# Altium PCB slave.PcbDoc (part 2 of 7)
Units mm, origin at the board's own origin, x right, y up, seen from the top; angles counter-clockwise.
Board outline 160 x 100 mm, 6 copper layers (Top, FUSED_VBAT-, Signals1, Signals2, SUPPLY, Bottom), stack 1.67 mm thick; 597 components, 381 nets, 1695 pads, 3029 vias.

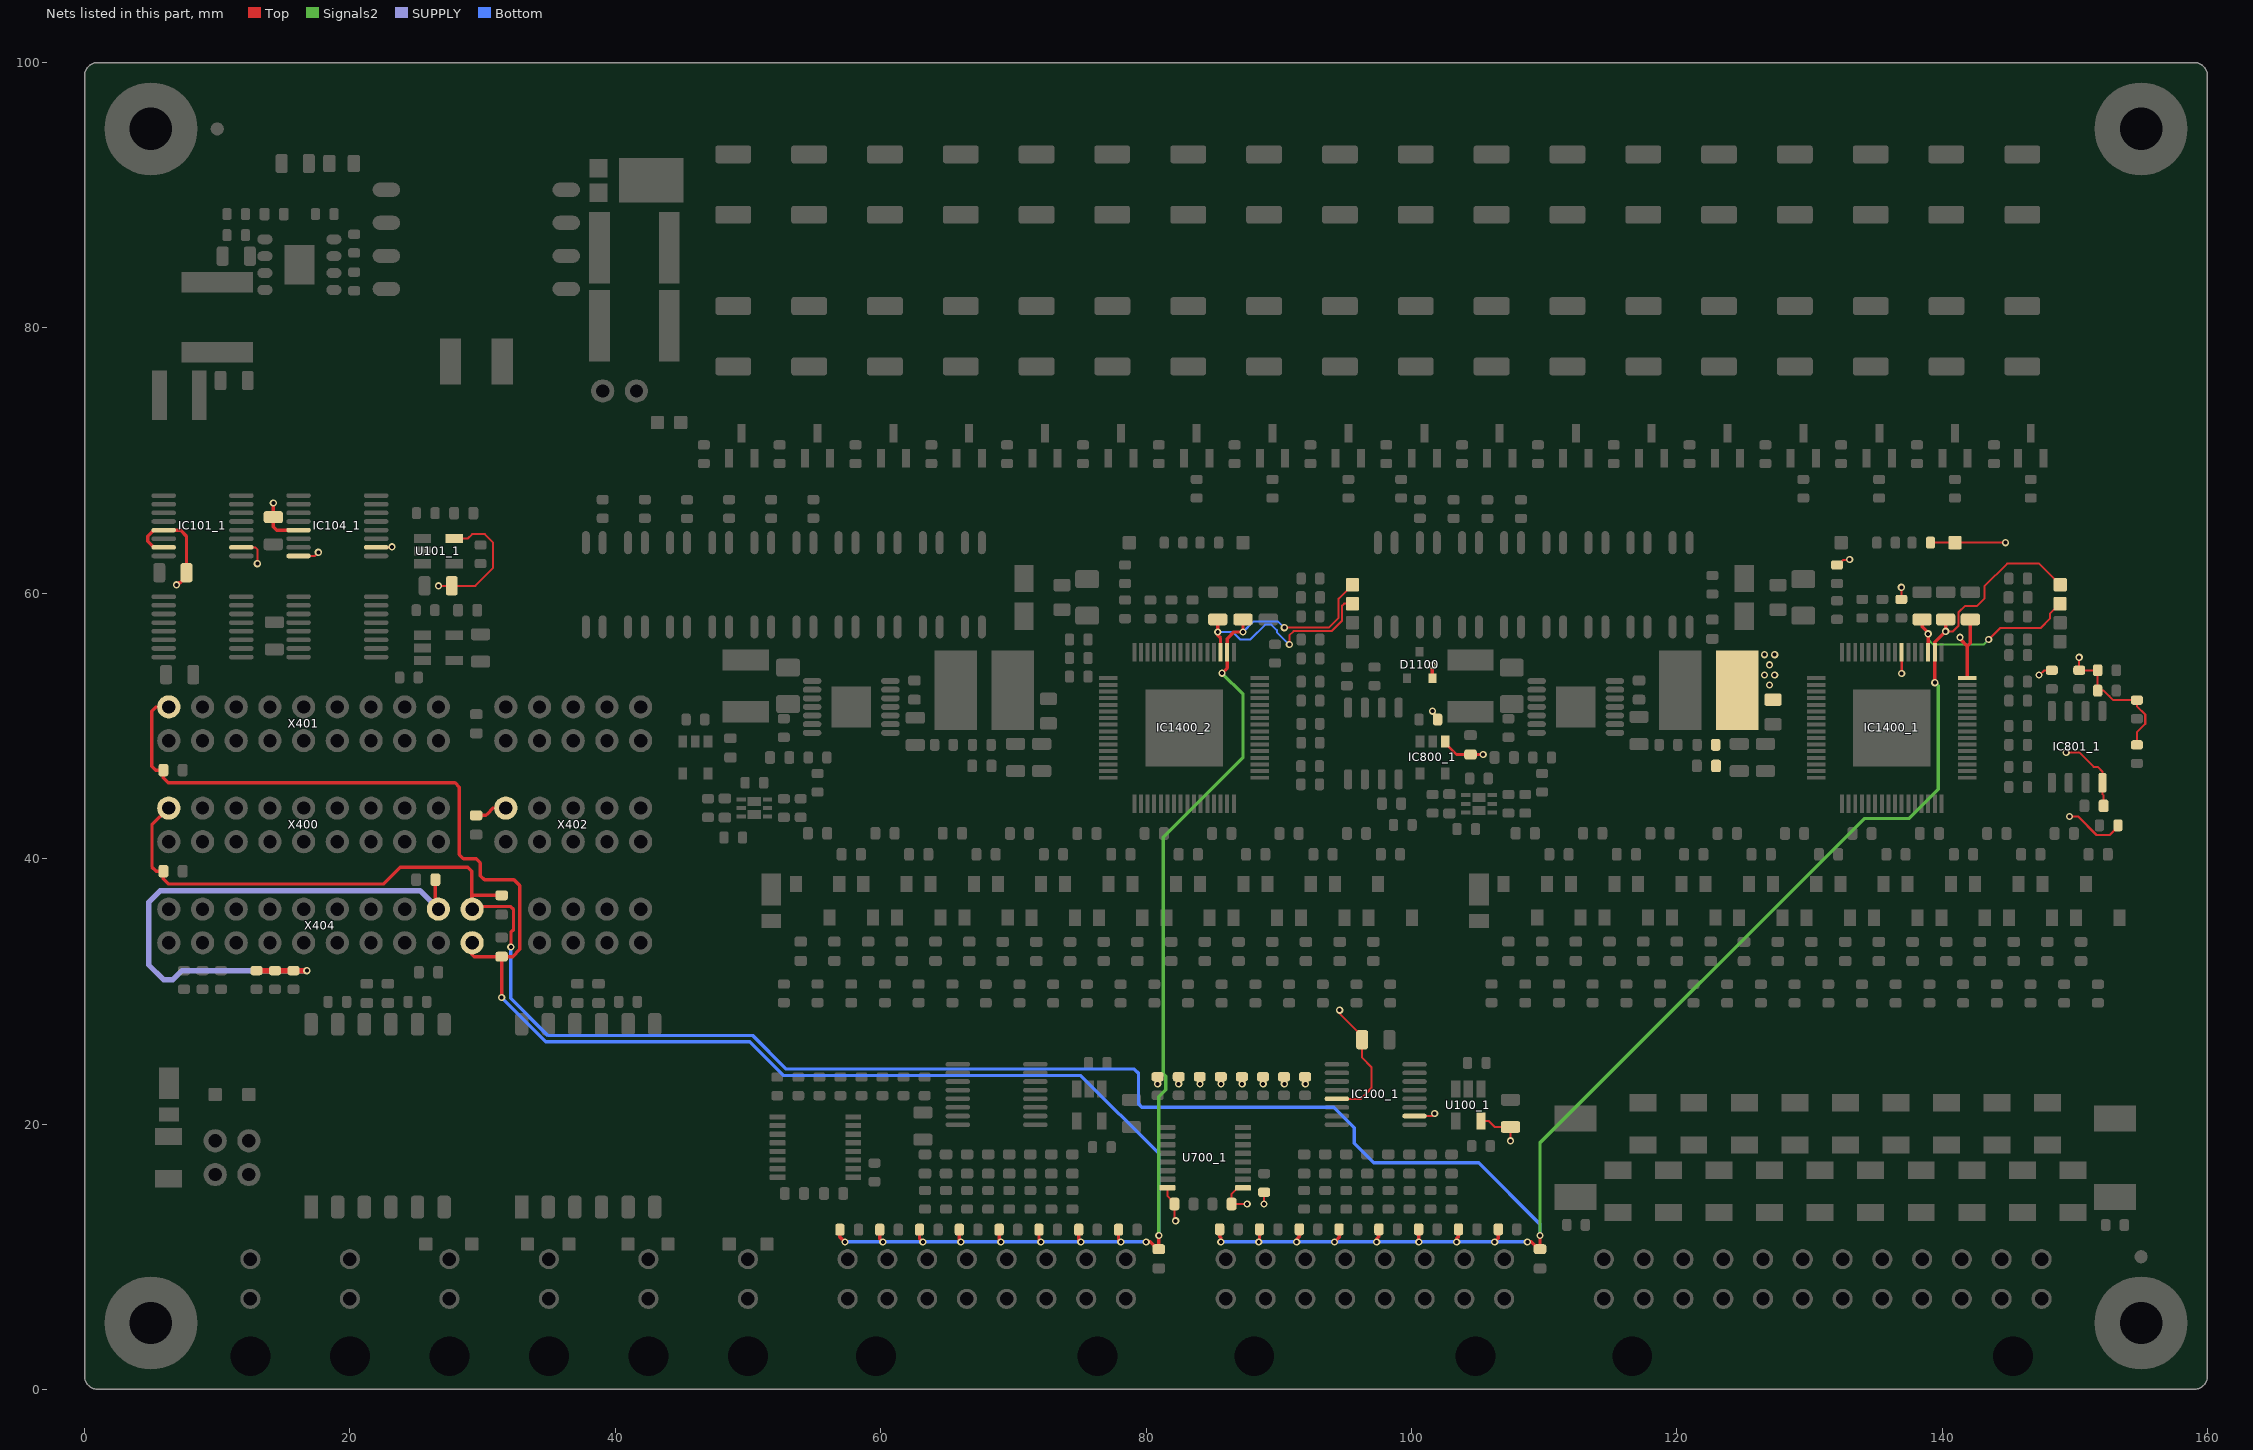
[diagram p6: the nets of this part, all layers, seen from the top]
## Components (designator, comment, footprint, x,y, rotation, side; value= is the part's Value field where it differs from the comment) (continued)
Z1312_1 "MMSZ4692T1G" ONSC-SOD-123-2-425-04_V 108.585,38.1 r0 top locked (schematic designator Z1312)
Z1312_2 "MMSZ4692T1G" ONSC-SOD-123-2-425-04_V 55.245,38.1 r0 top locked (schematic designator Z1312)
Z1313_1 "MMSZ4692T1G" ONSC-SOD-123-2-425-04_V 111.125,35.56 r0 top locked (schematic designator Z1313)
Z1313_2 "MMSZ4692T1G" ONSC-SOD-123-2-425-04_V 57.785,35.56 r0 top locked (schematic designator Z1313)
Z1314_1 "MMSZ4692T1G" ONSC-SOD-123-2-425-04_V 113.665,38.1 r0 top locked (schematic designator Z1314)
Z1314_2 "MMSZ4692T1G" ONSC-SOD-123-2-425-04_V 60.325,38.1 r0 top locked (schematic designator Z1314)
Z1315_1 "MMSZ4692T1G" ONSC-SOD-123-2-425-04_V 116.205,35.56 r0 top locked (schematic designator Z1315)
Z1315_2 "MMSZ4692T1G" ONSC-SOD-123-2-425-04_V 62.865,35.56 r0 top locked (schematic designator Z1315)
Z1316_1 "MMSZ4692T1G" ONSC-SOD-123-2-425-04_V 118.725,38.1 r0 top locked (schematic designator Z1316)
Z1316_2 "MMSZ4692T1G" ONSC-SOD-123-2-425-04_V 65.405,38.1 r0 top locked (schematic designator Z1316)
Z1317_1 "MMSZ4692T1G" ONSC-SOD-123-2-425-04_V 121.285,35.56 r0 top locked (schematic designator Z1317)
Z1317_2 "MMSZ4692T1G" ONSC-SOD-123-2-425-04_V 67.945,35.56 r0 top locked (schematic designator Z1317)

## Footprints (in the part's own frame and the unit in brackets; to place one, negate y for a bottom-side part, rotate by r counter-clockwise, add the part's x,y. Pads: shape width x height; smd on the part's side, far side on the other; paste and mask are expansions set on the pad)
ADI-RJ-5_M [mm] "SOT-23, 5-Leads, Body 2.9x1.6mm, Pitch 0.95mm, IPC Low Density"
  rect 1.3x0.7 smd: 1(-1.2,0.95) 2(-1.2,0) 3(-1.2,-0.95) 4(1.2,-0.95) 5(1.2,0.95)
  silkscreen extent -1.32,-1.5 0.15,1.98, body extent -0.85,-1.5 0.85,1.5, height 1.45
ADI-RU-16_M [mm] "SOP, 16-Leads, Body 5x4.4mm, Pitch 0.65mm, IPC Low Density"
  oval 1.85x0.35 smd: 1(-2.925,2.275) 2(-2.925,1.625) 3(-2.925,0.975) 4(-2.925,0.325) 5(-2.925,-0.325) 6(-2.925,-0.975) 7(-2.925,-1.625) 8(-2.925,-2.275) 9(2.925,-2.275) 10(2.925,-1.625) 11(2.925,-0.975) 12(2.925,-0.325) 13(2.925,0.325) 14(2.925,0.975) 15(2.925,1.625) 16(2.925,2.275)
  silkscreen extent -3.05,-2.55 1.6,3.12, body extent -2.25,-2.55 2.25,2.55, height 1.2
CAPC1608X08N [mm] "Chip Capacitor, 2-Leads, Body 1,60x0,80mm, IPC Medium Density"
  rrect50% 0.75x0.95 smd: 1(-0.725,0) 2(0.725,0)
  body extent -0.85,-0.45 0.85,0.45, height 0.8
CAPC2012X14N [mm] "Chip Capacitor, 2-Leads, Body 2,00x1,25mm, IPC Medium Density"
  rrect40% 0.9x1.45 smd: 1(-1.025,0) 2(1.025,0)
  silkscreen extent -0.2,-0.63 0.2,0.63, body extent -1.1,-0.72 1.1,0.72, height 1.45
CAPC2220(5750)230_N [mm] "Chip Capacitor, Body 5.7x5.0mm, Height 2.3mm, IPC Medium Density"
  rect 1.55x5.4 smd: 1(-2.625,0) 2(2.625,0)
  silkscreen extent -1.45,-2.6 1.45,2.6, body extent -3.05,-2.7 3.05,2.7, height 2.3
CAPC3216X18N [mm] "Chip Capacitor, 2-Leads, Body 3,20x1,60mm, IPC Medium Density"
  rrect30% 1.35x1.8 smd: 1(-1.375,0) 2(1.375,0)
  silkscreen extent -0.3,-0.8 0.3,0.8, body extent -1.7,-0.9 1.7,0.9, height 1.8
CAPC4532X16N [mm] "Chip Capacitor, 2-Leads, Body 4,50x3,20mm, IPC Medium Density"
  rect 1.6x3.5 smd: 1(-1.95,0) 2(1.95,0)
  silkscreen extent -0.75,-1.65 0.75,1.65, body extent -2.4,-1.75 2.4,1.75, height 1.55
DIOD-POWERDI123-2_V [mm] "SOD, 2-Leads, Body 2.8x1.78mm"
  rect 1.05x1.5 smd: 1(-1.525,0)
  rect 2.4x1.5 smd: 2(0.85,0)
  silkscreen extent 2.55,-0.89 2.55,0.89, body extent -1.4,-0.89 1.4,0.89, height 1.01
Fiducial_2 [mm] "Fiducial Round 1mm"
  round 1 smd paste-0.5 mask+0.5: 0(0,0)
  Top keep-out circle w0.2: c0,0 r0.9
HM2102NL [mil]
  rect 67.5x40 smd: 1(-271.65,196.85)
  rrect50% 67.5x40 smd: 2(-271.65,117.85) 3(-271.65,38.85) 4(-271.65,-40.15) 5(-271.65,-119.15) 6(-271.65,-198.15) 7(270.85,-198.15) 8(270.85,-119.15) 9(270.85,-40.15) 10(270.85,38.85) 11(270.85,117.85) 12(270.85,196.85)
  silkscreen extent -224,-300 224,300, body extent -224,-299 224,299, height 197
Hole_3.2_Iso [mm]
  round 7 hole 3.2: Hole_3.2(0,0)
LEDC1608X07N [mm] "LED, 2-Leads, Body 1,60x0,80mm, IPC Medium Density"
  rrect50% 0.7x0.9 smd: 1(-0.7,0) 2(0.7,0)
  silkscreen extent -1.35,0.35 -1.25,0.45, body extent -0.8,-0.4 0.8,0.4, height 0.7
LITTLEFUSE_448 [mm] "Littlefuse 448 Series, 2-Leads, Body 6,10x2,69mm, IPC Medium Density"
  rect 1.96x3.15 smd: 1(-2.95,0) 2(2.95,0)
  silkscreen extent -1.1,-1.47 1.1,1.48, body extent -3.15,-1.47 3.15,1.47, height 2.94
LITTLEFUSE_466 [mm] "Littlefuse 466 Series, 2-Leads, Body 3,18x1,52mm"
  rect 1.3x2.03 smd: 1(-1.59,0) 2(1.59,0)
  silkscreen extent -0.55,-0.92 0.55,0.91, body extent -1.65,-0.82 1.65,0.82, height 0.66
LT-S8E-8_V [mm] "SOIC, 8-Leads, Body 4.9x3.9mm, Pitch 1.27mm, Thermal Pad 3.25x2.26mm, Recommended"
  oval 1.143x0.76 smd: 1(-2.602,1.905) 2(-2.602,0.635) 3(-2.602,-0.635) 4(-2.602,-1.905) 5(2.601,-1.905) 6(2.601,-0.635) 7(2.601,0.635) 8(2.601,1.905)
  rect 2.26x2.99 smd: 9(0,0)
  silkscreen extent -2.73,-2.5 1.62,2.96, body extent -3.01,-2.45 3.01,2.45, height 1.75
MOLEX_MICROFIT_01x2_THT [mil] "Micro-Fit 3.0 Right Angle Header, 3.00mm Pitch, Dual Row, 2 Circuits, with Snap-in Plastic Peg PCB Lock, Tin, Glow Wire Capable, Black, 43045-0200"
  round 60 hole 40: 1(0,-170) 2(0,-287.99)
  round 39.37 hole 117.99 unplated paste+0 mask+4: ""(0,0)
  silkscreen extent -137,-209 137,85, body extent -141,-301 141,181, height 345
MOLEX_MICROFIT_08x2_THT [mil] "Micro-Fit 3.0 Right Angle Header, 3.00mm Pitch, Dual Row, 16 Circuits, with Snap-in Plastic Peg PCB Lock, Tin, Glow Wire Capable, Black, 43045-1600"
  round 60 hole 40: 1(-412.99,-170) 2(-295,-170) 3(-177.01,-170) 4(-59.02,-170) 5(59.02,-170) 6(177.01,-170) 7(295,-170) 8(412.99,-170) 9(-412.99,-287.99) 10(-295,-287.99) 11(-177.01,-287.99) 12(-59.02,-287.99) 13(59.02,-287.99) 14(177.01,-287.99) 15(295,-287.99) 16(412.99,-287.99)
  round 39.37 hole 117.99 unplated paste+0 mask+4: ""(-328.5,0) ""(328.5,0)
  silkscreen extent -551,-209 551,85, body extent -554,-301 554,181, height 345
MOLEX_MICROFIT_12x2_THT [mil] "Micro-Fit 3.0 Right Angle Header, 3.00mm Pitch, Dual Row, 24 Circuits, with Snap-in Plastic Peg PCB Lock, Tin, Glow Wire Capable, Black, 43045-2400"
  round 60 hole 40: 1(-649.49,-170) 2(-530.98,-170) 3(-412.99,-170) 4(-295,-170) 5(-177.01,-170) 6(-59.02,-170) 7(59.02,-170) 8(177.01,-170) 9(295,-170) 10(412.99,-170) 11(530.98,-170) 12(649.49,-170) 13(-649.49,-287.99) 14(-530.98,-287.99) 15(-412.99,-287.99) 16(-295,-287.99) 17(-177.01,-287.99) 18(-59.02,-287.99) 19(59.02,-287.99) 20(177.01,-287.99) 21(295,-287.99) 22(412.99,-287.99) 23(530.98,-287.99) 24(649.49,-287.99)
  round 39.37 hole 117.99 unplated paste+0 mask+4: ""(-565,0) ""(565,0)
  silkscreen extent -789,-209 790,85, body extent -790,-301 790,181, height 345
NXP-SOT23-3_V [mm] "SOT23, 3-Leads, Body 1.3x2.9mm, Pitch 0.95mm"
  rect 0.6x0.7 smd paste-0.05: 1(0.95,1) 2(-0.95,1) 3(0,-1)
  silkscreen extent -1.45,-0.65 1.45,1.79, body extent -1.45,-0.65 1.45,0.65, height 1.1
NXP-SOT23_N [mm] "SOT23, 3-Leads, Body 3x1.4mm, Pitch 0.95mm, IPC Medium Density"
  rect 1.4x0.6 smd: 1(-0.95,0.95) 2(-0.95,-0.95) 3(0.95,0)
  silkscreen extent -1.07,-1.5 0.7,1.92, body extent -0.7,-1.5 0.7,1.5, height 1.1
ONSC-SOD-123-2-425-04_V [mm] "SOD, 2-Leads, Body 2.69x1.6mm"
  rect 0.91x1.22 smd: 1(-1.635,0) 2(1.635,0)
  silkscreen extent -1.76,-0.8 0.78,1.28, body extent -1.35,-0.8 1.35,0.8, height 1.35
PBSS4112PANP [mm]
  rect 0.7x0.3 smd: 1(-0.995,0.65) 2(-0.995,0) 3(-0.995,-0.65) 4(0.995,-0.65) 5(0.995,0) 6(0.995,0.65)
  rect 1x0.67 smd: 7(0,0.49) 8(0,-0.49)
  silkscreen extent -1.5,-1.2 1.05,1.25, body extent -1.05,-1.05 1.05,1.05, height 0.65
Pinheader_2.54_2 [mm] "Pinheader, 2.54mm, gerade"
  round 1.75 hole 1: 1(-1.27,0) 2(1.27,0)
  silkscreen extent -2.47,-1.2 2.47,1.2, body extent -2.54,-1.27 2.54,1.27, height 8.74
Pinheader_2.54_2x2 [mm] "Pinheader, 2.54mm, gerade, 2-reihig"
  round 1.75 hole 1: 1(-1.27,-1.27) 2(-1.27,1.27) 3(1.27,-1.27) 4(1.27,1.27)
  silkscreen extent -2.47,-2.47 2.47,2.47, body extent -2.54,-2.54 2.54,2.54, height 8.74
Pinheader_2.54_2x4 [mm] "Pinheader, 2.54mm, gerade, 2-reihig"
  round 1.75 hole 1: 1(-3.81,-1.27) 2(-3.81,1.27) 3(-1.27,-1.27) 4(-1.27,1.27) 5(1.27,-1.27) 6(1.27,1.27) 7(3.81,-1.27) 8(3.81,1.27)
  silkscreen extent -5.01,-2.47 5.01,2.47, body extent -5.08,-2.54 5.08,2.54, height 8.74
Pinheader_2.54_2x5 [mm]
  round 1.75 hole 1: 1(-5.08,-1.27) 2(-5.08,1.27) 3(-2.54,-1.27) 4(-2.54,1.27) 5(0,-1.27) 6(0,1.27) 7(2.54,-1.27) 8(2.54,1.27) 9(5.08,-1.27) 10(5.08,1.27)
  silkscreen extent -6.28,-2.47 6.28,2.47, body extent -6.35,-2.54 6.35,2.54, height 8.74
Pinheader_2.54_2x9 [mm] "Pinheader, 2.54mm, gerade, 2-reihig"
  round 1.75 hole 1: 1(-10.16,-1.27) 2(-10.16,1.27) 3(-7.62,-1.27) 4(-7.62,1.27) 5(-5.08,-1.27) 6(-5.08,1.27) 7(-2.54,-1.27) 8(-2.54,1.27) 9(0,-1.27) 10(0,1.27) 11(2.54,-1.27) 12(2.54,1.27) 13(5.08,-1.27) 14(5.08,1.27) 15(7.62,-1.27) 16(7.62,1.27) 17(10.16,-1.27) 18(10.16,1.27)
  silkscreen extent -11.43,-2.47 11.43,2.47, body extent -11.43,-2.54 11.43,2.54, height 8.74
Pinheader_2.54_2x10 [mm] "Pinheader, 2.54mm, gerade, 2-reihig"
  round 1.75 hole 1: 1(-11.43,-1.27) 2(-11.43,1.27) 3(-8.89,-1.27) 4(-8.89,1.27) 5(-6.35,-1.27) 6(-6.35,1.27) 7(-3.81,-1.27) 8(-3.81,1.27) 9(-1.27,-1.27) 10(-1.27,1.27) 11(1.27,-1.27) 12(1.27,1.27) 13(3.81,-1.27) 14(3.81,1.27) 15(6.35,-1.27) 16(6.35,1.27) 17(8.89,-1.27) 18(8.89,1.27) 19(11.43,-1.27) 20(11.43,1.27)
  silkscreen extent -12.7,-2.47 12.7,2.47, body extent -12.7,-2.54 12.7,2.54, height 8.74
PowerDI5 [mm] "PowerDI5, 3-Leads, Body 3,97x6,50mm"
  rect 4.86x3.36 smd: 1(1.126,0)
  rect 1.39x1.4 smd: 2(-2.856,0.92) 3(-2.856,-0.92)
  silkscreen extent -1.88,-2.05 3.63,2.32, body extent -3.25,-2.02 3.25,2.02, height 1.15
PW0016A_L [mm] "SOP, 16-Leads, Body 5.1x4.5mm, Pitch 0.65mm, IPC High Density"
  rrect25% 1.2x0.4 smd: 1(-2.85,2.275) 2(-2.85,1.625) 3(-2.85,0.975) 4(-2.85,0.325) 5(-2.85,-0.325) 6(-2.85,-0.975) 7(-2.85,-1.625) 8(-2.85,-2.275) 9(2.85,-2.275) 10(2.85,-1.625) 11(2.85,-0.975) 12(2.85,-0.325) 13(2.85,0.325) 14(2.85,0.975) 15(2.85,1.625) 16(2.85,2.275)
  silkscreen extent -2.98,-2.55 1.85,3.15, body extent -3.21,-2.5 3.21,2.5, height 1
PWP0014A [mm] "TI PWP0014A Package"
  oval 1.4x0.45 smd: 1(-2.95,1.95) 2(-2.95,1.3) 3(-2.95,0.65) 4(-2.95,0) 5(-2.95,-0.65) 6(-2.95,-1.3) 7(-2.95,-1.95) 8(2.95,-1.95) 9(2.95,-1.3) 10(2.95,-0.65) 11(2.95,0) 12(2.95,0.65) 13(2.95,1.3) 14(2.95,1.95)
  rect 3x3.1 smd: 15(0,0)
  silkscreen extent -3.07,-2.55 1.85,2.85, body extent -3.2,-2.55 3.2,2.55, height 1.2
RESC1608X05N [mm] "Chip Resistor, 2-Leads, Body 1,60x0,80mm, IPC Medium Density"
  rrect50% 0.7x0.9 smd: 1(-0.7,0) 2(0.7,0)
  body extent -0.85,-0.45 0.85,0.45, height 0.45
RESC2012X05N [mm] "Chip Resistor, 2-Leads, Body 2,00x1,20mm, IPC Medium Density"
  rrect40% 0.95x1.3 smd: 1(-0.925,0) 2(0.925,0)
  silkscreen extent -0.05,-0.55 0.05,0.55, body extent -1.05,-0.65 1.05,0.65, height 0.5
RESC5025X07N [mm] "Chip Resistor, 2-Leads, Body 5,00x2,50mm, IPC Medium Density"
  rrect30% 1.35x2.7 smd: 1(-2.275,0) 2(2.275,0)
  silkscreen extent -1.2,-1.25 1.2,1.25, body extent -2.6,-1.35 2.6,1.35, height 0.7
SOIC127P600X175-8N [mm] "SOIC, 8-Leads, Body 4,90x3,90mm, Pitch 1,27mm, IPC Medium Density"
  rrect50% 1.5x0.6 smd: 1(-2.7,1.905) 2(-2.7,0.635) 3(-2.7,-0.635) 4(-2.7,-1.905) 5(2.7,-1.905) 6(2.7,-0.635) 7(2.7,0.635) 8(2.7,1.905)
  silkscreen extent -2.8,-2.45 1.55,2.8, body extent -3,-2.45 3,2.45, height 1.75
SOIC127P700X220-4N [mm] "SOIC, 4-Leads, Body 2,60x4,40mm, Pitch 1,27mm, IPC Medium Density"
  oval 1.75x0.6 smd: 1(-3.175,0.635) 2(-3.175,-0.635) 3(3.175,-0.635) 4(3.175,0.635)
  silkscreen extent -3.3,-1.45 1.9,1.61, body extent -3.5,-1.45 3.5,1.45, height 2.2
SOT-23-OT5_L [mm] "SOT23, 5-Leads, Body 2.9x1.7mm, Pitch 0.95mm, Lead Span 2.8mm, IPC High Density"
  rect 0.9x0.65 smd: 1(-1.2,0.95) 2(-1.2,0) 3(-1.2,-0.95) 4(1.2,-0.95) 5(1.2,0.95)
  silkscreen extent -1.32,-1.55 0.35,1.95, body extent -0.9,-1.55 0.9,1.55, height 1.45
Testpoint_S1 [mm] "Testpunkt, quardratisch 1mm"
  rrect20% 1x1 smd paste-0.5: 1(0,0)
TSQFP50P1200X1200X160_HS-65N [mm] "TSQFP, 64-Leads, Body 10,00x10,00mm, Pitch 0,50mm, Thermal Pad 5,84x5,84mm, IPC Medium Density"
  rect 1.4x0.3 smd: 1(-5.7,3.75) 2(-5.7,3.25) 3(-5.7,2.75) 4(-5.7,2.25) 5(-5.7,1.75) 6(-5.7,1.25) 7(-5.7,0.75) 8(-5.7,0.25) 9(-5.7,-0.25) 10(-5.7,-0.75) 11(-5.7,-1.25) 12(-5.7,-1.75) 13(-5.7,-2.25) 14(-5.7,-2.75) 15(-5.7,-3.25) 16(-5.7,-3.75) 33(5.7,-3.75) 34(5.7,-3.25) 35(5.7,-2.75) 36(5.7,-2.25) 37(5.7,-1.75) 38(5.7,-1.25) 39(5.7,-0.75) 40(5.7,-0.25) 41(5.7,0.25) 42(5.7,0.75) 43(5.7,1.25) 44(5.7,1.75) 45(5.7,2.25) 46(5.7,2.75) 47(5.7,3.25) 48(5.7,3.75)
  rect 0.3x1.4 smd: 17(-3.75,-5.7) 18(-3.25,-5.7) 19(-2.75,-5.7) 20(-2.25,-5.7) 21(-1.75,-5.7) 22(-1.25,-5.7) 23(-0.75,-5.7) 24(-0.25,-5.7) 25(0.25,-5.7) 26(0.75,-5.7) 27(1.25,-5.7) 28(1.75,-5.7) 29(2.25,-5.7) 30(2.75,-5.7) 31(3.25,-5.7) 32(3.75,-5.7) 49(3.75,5.7) 50(3.25,5.7) 51(2.75,5.7) 52(2.25,5.7) 53(1.75,5.7) 54(1.25,5.7) 55(0.75,5.7) 56(0.25,5.7) 57(-0.25,5.7) 58(-0.75,5.7) 59(-1.25,5.7) 60(-1.75,5.7) 61(-2.25,5.7) 62(-2.75,5.7) 63(-3.25,5.7) 64(-3.75,5.7)
  rect 5.84x5.84 smd: 65(0,0)
  silkscreen extent -5.82,-4.6 4.6,4.6, body extent -6,-6 6,6, height 1.6
TYS6045221M-10 [mm] "Precision Wire Wound Inductor, 2-Leads, Body 6,00x6,00mm, IPC Medium Density"
  rect 3.2x6 smd: 1(-2.15,0) 2(2.15,0)
  silkscreen extent -4.05,-3.15 0.15,3.15, body extent -3.1,-3 3.1,3, height 4.8
VISH-DO-214AC-2_L [mm] "DO-214AC, 2-Leads, Body 4.5x2.79mm, IPC High Density"
  rect 2.05x1.45 smd: 1(-1.425,0) 2(1.425,0)
  silkscreen extent -3.12,-1.4 2.25,1.4, body extent -2.25,-1.4 2.25,1.4, height 2.29
"WE-LQS 4018" [mm] "SMD Power Inductor, 2-Leads, Body 4.0x4.0mm"
  rect 1.1x3.7 smd: 1(-1.5,0) 2(1.5,0)
  body extent -2,-2 2,2, height 1.78
WE_750313457 [mm] "Würth Elektronik 750313457"
  oval 2.08x1.07 smd: 1(-6.78,-3.735) 2(-6.78,-1.245) 3(-6.78,1.245) 4(-6.78,3.735) 5(6.78,3.735) 6(6.78,1.245) 7(6.78,-1.245) 8(6.78,-3.735)
  silkscreen extent -6.98,-6.65 5.43,6.65, body extent -7.62,-6.65 7.62,6.65, height 11.44

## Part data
C100_1 C100_2 C400 C401 C402 C403 C404 C405 C406 C407 C602_1 C602_2 C604_1 C604_2 C607_1 C607_2 C700_1 C700_2 C701_1 C701_2 C800_1 C800_2 C801_1 C801_2 C903 C1100: library part gen_C_ceramic_100n_50V_X7R_0603, "MLCC", Capacitance=100n, Case EIA=0603, Case Metric=1608, Dielectric=X7R, PnP Package=C_0603_10, PnP Value=100n/50V/X7R, Rated Voltage=50V, Supplier Part Number 1=2525267
C101_1 C101_2 C102_1 C102_2 C103_1 C103_2 C104_1 C104_2 C105_1 C105_2 C603_1 C603_2 C900 C904 C1401_1 C1401_2 C1402_1 C1402_2 C1403_1 C1403_2: library part gen_C_ceramic_1u_50V_X7R_0805, "MLCC", Capacitance=1u, Case EIA=0805, Case Metric=2012, Dielectric=X7R, Operating Temperature="-55°C - +125°C", Rated Voltage=50V, Supplier Part Number 1=2672199, Tolerance="± 10%"
C106_1 C106_2 C107_1 C107_2 C108_1 C108_2 C109_1 C109_2 C110_1 C110_2 C111_1 C111_2 C112_1 C112_2 C113_1 C113_2 C114_1 C114_2 C115_1 C115_2 C608_1 C608_2 C1300_1 C1300_2 C1301_1 C1301_2 C1302_1 C1302_2 C1303_1 C1303_2 C1304_1 C1304_2 C1305_1 C1305_2 C1306_1 C1306_2 C1307_1 C1307_2 C1308_1 C1308_2 C1309_1 C1309_2 C1310_1 C1310_2 C1311_1 C1311_2 C1312_1 C1312_2 C1313_1 C1313_2 C1314_1 C1314_2 C1315_1 C1315_2 C1316_1 C1316_2 C1317_1 C1317_2 C1318_1 C1318_2 C1319_1 C1319_2 C1320_1 C1320_2 C1321_1 C1321_2 C1322_1 C1322_2 C1323_1 C1323_2 C1324_1 C1324_2 C1325_1 C1325_2 C1326_1 C1326_2 C1327_1 C1327_2 C1328_1 C1328_2 C1329_1 C1329_2 C1330_1 C1330_2 C1331_1 C1331_2 C1332_1 C1332_2 C1333_1 C1333_2 C1334_1 C1334_2 C1335_1 C1335_2: library part gen_C_ceramic_10n_100V_X7R_0603, "MLCC", Capacitance=10n, Case EIA=0603, Case Metric=1608, Dielectric=X7R, Rated Voltage=100V, Supplier Part Number 1=1301715
C600_1 C600_2: library part gen_C_ceramic_1u_250V_X7R_1812, "MLCC", Capacitance=1u, Case EIA=1812, Case Metric=4532, Dielectric=X7T, Rated Voltage=250V, Supplier Part Number 1=2435499
C601_1 C601_2 C1400_1 C1400_2: library part gen_C_ceramic_100n_200V_X7R_1206, "MLCC", Capacitance=100n, Case EIA=1206, Case Metric=3216, Dielectric=X7R, Rated Voltage=200V, Supplier Part Number 1=2673161
C605_1 C605_2 C606_1 C606_2: library part gen_C_ceramic_2u2_10V_X7R_0805, "MLCC", Capacitance=2u2, Case EIA=0805, Case Metric=2012, Dielectric=X7R, Rated Voltage=10V, Supplier Part Number 1=2478259
C902: library part gen_C_ceramic_22u_50V_X7R_2220_stacked, "MLCC", Capacitance=22u, Case EIA=2220, Case Metric=5750, Dielectric=X7R, Rated Voltage=50V, Supplier Part Number 1=399-5797-1-ND
C905: library part gen_C_ceramic_470p_100V_X7R_0805, "MLCC", Capacitance=470p, Case EIA=0805, Case Metric=2012, Dielectric=X7R, Rated Voltage=100V, Supplier Part Number 1=2070482
C906: library part gen_C_ceramic_4n7_1000V_X7R_1812, "MLCC", Capacitance=4n7, Case EIA=1812, Case Metric=4532, Dielectric=X7R, Rated Voltage=1000V, Supplier Part Number 1=2834565
C907 C908: library part gen_C_ceramic_2u2_250V_X7R_2220, "MLCC", Capacitance=2u2, Case EIA=2220, Case Metric=5750, Dielectric=X7R, Rated Voltage=250V, Supplier Part Number 1=445-7997-2-ND
C1404_1 C1404_2 C1405_1 C1405_2: library part gen_C_ceramic_100p_50V_C0G_0603, "MLCC", Capacitance=100p, Case EIA=0603, Case Metric=1608, Dielectric=C0G, Rated Voltage=50V, Supplier Part Number 1=2478236, Tolerance="± 10%"
D900 D1400_1 D1400_2: library part CMP-2000-05099-1, "1 A High Voltage Schottky Barrier Rectifier, 0.62 V, -55 to 175 degC, 2- Pin POWERDI123, Pb-Free, Tape and Reel", Average Rectified Current-Max=1A, Forward Voltage=0.77V, Manufacturer="Diodes Inc", Peak Current-Max=40A, Reverse Current-Max=1µA, Reverse Voltage-Max [Vrrm]=100V
D901: library part PDS3200-13, "Schottky Diode 3A 200V 780mV", Breakdown Voltage=200V, Continuous Forward Current=3A, Manufacturer="DIODES Inc", Operating Temperature="-65°C - +150°C", Supplier Part Number 1=1713904
D1100: library part CMP-2000-04915-1, "Schottky Barrier Diode, 30 V, 3-Pin SOT23, RoHS, Tape and Reel", Current Ifsm=600mA, Diode Case Style=SOT-23, Forward Current If(AV)=200mA, Forward Voltage=800mV, Junction Temperature Tj Max=125degC, Manufacturer="NXP Semiconductors", Operating Temperature Max=150degC, Operating Temperature Min=-65degC, Operating Temperature Range=-65degCto+150degC, Package Description="3-Pin Small Outline Transistor, Body 1.3 x 2.9 mm, Pitch 0.95 mm", Package Reference=SOT23-3, Package Version=Feb-16, Repetitive Reverse Voltage Vrrm Max=30V
D1401_1 D1401_2: library part CMP-0548-00243-2, "Transient Voltage Suppressor, 6.40 to 231 V, 85 V Stand-off Voltage, Uni-Directional, -55 to 155 degC, 2-pin DO-214AC, Pb-Free, Tape and Reel", Manufacturer="Vishay Semiconductor", Operating Junction and Storage Temperature Range="-55 to 150 degC"
F300 F320: "Fuse, Surface Mount, NANO2 Series, 500 mA, 125 VAC, 32 VDC, Very Fast Acting, SMD", Manufacturer=Littlefuse, Operating Temperature="-55°C - +125°C", Supplier Part Number 1=1596919
F301 F302 F303 F304 F305 F306 F307 F308 F309 F310 F311 F312 F313 F314 F315 F316 F317 F318 F319: "Fuse, Surface Mount, 466 Series, 250 mA, 125 VAC, 125 VDC, Very Fast Acting, 1206", Manufacturer=Littlefuse, Operating Temperature="-55°C - +90°C", Supplier Part Number 1=9921826
F900: "Fuse, Surface Mount, 466 Series, 1.25 A, 63 VAC, 63 VDC, Very Fast Acting, 1206", Manufacturer=Littlefuse, Operating Temperature="-55°C - +90°C", Supplier Part Number 1=1596526
IC100_1 IC100_2 IC101_1 IC101_2 IC104_1 IC104_2: library part CMP-0798-00197-1, "CMOS, Low Voltage, 2-Wire Serially Controlled, Matrix Switch, -40 to 85 degC, 16-pin SOP (RU-16), Tube", Manufacturer="Analog Devices"
IC800_1 IC800_2: library part CMP-0192-00211-1, "2-Wire High-Accuracy Temperature Sensor, Slave Address 000, 5-Pin SOT-23, -55°C to +125°C Temperature, Tape and Reel"
IC801_1 IC801_2: "Automotive 2-Mbit serial I²C  / bus EEPROM with 1 MHz clock", Manufacturer=STMicroelectronics, Operating Temperature="-40°C - +125°C", PnP Package=SO8N, Supplier Part Number 1=497-16238-1-ND
IC900: library part CMP-0492-02715-1, "Micropower No-Opto Isolated Flyback Converter, 2.8 to 42 V, -40 to 150 degC, 8-Pin SOIC (S8E), RoHS, Tube", Output Current="3.6 A", PartNumber=LT8302, Temperature Max="150 degC", Temperature Min="-40 degC"
IC1400_1 IC1400_2: "18 Cell Multicell Battery Monitor, -40 to 125 degC, Pb-Free", Manufacturer="Linear Technology", Operating Temperature="-40°C - +125°C", PartNumber=LTC6811HG-1#PBF, PnP Package=QFP-64, Supplier Part Number 1=LTC6813HLWE-1#3ZZPBF-ND
L600_1 L600_2: library part TYS6045221M-10, "Power Inductor", Manufacturer="Laird-Signal Integrity Products", Operating Temperature="-55°C - +150°C", Rated Current=590mA, Saturation Current=700mA, Supplier Part Number 1=240-2742-1-ND
L900: library part CMP-1354-00028-1, "WE-LQS SMD Power Inductor, L=10 µH", Inductance="10 µH", Manufacturer="Wuerth Elektronik"
LD1400_1 LD1400_2: library part LED_0603_green_AECQ, "TLMG1100-GS08", Breakdown Voltage=5V, Continuous Forward Current=20mA, Forward Voltage @ 20mA=2.1V, Manufacturer=Vishay, Operating Temperature="-40°C - 100°C", PnP Package=LED_0603, Supplier Part Number 1=2293494
Q600_1 Q600_2: "Dual NPN/PNP Transistor", Manufacturer=Nexperia, Maximum Continous Drain Current (25°C)=1A, Maximum Drain-Source Voltage=120V, Operating Temperature="-55°C - +150°C", Part Name="DUAL PNP/NPN"
R100_1 R100_2 R101_1 R101_2 R102_1 R102_2 R103_1 R103_2 R104_1 R104_2 R105_1 R105_2 R106_1 R106_2 R107_1 R107_2 R601_1 R601_2 R605_1 R605_2 R607_1 R607_2 R700_1 R700_2 R701_1 R701_2 R702_1 R702_2 R703_1 R703_2 R704_1 R704_2 R705_1 R705_2 R706_1 R706_2 R707_1 R707_2 R708_1 R708_2 R800_1 R800_2 R801_1 R801_2 R905 R1118 R1421_1 R1421_2 R1422_1 R1422_2 R1423_1 R1423_2 R1424_1 R1424_2 R1425_1 R1425_2 R1426_1 R1426_2 R1427_1 R1427_2: library part gen_R_10k_0603, "SMD Resistor 10k 0603", Case EIA=0603, Case Metric=1608, Maximum Working Voltage=75V, Operating Temperature="-55°C - +155°C", PnP Package=R_0603, Power=0.1W, Supplier Part Number 1=2073349, Tolerance=1%
R108_1 R108_2 R109_1 R109_2 R112_1 R112_2 R113_1 R113_2 R114_1 R114_2 R115_1 R115_2 R116_1 R116_2 R117_1 R117_2 R118_1 R118_2 R119_1 R119_2: library part gen_R_100R_0603, "SMD Resistor 100R 0603", Case EIA=0603, Case Metric=1608, Maximum Working Voltage=75V, Operating Temperature="-55°C - +155°C", PnP Package=R_0603, Power=0.1W, Supplier Part Number 1=P100HCT-ND, Tolerance=1%
R110_1 R110_2 R111_1 R111_2 R609_1 R609_2 R610_1 R610_2 R1406_1 R1406_2 R1407_1 R1407_2 R1408_1 R1408_2 R1409_1 R1409_2 R1410_1 R1410_2 R1411_1 R1411_2 R1412_1 R1412_2 R1413_1 R1413_2 R1414_1 R1414_2 R1415_1 R1415_2 R1416_1 R1416_2 R1417_1 R1417_2 SJ300 SJ301: library part gen_R_0R_0603, "SMD Resistor 0R 0603", Case EIA=0603, Case Metric=1608, Maximum Working Voltage=75V, Operating Temperature="-55°C - +155°C", PnP Package=R_0603, Power=0.1W, Supplier Part Number 1=2616580
R600_1 R600_2 R606_1 R606_2: library part gen_R_124k_0603, "SMD Resistor 124k 0603", Case EIA=0603, Case Metric=1608, Maximum Working Voltage=75V, Operating Temperature="-55°C - +155°C", PnP Package=R_0603, Power=0.1W, Supplier Part Number 1=2138508, Tolerance=1%
R602_1 R602_2: library part gen_R_1k5_0603, "SMD Resistor 1k5 0603", Case EIA=0603, Case Metric=1608, Maximum Working Voltage=75V, Operating Temperature="-55°C - +155°C", PnP Package=R_0603, Power=0.1W, Supplier Part Number 1=2616745, Tolerance=1%
R603_1 R603_2: library part gen_R_1k_0603, "SMD Resistor 1k 0603", Case EIA=0603, Case Metric=1608, Maximum Working Voltage=75V, Operating Temperature="-55°C - +155°C", PnP Package=R_0603, Power=0.1W, Supplier Part Number 1=1652848, Tolerance=1%
R604_1 R604_2: library part gen_R_1R_0805, "SMD Resistor 1R 0805", Case EIA=0805, Case Metric=2012, Maximum Working Voltage=150V, Operating Temperature="-55°C - +155°C", PnP Package=R_0805, Power=0.125W, Supplier Part Number 1=2616757, Tolerance=1%
R608_1 R608_2: library part gen_R_68k_0603, "SMD Resistor 68k 0603", Case EIA=0603, Case Metric=1608, Maximum Working Voltage=75V, Operating Temperature="-55°C - +155°C", PnP Package=R_0603, Power=0.1W, Tolerance=1%
R900: library part gen_R_390k_0603, "SMD Resistor 390k 0603", Case EIA=0603, Case Metric=1608, Maximum Working Voltage=75V, Operating Temperature="-55°C - +155°C", PnP Package=R_0603, Power=0.1W, Supplier Part Number 1=2303278, Tolerance=1%
R901: library part gen_R_86k6_0603, "SMD Resistor 86k6 0603", Case EIA=0603, Case Metric=1608, Maximum Working Voltage=75V, Operating Temperature="-55°C - +155°C", PnP Package=R_0603, Power=0.1W, Supplier Part Number 1=2059490, Tolerance=1%
R902: library part gen_R_115k_0603, "SMD Resistor 115k 0603", Case EIA=0603, Case Metric=1608, Maximum Working Voltage=75V, Operating Temperature="-55°C - +155°C", PnP Package=R_0603, Power=0.1W, Supplier Part Number 1=2073367, Tolerance=1%
R903: library part gen_R_39R_0805, "SMD Resistor 39R 0805", Case EIA=0805, Case Metric=2012, Maximum Working Voltage=150V, Operating Temperature="-55°C - +155°C", PnP Package=R_0805, Power=0.125W, Supplier Part Number 1=1750736, Tolerance=1%
R904: library part gen_R_220k_0603, "SMD Resistor 220k 0603", Case EIA=0603, Case Metric=1608, Maximum Working Voltage=75V, Operating Temperature="-55°C - +155°C", PnP Package=R_0603, Power=0.1W, Tolerance=1%
R1100 R1101 R1102 R1103 R1104 R1105 R1106 R1107 R1108 R1109 R1110 R1111 R1112 R1113 R1114 R1115 R1116 R1117: library part gen_R_150R_0603, "SMD Resistor 150R 0603", Case EIA=0603, Case Metric=1608, Maximum Working Voltage=75V, Operating Temperature="-55°C - +155°C", PnP Package=R_0603, Power=0.1W, Supplier Part Number 1=2303076, Tolerance=1%
R1300_1 R1300_2 R1301_1 R1301_2 R1302_1 R1302_2 R1303_1 R1303_2 R1304_1 R1304_2 R1305_1 R1305_2 R1306_1 R1306_2 R1307_1 R1307_2 R1308_1 R1308_2 R1309_1 R1309_2 R1310_1 R1310_2 R1311_1 R1311_2 R1312_1 R1312_2 R1313_1 R1313_2 R1314_1 R1314_2 R1315_1 R1315_2 R1316_1 R1316_2 R1317_1 R1317_2 R1318_1 R1318_2: library part gen_R_100R_0603, "SMD Resistor 100R 0603", Case EIA=0603, Case Metric=1608, Maximum Working Voltage=75V, Operating Temperature="-55°C - +155°C", PnP Package=R_0603, Power=0.1W, Supplier Part Number 1=2303059, Tolerance=1%
R1400_1 R1400_2 R1419_1 R1419_2 R1420_1 R1420_2: library part gen_R_1k2_0603, "SMD Resistor 1k2 0603", Case EIA=0603, Case Metric=1608, Maximum Working Voltage=75V, Operating Temperature="-55°C - +155°C", PnP Package=R_0603, Power=0.1W, Supplier Part Number 1=2073370, Tolerance=1%
R1401_1 R1401_2: library part gen_R_100R_0805, "SMD Resistor 100R 0805", Case EIA=0805, Case Metric=2012, Maximum Working Voltage=150V, Operating Temperature="-55°C - +155°C", PnP Package=R_0805, Power=0.125W, Supplier Part Number 1=1469862, Tolerance=1%
R1402_1 R1402_2: library part gen_R_820R_0603, "SMD Resistor 820R 0603", Case EIA=0603, Case Metric=1608, Maximum Working Voltage=75V, Operating Temperature="-55°C - +155°C", PnP Package=R_0603, Power=0.1W, Supplier Part Number 1=1469841, Tolerance=1%
R1403_1 R1403_2: library part gen_R_270R_0603, "SMD Resistor 270R 0603", Case EIA=0603, Case Metric=1608, Maximum Working Voltage=75V, Operating Temperature="-55°C - +155°C", PnP Package=R_0603, Power=0.1W, Supplier Part Number 1=2141320, Tolerance=1%
R1404_1 R1404_2: library part gen_R_1M_0603, "SMD Resistor 1M 0603", Case EIA=0603, Case Metric=1608, Maximum Working Voltage=75V, Operating Temperature="-55°C - +155°C", PnP Package=R_0603, Power=0.1W, Supplier Part Number 1=1469746, Tolerance=1%
R1405_1 R1405_2 R1418_1 R1418_2: library part gen_R_120R_0603, "SMD Resistor 120R 0603", Case EIA=0603, Case Metric=1608, Maximum Working Voltage=75V, Operating Temperature="-55°C - +155°C", PnP Package=R_0603, Power=0.1W, Supplier Part Number 1=1652832, Tolerance=1%
R1500 R1501 R1502 R1503 R1504 R1505 R1506 R1507 R1508 R1509 R1510 R1511 R1518 R1519 R1520 R1521 R1522 R1523 R1524 R1525 R1526 R1527 R1528 R1529 R1536 R1537 R1538 R1539 R1540 R1541 R1542 R1543 R1544 R1545 R1546 R1547: library part gen_R_130R_2010, "SMD Resistor 130R 2010", Case EIA=2010, Case Metric=5025, Maximum Working Voltage=400V, Operating Temperature="-55°C - +155°C", PnP Package=R_2010, Power=0.75W, Supplier Part Number 1=1892735, Tolerance=5%
R1512 R1513 R1514 R1515 R1516 R1517 R1530 R1531 R1532 R1533 R1534 R1535 R1548 R1549 R1550 R1551 R1552 R1553: library part gen_R_3k3_0603, "SMD Resistor 3k3 0603", Case EIA=0603, Case Metric=1608, Maximum Working Voltage=75V, Operating Temperature="-55°C - +155°C", PnP Package=R_0603, Power=0.1W, Supplier Part Number 1=2303173, Tolerance=1%
T1500 T1501 T1502 T1503 T1504 T1505 T1506 T1507 T1508 T1509 T1510 T1511 T1512 T1513 T1514 T1515 T1516 T1517: library part CMP-1259-00090-1, "P-Channel Trench MOSFET, -20 V, -2 A, -55 to 150 degC, 3-Pin SOT23, Tape and Reel", Manufacturer="NXP Semiconductors"
TP900 TP901 TP902 TP903 TP1400_1 TP1400_2 TP1401_1 TP1401_2 TP1402_1 TP1402_2 TP1403_1 TP1403_2 TP1404_1 TP1404_2 TP1405_1 TP1405_2 TP1406_1 TP1406_2 TP1407_1 TP1407_2 TP1408_1 TP1408_2 TP1409_1 TP1409_2: "Testpoint, square"
TR900: "MID-FLYLT Flyback Transformers for Linear Technology", Manufacturer="Würth Elektronik", Supplier Part Number 1=1297-1136-1-ND
TR1400_1 TR1400_2: "Pulse HM2102NL BMS Transformer", Manufacturer=Pulse, Operating Temperature="-40°C - +125°C", Supplier Part Number 1=673-HM2102NL
U100_1 U100_2 U101_1 U101_2: library part CMP-0384-01512-2, "Single Channel RRIO Operational Amplifier, 2.5 MHz BW, 1 V/us SR, Industrial, 5-pin SOT23 (RJ-5), Reel", Amplifiers Per Package=1, Generic Part Number=AD8628, Input Bias Current=30pA, Input Offset Voltage=1uV, Manufacturer="Analog Devices"
U600_1 U600_2: "Automotive DC/DC buck converter", Manufacturer="Texas Instruments", Operating Temperature="-40°C - +125°C", PnP Package=HTSSOP-14, Supplier Part Number 1=296-47791-1-ND
U700_1 U700_2: library part CMP-0314-00338-2, "Low-Voltage 8-Bit I2C and SMBus I/O Expander, 1.65 to 5.5 V, -40 to 85 degC, 16-pin TSSOP (PW), Green (RoHS & no Sb/Br)", 5V Tolerant I/O=Yes, Manufacturer="Texas Instruments", Max Frequency(kHz)=400
U1100 U1101 U1102 U1103 U1104 U1105 U1106 U1107 U1108 U1109 U1110 U1111 U1112 U1113 U1114 U1115 U1116 U1117: library part ACPL-217-56BE, "Optocoupler, Transistor Output, 1 Channel", Manufacturer="Broadcom Limited", Operating Temperature="-55°C - +110°C", Supplier Part Number 1=1602623
X200: "Micro-Fit 3.0 Right Angle Header, 3.00mm Pitch, Dual Row, 24 Circuits, with Snap-in Plastic Peg PCB Lock, Tin, Glow Wire Capable, Black, 43045-2400", Manufacturer=Molex, Operating Temperature="-40°C - +105°C", Part Name=MicroFit, Rated Current=8.5A, Rated Voltage=600V, Supplier Part Number 1=1012245
X201 X202: "Micro-Fit 3.0 Right Angle Header, 3.00mm Pitch, Dual Row, 16 Circuits, with Snap-in Plastic Peg PCB Lock, Tin, Glow Wire Capable, Black, 43045-1600", Manufacturer=Molex, Operating Temperature="-40°C - +105°C", Part Name=MicroFit, Rated Current=8.5A, Rated Voltage=600V, Supplier Part Number 1=9961380
X400 X401: "Standard Pinheader, THD, gerade, 2.54mm, 2-reihig", Operating Temperature="-40 °C - +105 °C", Part Name=PinHeader, Rated Current=3A, Rated Voltage=250V, Supplier Part Number 1=2025256
X402 X403: "Standard Pinheader, THD, gerade, 2.54mm, 2-reihig", Operating Temperature="-40 °C - +105 °C", Part Name=PinHeader, Rated Current=3A, Rated Voltage=250V, Supplier Part Number 1=2578720
X404: "Standard Pinheader, THD, gerade, 2.54mm, 2-reihig", Operating Temperature="-40 °C - +105 °C", Part Name=PinHeader, Rated Current=3A, Rated Voltage=250V, Supplier Part Number 1=2779676
X405: "Standard Pinheader, THD, gerade, 2.54mm, 2-reihig", Operating Temperature="-40 °C - +105 °C", Part Name=PinHeader, Rated Current=3A, Rated Voltage=250V, Supplier Part Number 1=2856692
X500 X501 X502 X503 X1001 X1002: "Micro-Fit 3.0 Right Angle Header, 3.00mm Pitch, Dual Row, 2 Circuits, with Snap-in Plastic Peg PCB Lock, Tin, Glow Wire Capable, Black, 43045-0200", Manufacturer=Molex, Operating Temperature="-40°C - +105°C", Part Name=MicroFit, Rated Current=8.5A, Rated Voltage=600V, Supplier Part Number 1=1012251
X900: "Standard Pinheader, THD, gerade, 2.54mm", Operating Temperature="-40 °C - +105 °C", Part Name=PinHeader, Rated Current=3A, Rated Voltage=250V, Supplier Part Number 1=2025248
X1000: "Board-To-Board Connector, Vertical, 2.54 mm, 4 Contacts, Header, TSW Series, Through Hole, 2 Rows", Manufacturer=Samtec, Operating Temperature="-55°C - +125°C", Part Name=TSW-102-07-G-D, Rated Voltage="500V AC mated with SSW", Supplier Part Number 1=2025248
Z1300_1 Z1300_2 Z1301_1 Z1301_2 Z1302_1 Z1302_2 Z1303_1 Z1303_2 Z1304_1 Z1304_2 Z1305_1 Z1305_2 Z1306_1 Z1306_2 Z1307_1 Z1307_2 Z1308_1 Z1308_2 Z1309_1 Z1309_2 Z1310_1 Z1310_2 Z1311_1 Z1311_2 Z1312_1 Z1312_2 Z1313_1 Z1313_2 Z1314_1 Z1314_2 Z1315_1 Z1315_2 Z1316_1 Z1316_2 Z1317_1 Z1317_2: library part CMP-1060-00434-1, "Zener Voltage Regulator, 500 mW, 2-Pin SOD-123, Pb-Free, Tape and Reel", Manufacturer="On Semiconductor"

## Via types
v1: diameter 0.55, hole 0.3, Top to Bottom, tented both sides, 2991 vias
v2: diameter 0.75, hole 0.5, Top to Bottom, tented both sides, 22 vias
v3: diameter 0.65, hole 0.4, Top to Bottom, tented both sides, 16 vias

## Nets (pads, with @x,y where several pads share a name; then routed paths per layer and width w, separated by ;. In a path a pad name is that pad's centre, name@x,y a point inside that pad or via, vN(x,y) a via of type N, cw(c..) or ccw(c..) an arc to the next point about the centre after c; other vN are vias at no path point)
+3.0V_VREF1_1: C1403_1.2 IC1400_1.51 TP1401_1.1 | length 14.6
  Top w0.152: v1(143.51,56.515) 144.369,57.373 147.417,57.373 148.128,58.085 148.128,58.455 TP1401_1.1@148.887,59.214
  Top w0.254: C1403_1.2@138.493,58.03 138.493,57.478 138.958,57.014 v1(138.958,56.94) IC1400_1.51@138.958,55.598
  Signals2 w0.152: v1(138.958,56.94) 138.958,56.515 139.343,56.129 143.124,56.129 v1(143.51,56.515)
+3.0V_VREF1_2: C1403_2.2 IC1400_2.51 TP1401_2.1 | length 16.5
  Top w0.152: v1(90.805,56.134) 90.805,56.832 91.123,57.15 93.98,57.15 94.774,57.944 94.774,59.055 94.932,59.214 TP1401_2.1@95.567,59.214
  Top w0.254: C1403_2.2@85.407,58.03 v1(85.407,57.083) 85.407,56.84 85.618,56.63 IC1400_2.51@85.618,55.547
  Bottom w0.152: v1(85.407,57.083) 86.528,57.083 87.083,56.529 87.879,56.529 88.988,57.638 89.447,57.638 89.87,57.215 89.87,57.069 v1(90.805,56.134)
+3.0V_VREF2_0: C100_1.2 C401.2 C405.2 C1402_1.2 IC1400_1.50 R100_1.2 R101_1.2 R102_1.2 R103_1.2 R104_1.2 R105_1.2 R106_1.2 R107_1.2 TP1402_1.1 X400.17 X404.1 | length 241.1
  Top w0.152: C100_1.2@109.596,10.567 C100_1.2@109.696,10.567 ; v1(140.272,57.13) 140.823,57.13 141.227,57.534 141.227,58.55 141.732,59.055 142.643,59.055 143.192,59.604 143.192,60.518 144.905,62.23 147.32,62.23 TP1402_1.1@148.907,60.642
  Top w0.254: C401.2@5.802,39.052 5.397,39.052 5.08,39.37 5.08,42.545 X400.17@6.35,43.815 ; C401.2@5.943,39.052 5.943,38.476 6.331,38.088 22.522,38.088 23.792,39.358 28.872,39.358 29.19,39.04 29.19,37.453 29.192,37.306 ; C405.2@31.432,37.237 29.261,37.237 29.192,37.306 ; v1(32.127,33.337) 32.136,33.347 32.136,34.448 32.329,34.641 32.329,36.169 32.107,36.391 29.21,36.391 X404.1@29.21,36.195 29.192,37.306 ; R100_1.2@85.553,12.061 85.553,11.509 85.64,11.422 v1(85.64,11.113) ; v1(88.497,11.113) 88.553,11.169 R101_1.2@88.553,12.061 ; v1(91.355,11.113) 91.355,11.311 91.553,11.509 R102_1.2@91.553,12.061 ; v1(94.212,11.113) 94.553,11.454 R103_1.2@94.553,12.061 ; v1(97.387,11.113) 97.387,11.343 97.553,11.509 R104_1.2@97.553,12.061 ; R105_1.2@100.553,12.061 100.553,11.123 v1(100.562,11.113) ; v1(103.42,11.113) 103.42,11.376 103.553,11.509 R106_1.2@103.553,12.061 ; v1(106.277,11.113) 106.553,11.389 R107_1.2@106.553,12.061 ; v1(108.744,11.112) 109.051,11.112 C100_1.2@109.596,10.567 ; C100_1.2@109.696,10.567 v1(109.696,11.589) ; v1(139.457,53.265) 139.457,56.316 v1(140.272,57.13) 140.272,57.936 C1402_1.2@140.017,58.19
  Signals2 w0.254: v1(109.696,11.589) 109.696,18.574 134.144,43.021 137.477,43.021 139.7,45.244 139.7,53.023 v1(139.457,53.265)
  Bottom w0.254: v1(32.127,33.337) 32.127,29.468 34.925,26.67 50.369,26.67 52.896,24.143 79.105,24.143 79.435,23.812 79.435,21.531 79.693,21.272 79.9,21.272 92.234,21.273 94.139,21.273 95.696,19.715 95.696,18.541 97.172,17.066 105.075,17.066 109.696,12.445 v1(109.696,11.589) ; v1(85.64,11.113) v1(88.497,11.113) v1(91.355,11.113) v1(94.212,11.113) v1(97.387,11.113) v1(100.562,11.113) v1(103.42,11.113) v1(106.277,11.113) v1@108.902,11.113 ; v1(108.744,11.112) v1@108.901,11.112
+3.0V_VREF2_1: C100_2.2 C400.2 C406.2 C1402_2.2 IC1400_2.50 R100_2.2 R101_2.2 R102_2.2 R103_2.2 R104_2.2 R105_2.2 R106_2.2 R107_2.2 TP1402_2.1 X401.17 X404.2 | length 209
  Top w0.152: C100_2.2@80.863,10.567 C100_2.2@80.962,10.567 ; v1(90.424,57.404) 93.769,57.404 94.52,58.154 94.52,59.595 TP1402_2.1@95.567,60.642
  Top w0.254: X401.17@6.35,51.435 5.377,51.423 5.06,51.105 5.06,46.978 5.365,46.672 C400.2@5.943,46.672 5.943,46.096 6.319,45.72 6.667,45.72 27.92,45.708 28.237,45.39 28.237,40.31 28.555,39.993 29.507,39.993 29.825,39.675 29.825,38.723 30.142,38.405 32.365,38.405 32.793,37.977 32.803,33.553 32.803,33.158 32.258,32.613 C406.2@31.432,32.613 ; X404.2@29.21,33.655 29.19,32.777 29.355,32.613 C406.2@31.432,32.613 ; v1(31.432,29.527) C406.2@31.432,32.613 ; R100_2.2@56.931,12.035 56.931,11.483 57.302,11.112 v1(57.309,11.112) ; R101_2.2@59.931,12.035 59.931,11.347 v1(60.166,11.112) ; R102_2.2@62.931,12.035 62.931,11.364 v1(63.182,11.112) ; R103_2.2@65.932,12.035 65.932,11.221 v1(66.04,11.112) ; R104_2.2@68.932,12.035 68.932,11.237 v1(69.056,11.112) ; R105_2.2@71.932,12.035 71.932,11.253 v1(72.072,11.112) ; R106_2.2@74.932,12.035 74.932,11.27 v1(75.089,11.112) ; R107_2.2@77.932,12.035 77.932,11.286 v1(78.105,11.112) ; v1(80.01,11.112) 80.318,11.112 C100_2.2@80.863,10.567 ; C100_2.2@80.962,10.567 v1(80.962,11.589) ; v1(85.725,53.975) 86.118,54.368 IC1400_2.50@86.118,55.547 86.118,56.577 86.624,57.083 v1(87.312,57.083) C1402_2.2@87.312,58.03
  Signals2 w0.254: v1(80.962,11.589) 80.962,22.057 81.483,22.577 81.483,23.61 81.29,23.803 81.29,41.602 87.312,47.625 87.312,52.387 v1(85.725,53.975)
  Bottom w0.152: v1(87.312,57.083) 88.121,57.892 89.936,57.892 v1(90.424,57.404)
  Bottom w0.254: v1(31.432,29.527) 34.756,26.204 50.144,26.204 52.694,23.654 75.089,23.654 80.962,17.78 v1(80.962,11.589) ; v1(57.309,11.112) v1(60.166,11.112) v1(63.182,11.112) v1(66.04,11.112) v1(69.056,11.112) v1(72.072,11.112) v1(75.089,11.112) v1(78.105,11.112) v1(80.01,11.112)
+5.0V_VREG_0: C101_1.2 C102_1.2 C103_1.2 C104_1.2 C105_1.2 C402.2 C404.2 C604_1.2 C700_1.2 C701_1.2 C800_1.2 C801_1.2 C1401_1.2 D1100.2 IC100_1.2 IC100_1.13 IC101_1.2 IC101_1.13 IC101_1.15 IC104_1.2 IC104_1.13 IC104_1.16 IC800_1.1 IC801_1.8 IC1400_1.48 IC1400_1.55 L600_1.2 LD1400_1.2 R602_1.1 R604_1.1 R700_1.2 R701_1.2 R702_1.2 R703_1.2 R704_1.2 R705_1.2 R706_1.2 R707_1.2 R708_1.1 R800_1.2 R801_1.2 R1404_1.2 R1407_1.2 R1419_1.2 R1420_1.2 R1421_1.2 R1422_1.2 R1423_1.2 R1424_1.2 R1425_1.2 R1426_1.2 R1427_1.2 TP1403_1.1 U100_1.5 U101_1.5 U700_1.1 U700_1.16 X402.9 X404.3 | length 145.6
  Top w0.152: IC101_1.2@11.786,63.462 12.861,63.462 13.018,63.305 v1(13.018,62.23) ; IC104_1.16@16.125,62.813 17.344,62.813 v1(17.621,63.09) ; IC104_1.2@21.946,63.462 23.139,63.462 v1(23.177,63.5) ; v1(26.67,60.567) C104_1.2@27.675,60.567 29.452,60.567 30.797,61.912 30.797,63.817 30.162,64.453 29.21,64.453 28.89,64.133 U101_1.5@27.87,64.133 ; v1(80.877,23.032) R707_1.2@80.877,23.561 R707_1.2@80.877,23.611 ; U700_1.16@81.605,15.188 81.605,14.607 82.143,14.07 C700_1.2@82.143,13.97 v1@82.143,12.79 ; v1(82.465,23.032) R706_1.2@82.465,23.561 R706_1.2@82.465,23.611 ; R705_1.2@84.052,23.561 84.052,23.052 v1(84.072,23.032) ; R705_1.2@84.052,23.611 84.072,23.591 R705_1.2@84.072,23.561 ; R704_1.2@85.64,23.561 85.64,23.052 v1(85.66,23.032) ; R704_1.2@85.64,23.611 85.66,23.591 R704_1.2@85.66,23.561 ; R703_1.2@87.227,23.561 87.227,23.052 v1(87.247,23.032) ; R703_1.2@87.227,23.611 87.247,23.591 R703_1.2@87.247,23.561 ; U700_1.1@87.305,15.188 86.905,15.188 86.45,14.733 C701_1.2@86.45,13.97 v1(87.63,13.97) ; R702_1.2@88.815,23.561 88.815,23.052 v1(88.835,23.032) ; R702_1.2@88.815,23.611 88.835,23.591 R702_1.2@88.835,23.561 ; v1(88.9,13.97) R708_1.1@88.9,14.857 ; R701_1.2@90.402,23.561 90.402,23.052 v1(90.422,23.032) ; R701_1.2@90.402,23.611 90.422,23.591 R701_1.2@90.422,23.561 ; R700_1.2@91.99,23.561 91.99,23.052 v1(92.01,23.032) ; R700_1.2@91.99,23.611 92.01,23.591 R700_1.2@92.01,23.561 ; IC100_1.13@94.389,21.9 96.185,21.9 96.996,22.711 96.996,24.289 96.289,24.996 C101_1.2@96.289,26.352 96.289,26.628 94.595,28.321 v1(94.595,28.575) ; IC100_1.2@100.239,20.6 101.563,20.6 v1(101.759,20.796) 101.759,20.637 v1@101.721,20.6 ; v1(101.6,51.117) 101.6,51.01 101.577,50.988 101.982,50.582 R800_1.2@101.982,50.482 ; U100_1.5@105.249,20.231 105.816,20.231 106.276,19.771 C103_1.2@107.474,19.771 v1(107.474,18.732) ; R1407_1.2@132.08,62.136 132.18,62.136 132.551,62.507 132.992,62.507 v1(133.032,62.547) ; R1404_1.2@136.93,59.537 v1(136.93,60.452) ; LD1400_1.2@139.18,63.817 TP1403_1.1@140.97,63.817 v1(144.78,63.817) ; v1(147.3,53.848) 147.37,53.848 147.721,54.199 R1419_1.2@148.273,54.199 ; v1(149.352,48.006) 150.348,48.006 151.429,46.925 151.728,46.925 152.082,46.57 IC801_1.8@152.082,45.719 152.082,44.867 152.172,44.777 C800_1.2@152.172,43.974 ; v1(149.606,43.18) 150.243,43.18 151.64,41.783 152.628,41.783 153.259,42.413 R801_1.2@153.259,42.513 ; v1(150.336,55.178) R1420_1.2@150.336,54.199 R1424_1.2@151.732,54.199 R1423_1.2@151.732,52.665 152.183,52.665 152.604,52.244 152.903,51.944 R1422_1.2@154.686,51.944 154.686,51.493 155.314,50.866 155.314,50.158 154.686,49.53 R1421_1.2@154.686,48.579
  Top w0.203: IC800_1.1@102.55,48.825 102.55,48.7 103.398,47.853 C801_1.2@104.457,47.853 v1(105.41,47.853) ; v1(136.958,53.95) IC1400_1.55@136.958,55.547
  Top w0.254: IC101_1.15@5.965,63.463 5.215,63.463 4.763,63.915 4.763,64.31 5.215,64.763 IC101_1.13@5.965,64.763 7.235,64.763 7.68,64.317 C102_1.2@7.68,61.552 7.68,61.277 7.211,60.807 7.086,60.807 v1(6.921,60.642) ; v1(14.224,66.802) C105_1.2@14.224,65.743 14.224,65.024 14.485,64.763 IC104_1.13@16.125,64.763 ; C404.2@26.442,38.417 26.442,36.423 X404.3@26.67,36.195 ; C402.2@29.507,43.258 30.233,43.258 30.373,43.397 30.777,43.803 X402.9@31.75,43.815 ; D1100.2@101.577,53.598 v1(101.577,54.587) ; v1(141.351,56.683) 141.351,56.556 141.908,56 ; IC1400_1.48@141.908,53.597 141.908,56 ; C1401_1.2@142.13,58.03 142.13,56.222 141.908,56
  Top w0.406: R1427_1.2@12.954,31.561 R1426_1.2@14.351,31.561 R1425_1.2@15.748,31.561 v1(16.748,31.561) v1@16.764,31.561
  SUPPLY w0.406: v1(16.748,31.561) 7.344,31.561 6.663,30.88 5.95,30.88 4.826,32.004 4.826,36.703 5.715,37.592 25.273,37.592 X404.3@26.67,36.195
  other v1: 82.233,12.7 127,53.086 126.619,53.848 127.381,53.848 127,54.61 126.619,55.372 127.381,55.372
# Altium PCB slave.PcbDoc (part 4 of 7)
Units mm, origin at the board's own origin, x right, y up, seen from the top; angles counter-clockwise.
Board outline 160 x 100 mm, 6 copper layers (Top, FUSED_VBAT-, Signals1, Signals2, SUPPLY, Bottom), stack 1.67 mm thick; 597 components, 381 nets, 1695 pads, 3029 vias.

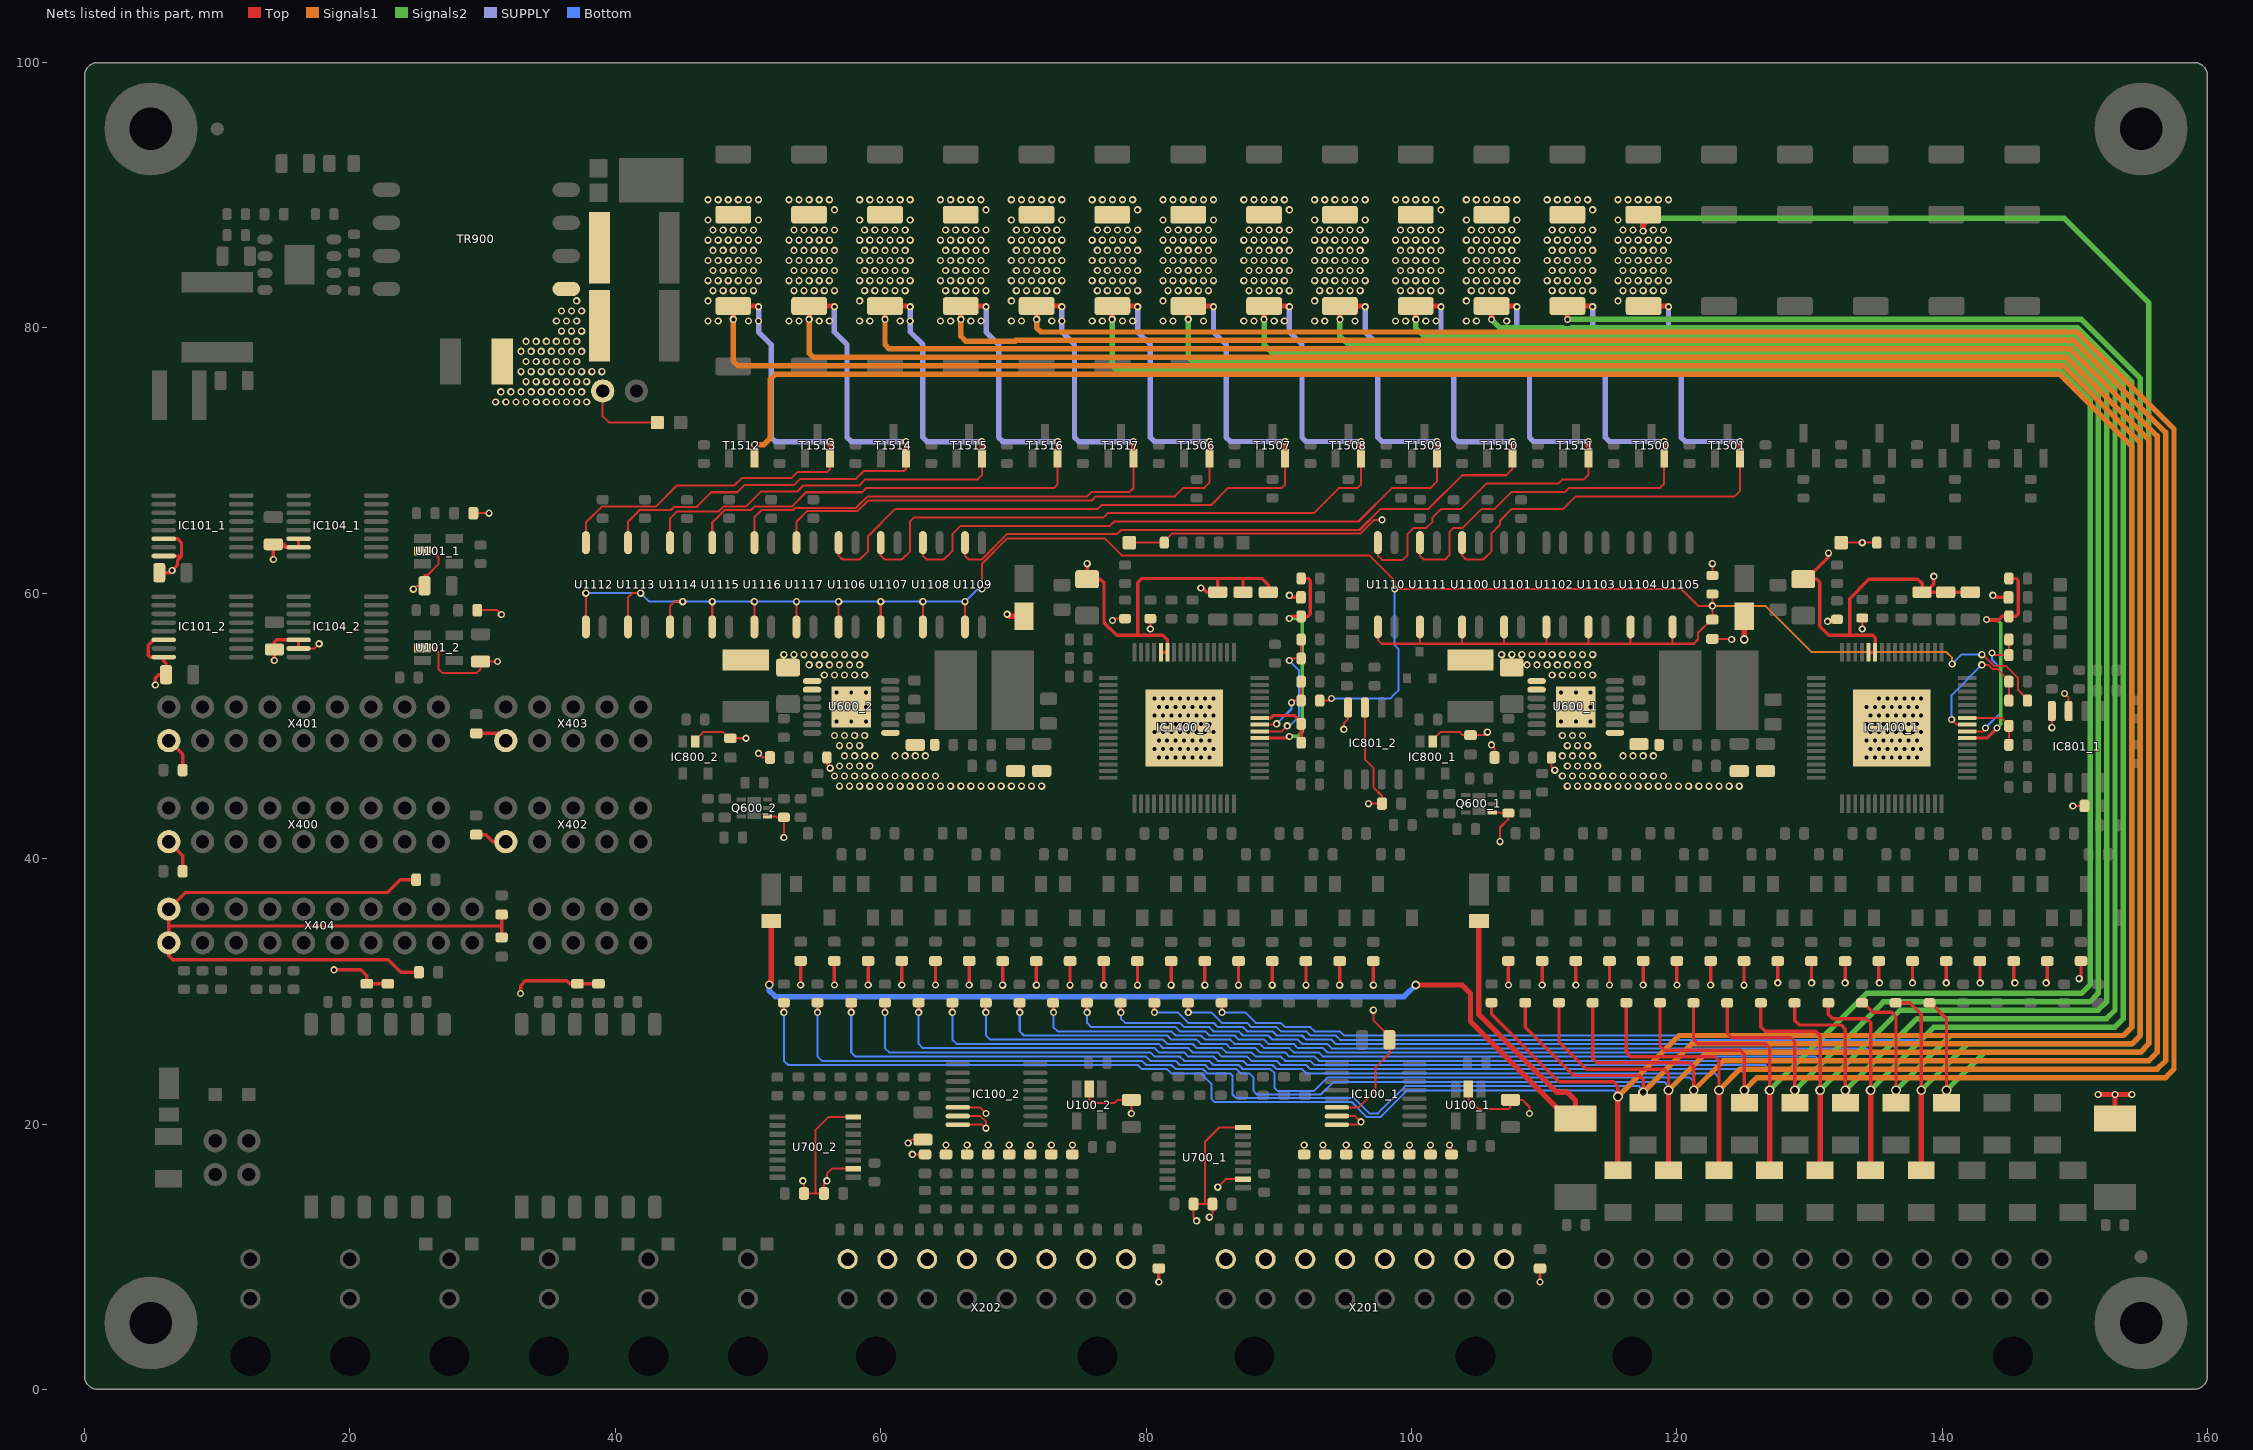
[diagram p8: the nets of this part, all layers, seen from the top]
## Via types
v1: diameter 0.55, hole 0.3, Top to Bottom, tented both sides, 2991 vias
v2: diameter 0.75, hole 0.5, Top to Bottom, tented both sides, 22 vias
v3: diameter 0.65, hole 0.4, Top to Bottom, tented both sides, 16 vias

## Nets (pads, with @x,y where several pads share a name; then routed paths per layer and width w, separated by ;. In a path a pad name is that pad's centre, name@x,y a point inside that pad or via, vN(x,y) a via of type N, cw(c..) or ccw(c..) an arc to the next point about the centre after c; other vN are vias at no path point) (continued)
FUSED_CELL.CELL_4+: F314.2 R1301_1.1 R1301_2.1 R1500.1 R1506.1 T1501.2 U1100.2 | length 228.9
  Top w0.152: U1100.2@103.822,63.817 103.822,62.841 104.116,62.547 105.41,62.547 106.045,63.182 106.045,64.535 106.68,65.17 106.68,65.458 107.58,66.358 111.442,66.358 112.395,67.31 124.362,67.31 124.775,67.723 T1501.2@124.775,70.17
  Top w0.254: R1301_2.1@85.705,29.133 85.705,28.436 v1(85.725,28.416) ; R1301_1.1@139.045,29.133 139.145,29.133 140.335,27.942 v2(140.335,22.543)
  Top w0.406: v1(117.475,87.313) R1506.1@117.475,88.53 ; R1500.1@117.505,81.65 119.327,81.65 v1(119.38,81.597) ; T1501.2@124.775,70.17 124.775,71.435 v1(124.777,71.438) ; F314.2@140.335,21.593 v2(140.335,22.543)
  Signals2 w0.406: v1(117.475,87.313) 117.475,87.789 117.951,88.265 149.225,88.265 155.575,81.915 155.575,81.597 155.575,69.85 155.575,26.035 154.94,25.4 143.192,25.4 v2(140.335,22.543)
  SUPPLY w0.406: v1(119.38,81.597) 119.38,79.692 120.332,78.74 120.332,71.755 120.65,71.438 v1(124.777,71.438)
  Bottom w0.152: v1(85.725,28.416) 87.471,28.416 88.265,27.622 90.17,27.622 90.487,27.305 92.392,27.305 92.71,26.987 94.615,26.987 94.945,26.658 140.017,26.658 140.335,26.34 v2(140.335,22.543)
  other v1: 115.57,82.042 115.951,82.804 116.713,82.804 117.475,82.804 118.237,82.804 118.999,82.804 115.57,83.566 116.332,83.566 117.094,83.566 117.856,83.566 118.618,83.566 119.38,83.566 115.951,84.328 116.713,84.328 117.475,84.328 118.237,84.328 118.999,84.328 115.57,85.09 116.332,85.09 117.094,85.09 117.856,85.09 118.618,85.09 119.38,85.09 115.951,85.852 116.713,85.852 117.475,85.852 118.237,85.852 118.999,85.852 115.57,86.614 116.332,86.614 117.094,86.614 117.856,86.614 118.618,86.614 119.38,86.614 115.951,87.376 116.713,87.376 118.237,87.376 118.999,87.376 115.57,88.138 115.57,89.662 116.332,89.662 117.094,89.662 117.856,89.662 118.618,89.662 119.38,89.662
FUSED_CELL.CELL_5+: F313.2 R1300_1.1 R1300_2.1 R1523.1 R1529.1 T1500.2 U1111.2 | length 231.1
  Top w0.152: U1111.2@100.647,63.817 100.647,62.841 100.941,62.547 102.552,62.547 102.87,62.865 102.87,64.609 103.188,64.927 103.859,64.927 105.29,66.358 106.28,66.358 107.567,67.645 111.615,67.645 111.915,67.945 118.742,67.945 119.06,68.263 T1500.2@119.06,70.17
  Top w0.254: R1300_2.1@83.165,29.133 83.165,28.436 v1(83.185,28.416) ; R1300_1.1@136.505,29.133 137.555,29.133 138.43,28.258 v2(138.43,22.543)
  Top w0.406: v1(111.763,80.64) 111.76,80.643 R1523.1@111.76,81.65 113.612,81.65 v1(113.665,81.597) ; T1500.2@119.06,70.17 v1(119.06,71.438) ; F313.2@138.43,16.513 v2(138.43,22.543)
  Signals2 w0.406: v1(111.763,80.64) 150.5,80.64 154.94,76.2 154.94,69.85 154.94,26.67 154.305,26.035 141.922,26.035 v2(138.43,22.543)
  SUPPLY w0.406: v1(113.665,81.597) 113.665,79.692 114.617,78.74 114.617,71.755 114.935,71.438 v1(119.06,71.438)
  Bottom w0.152: v1(83.185,28.416) 84.931,28.416 85.725,27.622 87.63,27.622 87.947,27.305 89.852,27.305 90.17,26.987 92.075,26.987 92.392,26.67 94.297,26.67 94.627,26.34 138.112,26.34 138.43,26.023 v2(138.43,22.543)
  other v1: 110.617,82.804 111.379,82.804 112.141,82.804 112.903,82.804 113.665,82.804 110.236,83.566 110.998,83.566 111.76,83.566 112.522,83.566 113.284,83.566 110.617,84.328 111.379,84.328 112.141,84.328 112.903,84.328 113.665,84.328 110.236,85.09 110.998,85.09 111.76,85.09 112.522,85.09 113.284,85.09 110.617,85.852 111.379,85.852 112.141,85.852 112.903,85.852 113.665,85.852 110.236,86.614 110.998,86.614 111.76,86.614 112.522,86.614 113.284,86.614 110.617,87.376 111.379,87.376 112.141,87.376 112.903,87.376 113.665,87.376 113.665,88.9 110.236,89.662 110.998,89.662 111.76,89.662 112.522,89.662 113.284,89.662
FUSED_CELL.CELL_6+: F312.2 R1312_1.1 R1312_2.1 R1522.1 R1528.1 T1511.2 U1110.2 | length 230.1
  Top w0.152: U1110.2@97.472,63.817 97.472,62.841 97.798,62.515 99.345,62.515 99.695,62.865 99.695,64.453 100.169,64.927 101.134,64.927 101.6,65.393 101.6,65.722 102.223,66.345 103.736,66.345 105.653,68.263 111.057,68.263 111.363,68.568 112.998,68.568 113.345,68.914 T1511.2@113.345,70.17
  Top w0.254: R1312_2.1@80.625,29.133 80.625,28.436 v1(80.645,28.416) ; R1312_1.1@133.965,29.082 R1312_1.1@133.985,29.062 ; R1312_1.1@133.965,29.133 134.065,29.133 134.781,28.416 136.207,28.416 136.525,28.099 v2(136.525,22.543)
  Top w0.406: v1(106.045,80.64) R1522.1@106.045,81.65 107.897,81.65 v1(107.95,81.597) ; T1511.2@113.345,70.17 113.345,71.435 v1(113.347,71.438) ; F312.2@136.525,21.593 v2(136.525,22.543)
  Signals2 w0.406: v1(106.045,80.64) 106.675,80.01 111.429,80.01 111.481,79.959 112.045,79.959 112.097,80.01 150.239,80.01 154.305,75.944 154.305,70.802 154.305,70.168 154.305,27.305 153.67,26.67 140.653,26.67 v2(136.525,22.543)
  SUPPLY w0.406: v1(107.95,81.597) 107.95,79.692 108.902,78.74 108.902,71.755 109.22,71.438 v1(113.347,71.438)
  Bottom w0.152: v1(80.645,28.416) 82.391,28.416 83.185,27.622 85.09,27.622 85.407,27.305 87.312,27.305 87.63,26.987 89.535,26.987 89.852,26.67 91.757,26.67 92.075,26.352 93.98,26.352 94.31,26.023 136.207,26.023 136.525,25.705 v2(136.525,22.543)
  other v1: 104.14,80.518 104.902,80.518 107.188,80.518 104.14,82.042 104.521,82.804 105.283,82.804 106.045,82.804 106.807,82.804 107.569,82.804 104.14,83.566 104.902,83.566 105.664,83.566 106.426,83.566 107.188,83.566 107.95,83.566 104.521,84.328 105.283,84.328 106.045,84.328 106.807,84.328 107.569,84.328 104.14,85.09 104.902,85.09 105.664,85.09 106.426,85.09 107.188,85.09 107.95,85.09 104.521,85.852 105.283,85.852 106.045,85.852 106.807,85.852 107.569,85.852 104.14,86.614 104.902,86.614 105.664,86.614 106.426,86.614 107.188,86.614 107.95,86.614 104.521,87.376 105.283,87.376 106.045,87.376 106.807,87.376 107.569,87.376 104.14,88.138 107.95,88.138 104.14,89.662 104.902,89.662 105.664,89.662 106.426,89.662 107.188,89.662 107.95,89.662
FUSED_CELL.CELL_7+: F311.2 R1311_1.1 R1311_2.1 R1521.1 R1527.1 T1510.2 U1109.2 | length 266.8
  Top w0.152: U1109.2@66.358,63.817 66.358,62.841 66.651,62.547 67.608,62.547 69.513,64.453 77.805,64.453 78.123,64.77 96.092,64.77 97.68,66.358 101.295,66.358 103.835,68.897 107.139,68.897 107.61,69.368 T1510.2@107.61,70.17
  Top w0.254: R1311_2.1@78.085,29.133 78.085,28.436 v1(78.105,28.416) ; R1311_1.1@131.425,29.133 131.425,28.278 131.762,27.94 134.302,27.94 134.62,27.622 v2(134.62,22.543)
  Top w0.406: v1(100.335,80.645) 100.33,80.65 R1521.1@100.33,81.65 102.182,81.65 v1(102.235,81.597) ; T1510.2@107.61,70.17 v1(107.61,71.415) ; F311.2@134.62,16.513 v2(134.62,22.543)
  Signals2 w0.406: v1(100.335,80.645) 100.33,80.64 100.33,80.01 100.965,79.375 101.6,79.375 149.976,79.375 153.67,75.681 153.67,70.802 153.67,70.168 153.67,27.94 153.035,27.305 139.382,27.305 v2(134.62,22.543)
  SUPPLY w0.406: v1(102.235,81.597) 102.235,79.692 103.188,78.74 103.188,71.755 103.528,71.415 v1(107.61,71.415)
  Bottom w0.152: v1(78.105,28.416) 78.105,27.94 78.422,27.622 82.55,27.622 82.867,27.305 84.772,27.305 85.09,26.987 86.995,26.987 87.312,26.67 89.218,26.67 89.535,26.352 91.44,26.352 91.757,26.035 93.662,26.035 93.992,25.705 134.302,25.705 134.62,25.388 v2(134.62,22.543)
  other v1: 98.806,80.518 99.568,80.518 101.092,80.518 101.854,80.518 99.187,82.804 99.949,82.804 100.711,82.804 101.473,82.804 102.235,82.804 98.806,83.566 99.568,83.566 100.33,83.566 101.092,83.566 101.854,83.566 99.187,84.328 99.949,84.328 100.711,84.328 101.473,84.328 102.235,84.328 98.806,85.09 99.568,85.09 100.33,85.09 101.092,85.09 101.854,85.09 99.187,85.852 99.949,85.852 100.711,85.852 101.473,85.852 102.235,85.852 98.806,86.614 99.568,86.614 100.33,86.614 101.092,86.614 101.854,86.614 99.187,87.376 99.949,87.376 100.711,87.376 101.473,87.376 102.235,87.376 102.235,88.9 98.806,89.662 99.568,89.662 100.33,89.662 101.092,89.662 101.854,89.662
FUSED_CELL.CELL_8+: F310.2 R1310_1.1 R1310_2.1 R1520.1 R1526.1 T1509.2 U1108.2 | length 268
  Top w0.152: U1108.2@63.182,63.817 63.182,62.841 63.476,62.547 64.77,62.547 65.405,63.182 65.405,64.453 66.04,65.087 77.282,65.087 77.607,65.413 96.016,65.413 98.549,67.945 101.465,67.945 101.93,68.41 T1509.2@101.93,70.17
  Top w0.254: R1310_2.1@75.545,29.133 75.545,28.436 v1(75.565,28.416) ; R1310_1.1@128.885,29.133 128.885,27.801 129.222,27.464 132.398,27.464 132.715,27.146 v2(132.715,22.543)
  Top w0.406: v1(94.615,80.645) R1520.1@94.615,81.65 96.467,81.65 v1(96.52,81.597) ; v1(101.917,71.438) 101.93,71.438 T1509.2@101.93,70.17 ; F310.2@132.715,21.593 v2(132.715,22.543)
  Signals2 w0.406: v1(94.615,80.645) 94.615,79.375 94.932,79.058 95.25,78.74 149.713,78.74 153.035,75.418 153.035,70.168 153.035,28.575 152.4,27.94 138.112,27.94 v2(132.715,22.543)
  SUPPLY w0.406: v1(96.52,81.597) 96.52,79.692 97.472,78.74 97.472,71.755 97.79,71.438 v1(101.917,71.438)
  Bottom w0.152: v1(75.565,28.416) 75.565,27.622 75.882,27.305 82.233,27.305 82.55,26.987 84.455,26.987 84.772,26.67 86.677,26.67 86.995,26.352 88.9,26.352 89.218,26.035 91.123,26.035 91.44,25.717 93.345,25.717 93.675,25.388 132.398,25.388 132.715,25.07 v2(132.715,22.543)
  other v1: 92.71,80.518 93.472,80.518 95.758,80.518 92.71,82.042 93.091,82.804 93.853,82.804 94.615,82.804 95.377,82.804 96.139,82.804 92.71,83.566 93.472,83.566 94.234,83.566 94.996,83.566 95.758,83.566 96.52,83.566 93.091,84.328 93.853,84.328 94.615,84.328 95.377,84.328 96.139,84.328 92.71,85.09 93.472,85.09 94.234,85.09 94.996,85.09 95.758,85.09 96.52,85.09 93.091,85.852 93.853,85.852 94.615,85.852 95.377,85.852 96.139,85.852 92.71,86.614 93.472,86.614 94.234,86.614 94.996,86.614 95.758,86.614 96.52,86.614 93.091,87.376 93.853,87.376 94.615,87.376 95.377,87.376 96.139,87.376 92.71,88.138 96.52,88.138 92.71,89.662 93.472,89.662 94.234,89.662 94.996,89.662 95.758,89.662 96.52,89.662
FUSED_CELL.CELL_9+: F309.2 R1309_1.1 R1309_2.1 R1519.1 R1525.1 T1508.2 U1107.2 | length 278.7
  Top w0.152: U1107.2@60.008,63.817 60.008,62.841 60.301,62.547 61.595,62.547 62.23,63.182 62.23,65.418 62.535,65.722 76.8,65.722 77.117,66.04 92.645,66.04 94.55,67.945 95.95,67.945 96.2,68.195 T1508.2@96.2,70.17
  Top w0.254: R1309_2.1@73.005,29.133 73.005,28.436 v1(73.025,28.416) ; R1309_1.1@126.345,29.133 126.345,27.325 126.682,26.987 130.493,26.987 130.81,26.67 v2(130.81,22.543)
  Top w0.406: v1(88.9,80.645) R1519.1@88.9,81.65 90.752,81.65 v1(90.805,81.597) ; T1508.2@96.2,70.17 v1(96.2,71.438) ; F309.2@130.81,16.513 v2(130.81,22.543)
  Signals2 w0.406: v1(88.9,80.645) 88.9,78.74 89.535,78.105 90.487,78.105 149.45,78.105 152.4,75.155 152.4,70.168 152.4,29.21 151.765,28.575 136.843,28.575 v2(130.81,22.543)
  SUPPLY w0.406: v1(90.805,81.597) 90.805,79.692 91.757,78.74 91.757,71.755 92.075,71.438 v1(96.2,71.438)
  Bottom w0.152: v1(73.025,28.416) 73.025,27.305 73.343,26.987 81.915,26.987 82.233,26.67 84.138,26.67 84.455,26.352 86.36,26.352 86.677,26.035 88.582,26.035 88.9,25.717 90.805,25.717 91.123,25.4 93.027,25.4 93.357,25.07 130.493,25.07 130.81,24.753 v2(130.81,22.543)
  other v1: 87.376,80.518 88.138,80.518 89.662,80.518 90.424,80.518 87.757,82.804 88.519,82.804 89.281,82.804 90.043,82.804 90.805,82.804 87.376,83.566 88.138,83.566 88.9,83.566 89.662,83.566 90.424,83.566 87.757,84.328 88.519,84.328 89.281,84.328 90.043,84.328 90.805,84.328 87.376,85.09 88.138,85.09 88.9,85.09 89.662,85.09 90.424,85.09 87.757,85.852 88.519,85.852 89.281,85.852 90.043,85.852 90.805,85.852 87.376,86.614 88.138,86.614 88.9,86.614 89.662,86.614 90.424,86.614 87.757,87.376 88.519,87.376 89.281,87.376 90.043,87.376 90.805,87.376 90.805,88.9 87.376,89.662 88.138,89.662 88.9,89.662 89.662,89.662 90.424,89.662
FUSED_CELL.CELL_10+: F308.2 R1308_1.1 R1308_2.1 R1518.1 R1524.1 T1507.2 U1106.2 | length 278.4
  Top w0.152: U1106.2@56.832,63.817 56.832,62.841 57.126,62.547 58.42,62.547 59.055,63.182 59.055,64.318 61.095,66.358 76.355,66.358 76.65,66.652 84.912,66.652 86.205,67.945 90.235,67.945 90.485,68.195 T1507.2@90.485,70.17
  Top w0.254: R1308_2.1@70.465,29.133 70.465,28.436 v1(70.485,28.416) ; R1308_1.1@123.805,29.133 123.805,26.849 124.142,26.511 128.588,26.511 128.905,26.194 v2(128.905,22.543)
  Top w0.406: v1(83.185,80.645) R1518.1@83.185,81.65 85.037,81.65 v1(85.09,81.597) ; T1507.2@90.485,70.17 90.485,70.972 90.487,70.974 v1(90.487,71.438) ; F308.2@128.905,21.593 128.905,22.344 128.707,22.543 v2(128.905,22.543)
  Signals2 w0.406: v1(83.185,80.645) 83.185,77.787 83.502,77.47 149.187,77.47 151.765,74.892 151.765,70.237 151.765,29.845 151.13,29.21 135.572,29.21 v2(128.905,22.543)
  SUPPLY w0.406: v1(85.09,81.597) 85.09,79.692 86.042,78.74 86.042,71.755 86.36,71.438 v1(90.487,71.438)
  Bottom w0.152: v1(70.485,28.416) 70.485,26.987 70.802,26.67 81.597,26.67 81.915,26.352 83.82,26.352 84.138,26.035 86.042,26.035 86.36,25.717 88.265,25.717 88.582,25.4 90.487,25.4 90.805,25.082 92.71,25.082 93.04,24.753 128.588,24.753 128.905,24.435 v2(128.905,22.543)
  other v1: 81.28,80.518 82.042,80.518 84.328,80.518 81.28,82.042 81.661,82.804 82.423,82.804 83.185,82.804 83.947,82.804 84.709,82.804 81.28,83.566 82.042,83.566 82.804,83.566 83.566,83.566 84.328,83.566 85.09,83.566 81.661,84.328 82.423,84.328 83.185,84.328 83.947,84.328 84.709,84.328 81.28,85.09 82.042,85.09 82.804,85.09 83.566,85.09 84.328,85.09 85.09,85.09 81.661,85.852 82.423,85.852 83.185,85.852 83.947,85.852 84.709,85.852 81.28,86.614 82.042,86.614 82.804,86.614 83.566,86.614 84.328,86.614 85.09,86.614 81.661,87.376 82.423,87.376 83.185,87.376 83.947,87.376 84.709,87.376 81.28,88.138 85.09,88.138 81.28,89.662 82.042,89.662 82.804,89.662 83.566,89.662 84.328,89.662 85.09,89.662
FUSED_CELL.CELL_11+: F307.2 R1307_1.1 R1307_2.1 R1541.1 R1547.1 T1506.2 U1117.2 | length 286.9
  Top w0.152: U1117.2@53.657,63.817 53.657,65.405 54.438,66.185 58.248,66.185 59.055,66.992 75.9,66.992 76.218,67.31 82.168,67.31 82.803,67.945 84.39,67.945 84.77,68.325 T1506.2@84.77,70.17
  Top w0.254: v1@67.925,28.533 R1307_2.1@67.925,29.082 ; R1307_1.1@121.265,29.133 121.265,26.373 121.602,26.035 126.682,26.035 127,25.717 v2(127,22.543)
  Top w0.406: v1(77.45,80.645) 77.465,80.66 R1541.1@77.465,81.65 79.322,81.65 v1(79.375,81.597) ; T1506.2@84.77,70.17 84.77,71.435 v1(84.772,71.438) ; F307.2@127,16.258 F307.2@127,16.513 v2(127,22.543)
  Signals2 w0.406: v1(77.45,80.645) 77.45,77.173 77.787,76.835 148.924,76.835 151.176,74.582 151.176,70.168 151.176,30.526 150.495,29.845 134.302,29.845 v2(127,22.543)
  SUPPLY w0.406: v1(79.375,81.597) 79.375,79.692 80.328,78.74 80.328,71.755 80.645,71.438 v1(84.772,71.438)
  Bottom w0.152: v1@67.925,28.533 v1(67.925,28.416) 67.925,26.69 68.263,26.352 81.28,26.352 81.597,26.035 83.502,26.035 83.82,25.717 85.725,25.717 86.042,25.4 87.947,25.4 88.265,25.082 90.17,25.082 90.487,24.765 92.392,24.765 92.722,24.435 126.682,24.435 127,24.118 v2(127,22.543)
  other v1: 75.946,80.518 76.708,80.518 78.232,80.518 78.994,80.518 76.327,82.804 77.089,82.804 77.851,82.804 78.613,82.804 79.375,82.804 75.946,83.566 76.708,83.566 77.47,83.566 78.232,83.566 78.994,83.566 76.327,84.328 77.089,84.328 77.851,84.328 78.613,84.328 79.375,84.328 75.946,85.09 76.708,85.09 77.47,85.09 78.232,85.09 78.994,85.09 76.327,85.852 77.089,85.852 77.851,85.852 78.613,85.852 79.375,85.852 75.946,86.614 76.708,86.614 77.47,86.614 78.232,86.614 78.994,86.614 76.327,87.376 77.089,87.376 77.851,87.376 78.613,87.376 79.375,87.376 79.375,88.9 75.946,89.662 76.708,89.662 77.47,89.662 78.232,89.662 78.994,89.662
FUSED_CELL.CELL_12+: F306.2 R1318_1.1 R1318_2.1 R1540.1 R1546.1 T1517.2 U1116.2 | length 302.1
  Top w0.152: U1116.2@50.482,63.817 50.482,65.722 51.036,66.276 53.391,66.276 53.555,66.439 58.143,66.439 59.013,67.31 75.565,67.31 75.882,67.627 78.748,67.627 79.055,67.935 T1517.2@79.055,70.17
  Top w0.254: v1(65.405,28.416) R1318_2.1@65.405,29.145 ; R1318_1.1@118.745,29.21 R1318_1.1@118.745,29.145 118.745,25.876 119.062,25.559 124.777,25.559 125.095,25.241 v2(125.095,22.543)
  Top w0.406: v1(71.755,80.645) R1540.1@71.755,81.65 73.607,81.65 v1(73.66,81.597) ; T1517.2@79.055,70.17 v1(79.055,71.435) ; F306.2@125.095,21.338 F306.2@125.095,21.593 v2(125.095,22.543)
  Signals1 w0.406: v1(71.755,80.645) 71.755,80.01 72.073,79.692 150.177,79.692 157.48,72.39 157.48,69.215 157.48,24.13 156.845,23.495 126.047,23.495 v2(125.095,22.543)
  SUPPLY w0.406: v1(73.66,81.597) v1(73.66,80.518) 73.66,79.692 74.612,78.74 74.612,71.755 74.933,71.435 v1(79.055,71.435)
  Bottom w0.152: v1(65.405,28.416) 65.405,26.352 65.722,26.035 80.962,26.035 81.28,25.717 83.185,25.717 83.502,25.4 85.407,25.4 85.725,25.082 87.63,25.082 87.947,24.765 89.852,24.765 90.17,24.447 92.075,24.447 92.392,24.13 124.777,24.13 125.095,23.812 v2(125.095,22.543)
  other v1: 69.85,80.518 70.612,80.518 72.898,80.518 69.85,82.042 70.231,82.804 70.993,82.804 71.755,82.804 72.517,82.804 73.279,82.804 69.85,83.566 70.612,83.566 71.374,83.566 72.136,83.566 72.898,83.566 73.66,83.566 70.231,84.328 70.993,84.328 71.755,84.328 72.517,84.328 73.279,84.328 69.85,85.09 70.612,85.09 71.374,85.09 72.136,85.09 72.898,85.09 73.66,85.09 70.231,85.852 70.993,85.852 71.755,85.852 72.517,85.852 73.279,85.852 69.85,86.614 70.612,86.614 71.374,86.614 72.136,86.614 72.898,86.614 73.66,86.614 70.231,87.376 70.993,87.376 71.755,87.376 72.517,87.376 73.279,87.376 69.85,88.138 73.66,88.138 69.85,89.662 70.612,89.662 71.374,89.662 72.136,89.662 72.898,89.662 73.66,89.662
FUSED_CELL.CELL_13+: F305.2 R1317_1.1 R1317_2.1 R1539.1 R1545.1 T1516.2 U1115.2 | length 311.7
  Top w0.152: U1115.2@47.307,63.817 47.307,65.336 48.247,66.276 50.228,66.276 50.482,66.53 53.286,66.53 54.372,67.615 58.6,67.615 58.92,67.935 73.071,67.935 73.34,68.203 T1516.2@73.34,70.17
  Top w0.254: v1(62.865,28.416) R1317_2.1@62.865,29.145 ; R1317_1.1@116.205,29.095 116.205,25.4 116.522,25.082 122.872,25.082 123.19,24.765 v2(123.19,22.543)
  Top w0.406: v1(66.04,80.645) R1539.1@66.04,81.65 67.892,81.65 v1(67.945,81.597) ; T1516.2@73.34,70.17 v1(73.34,71.435) ; F305.2@123.19,16.258 F305.2@123.19,16.513 v2(123.19,22.543)
  Signals1 w0.406: v1(66.04,80.645) 66.04,79.375 66.404,79.011 70.132,79.011 70.179,79.057 149.914,79.057 156.845,72.127 156.845,69.215 156.845,24.765 156.21,24.13 124.777,24.13 v2(123.19,22.543)
  SUPPLY w0.406: v1(67.945,81.597) 67.945,79.692 68.897,78.74 68.897,71.755 69.218,71.435 v1(73.34,71.435)
  Bottom w0.152: v1(62.865,28.416) 62.865,26.035 63.182,25.717 80.645,25.717 80.962,25.4 82.867,25.4 83.185,25.082 85.09,25.082 85.407,24.765 87.312,24.765 87.63,24.447 89.535,24.447 89.852,24.13 91.757,24.13 92.075,23.812 122.872,23.812 123.19,23.495 v2(123.19,22.543)
  other v1: 64.516,80.518 65.278,80.518 66.802,80.518 67.564,80.518 64.897,82.804 65.659,82.804 66.421,82.804 67.183,82.804 67.945,82.804 64.516,83.566 65.278,83.566 66.04,83.566 66.802,83.566 67.564,83.566 64.897,84.328 65.659,84.328 66.421,84.328 67.183,84.328 67.945,84.328 64.516,85.09 65.278,85.09 66.04,85.09 66.802,85.09 67.564,85.09 64.897,85.852 65.659,85.852 66.421,85.852 67.183,85.852 67.945,85.852 64.516,86.614 65.278,86.614 66.04,86.614 66.802,86.614 67.564,86.614 64.897,87.376 65.659,87.376 66.421,87.376 67.183,87.376 67.945,87.376 67.945,88.9 64.516,89.662 65.278,89.662 66.04,89.662 66.802,89.662 67.564,89.662
FUSED_CELL.CELL_14+: F304.2 R1316_1.1 R1316_2.1 R1538.1 R1544.1 T1515.2 U1114.2 | length 312.9
  Top w0.152: U1114.2@44.133,63.817 44.133,65.645 44.66,66.173 47.785,66.173 48.142,66.53 49.828,66.53 50.955,67.657 53.696,67.657 54.161,68.123 58.39,68.123 58.846,68.58 67.323,68.58 67.625,68.882 T1515.2@67.625,70.17
  Top w0.254: v1(60.325,28.416) R1316_2.1@60.325,29.145 ; R1316_1.1@113.665,29.21 R1316_1.1@113.665,29.145 113.665,24.924 113.983,24.606 120.968,24.606 121.285,24.289 v2(121.285,22.543)
  Top w0.406: v1(60.325,80.645) R1538.1@60.325,81.65 62.177,81.65 v1(62.23,81.597) ; T1515.2@67.625,70.17 v1(67.625,71.435) ; F304.2@121.285,21.338 F304.2@121.285,21.593 v2(121.285,22.543)
  Signals1 w0.406: v1(60.325,80.645) 60.325,78.74 60.643,78.422 149.651,78.422 156.21,71.864 156.21,69.215 156.21,25.4 155.575,24.765 123.507,24.765 v2(121.285,22.543)
  SUPPLY w0.406: v1(62.23,81.597) v1(62.23,80.518) 62.23,79.692 63.182,78.74 63.182,71.755 63.503,71.435 v1(67.625,71.435)
  Bottom w0.152: v1(60.325,28.416) 60.325,25.717 60.642,25.4 80.328,25.4 80.645,25.082 82.55,25.082 82.867,24.765 84.772,24.765 85.09,24.447 86.995,24.447 87.312,24.13 89.376,24.13 89.694,23.812 89.694,22.701 89.917,22.478 92.658,22.478 93.675,23.495 120.968,23.495 121.285,23.177 v2(121.285,22.543)
  other v1: 58.42,80.518 59.182,80.518 61.468,80.518 58.42,82.042 58.801,82.804 59.563,82.804 60.325,82.804 61.087,82.804 61.849,82.804 58.42,83.566 59.182,83.566 59.944,83.566 60.706,83.566 61.468,83.566 62.23,83.566 58.801,84.328 59.563,84.328 60.325,84.328 61.087,84.328 61.849,84.328 58.42,85.09 59.182,85.09 59.944,85.09 60.706,85.09 61.468,85.09 62.23,85.09 58.801,85.852 59.563,85.852 60.325,85.852 61.087,85.852 61.849,85.852 58.42,86.614 59.182,86.614 59.944,86.614 60.706,86.614 61.468,86.614 62.23,86.614 58.801,87.376 59.563,87.376 60.325,87.376 61.087,87.376 61.849,87.376 58.42,88.138 62.23,88.138 58.42,89.662 59.182,89.662 59.944,89.662 60.706,89.662 61.468,89.662 62.23,89.662
FUSED_CELL.CELL_15+: F303.2 R1315_1.1 R1315_2.1 R1537.1 R1543.1 T1514.2 U1113.2 | length 321.1
  Top w0.152: U1113.2@40.957,63.817 40.957,65.405 41.828,66.276 44.196,66.276 44.438,66.517 46.145,66.517 47.242,67.615 49.191,67.615 49.742,68.165 53.485,68.165 53.951,68.631 58.138,68.631 58.722,69.215 61.757,69.215 61.91,69.368 T1514.2@61.91,70.17
  Top w0.254: v1(57.785,28.416) R1315_2.1@57.785,29.095 ; R1315_1.1@111.125,29.095 111.125,26.194 113.189,24.13 119.062,24.13 119.38,23.812 v2(119.38,22.543)
  Top w0.406: v1(54.61,80.645) R1537.1@54.61,81.65 56.462,81.65 v1(56.515,81.597) ; T1514.2@61.91,70.17 v1(61.91,71.435) ; F303.2@119.38,16.258 F303.2@119.38,16.513 v2(119.38,22.543)
  Signals1 w0.406: v1(54.61,80.645) 54.61,78.105 54.927,77.787 149.388,77.787 155.575,71.601 155.575,69.215 155.575,26.035 154.94,25.4 122.237,25.4 v2(119.38,22.543)
  SUPPLY w0.406: v1(56.515,81.597) 56.515,79.692 57.468,78.74 57.468,71.755 57.788,71.435 v1(61.91,71.435)
  Bottom w0.152: v1(57.785,28.416) 57.785,25.4 58.102,25.082 80.01,25.082 80.328,24.765 82.233,24.765 82.55,24.447 84.455,24.447 84.772,24.13 86.836,24.13 87.154,23.812 87.789,23.812 88.106,23.495 88.106,22.478 88.36,22.224 93.185,22.224 94.139,23.177 119.062,23.177 119.38,22.86 v2(119.38,22.543)
  other v1: 53.086,80.518 53.848,80.518 55.372,80.518 56.134,80.518 53.467,82.804 54.229,82.804 54.991,82.804 55.753,82.804 56.515,82.804 53.086,83.566 53.848,83.566 54.61,83.566 55.372,83.566 56.134,83.566 53.467,84.328 54.229,84.328 54.991,84.328 55.753,84.328 56.515,84.328 53.086,85.09 53.848,85.09 54.61,85.09 55.372,85.09 56.134,85.09 53.467,85.852 54.229,85.852 54.991,85.852 55.753,85.852 56.515,85.852 53.086,86.614 53.848,86.614 54.61,86.614 55.372,86.614 56.134,86.614 53.467,87.376 54.229,87.376 54.991,87.376 55.753,87.376 56.515,87.376 56.515,88.9 53.086,89.662 53.848,89.662 54.61,89.662 55.372,89.662 56.134,89.662
FUSED_CELL.CELL_16+: F302.2 R1314_1.1 R1314_2.1 R1536.1 R1542.1 T1513.2 U1112.2 | length 321.4
  Top w0.152: U1112.2@37.782,63.817 37.782,65.336 38.976,66.53 43.035,66.53 44.628,68.123 48.981,68.123 49.531,68.673 53.275,68.673 53.753,69.151 55.978,69.151 56.195,69.368 T1513.2@56.195,70.17
  Top w0.254: v1(55.245,28.416) R1314_2.1@55.245,29.095 ; R1314_1.1@108.585,29.095 108.585,27.305 112.236,23.654 117.157,23.654 117.475,23.336 v2(117.475,22.384)
  Top w0.406: v1(48.895,80.645) R1536.1@48.895,81.65 50.747,81.65 v1(50.8,81.597) ; T1513.2@56.195,70.17 v1(56.195,71.435) ; F302.2@117.475,21.338 F302.2@117.475,21.593 v2(117.475,22.384)
  Signals1 w0.406: v1(48.895,80.645) 48.895,77.47 49.212,77.153 149.125,77.153 154.94,71.338 154.94,69.215 154.94,26.67 154.305,26.035 121.126,26.035 v2(117.475,22.384)
  SUPPLY w0.406: v1(50.8,81.597) v1(50.8,80.518) 50.8,79.692 51.752,78.74 51.752,71.755 52.073,71.435 v1(56.195,71.435)
  Bottom w0.152: v1(55.245,28.416) 55.245,25.082 55.562,24.765 79.692,24.765 80.01,24.447 81.915,24.447 82.233,24.13 84.296,24.13 84.614,23.812 86.338,23.812 86.519,23.632 86.519,22.224 86.773,21.97 95.664,21.97 96.837,20.796 97.472,20.796 99.536,22.86 100.013,22.86 117.157,22.86 117.475,22.543 v2(117.475,22.384)
  other v1: 46.99,80.518 47.752,80.518 50.038,80.518 46.99,82.042 47.371,82.804 48.133,82.804 48.895,82.804 49.657,82.804 50.419,82.804 46.99,83.566 47.752,83.566 48.514,83.566 49.276,83.566 50.038,83.566 50.8,83.566 47.371,84.328 48.133,84.328 48.895,84.328 49.657,84.328 50.419,84.328 46.99,85.09 47.752,85.09 48.514,85.09 49.276,85.09 50.038,85.09 50.8,85.09 47.371,85.852 48.133,85.852 48.895,85.852 49.657,85.852 50.419,85.852 46.99,86.614 47.752,86.614 48.514,86.614 49.276,86.614 50.038,86.614 50.8,86.614 47.371,87.376 48.133,87.376 48.895,87.376 49.657,87.376 50.419,87.376 46.99,88.138 50.8,88.138 46.99,89.662 47.752,89.662 48.514,89.662 49.276,89.662 50.038,89.662 50.8,89.662
FUSED_CELL.CELL_17+: F301.2 R1313_1.1 R1313_2.1 T1512.2 | length 286.5
  Top w0.254: v1(52.705,28.416) R1313_2.1@52.705,29.095 ; R1313_1.1@106.045,29.095 106.045,28.258 111.125,23.177 115.252,23.177 115.57,22.86 v2(115.57,22.066)
  Top w0.406: T1512.2@50.487,70.178 T1512.2@50.48,70.17 50.48,71.177 v1(50.487,71.185) ; F301.2@115.57,16.258 F301.2@115.57,16.513 v2(115.57,22.066)
  Signals1 w0.406: v1(50.487,71.185) 51.185,71.185 51.675,71.675 51.675,76.122 52.07,76.517 148.862,76.517 154.305,71.075 154.305,69.215 154.305,27.305 153.67,26.67 120.174,26.67 v2(115.57,22.066)
  Bottom w0.152: v1(52.705,28.416) 52.705,24.765 53.023,24.447 79.375,24.447 79.692,24.13 81.597,24.13 81.915,23.812 84.138,23.812 84.931,23.019 84.931,21.895 85.155,21.671 95.486,21.671 96.615,20.542 97.695,20.542 99.695,22.542 100.33,22.542 115.252,22.543 115.57,22.225 v2(115.57,22.066)
FUSED_VBAT+: D1400_1.1 D1400_2.1 F300.2 | length 90.4
  Top w0.406: v3(51.594,30.506) 51.752,30.664 D1400_2.1@51.752,35.305 ; v3(100.33,30.48) 103.822,30.48 104.457,29.845 104.457,27.722 111.78,20.4 F300.2@112.375,20.4 112.375,21.769 111.76,22.384 110.966,22.384 105.093,28.258 D1400_1.1@105.093,35.305
  Bottom w0.406: v3(51.594,30.506) 51.594,30.069 52.059,29.604 99.454,29.604 v3(100.33,30.48)
FUSED_VBAT-: C100_1.1 C100_2.1 C101_1.1 C101_2.1 C102_1.1 C102_2.1 C103_1.1 C103_2.1 C104_1.1 C104_2.1 C105_1.1 C105_2.1 C106_1.1 C106_2.1 C107_1.1 C107_2.1 C108_1.1 C108_2.1 C109_1.1 C109_2.1 C110_1.1 C110_2.1 C111_1.1 C111_2.1 C112_1.1 C112_2.1 C113_1.1 C113_2.1 C114_1.1 C114_2.1 C115_1.1 C115_2.1 C400.1 C401.1 C402.1 C403.1 C404.1 C405.1 C406.1 C407.1 C600_1.1 C600_2.1 C601_1.1 C601_2.1 C603_1.1 C603_2.1 C605_1.1 C605_2.1 C606_1.1 C606_2.1 C607_1.2 C607_2.2 C700_1.1 C700_2.1 C701_1.1 C701_2.1 C800_1.1 C800_2.1 C801_1.1 C801_2.1 C906.2 C907.1 C908.1 C1100.1 C1300_1.2 C1300_2.2 C1301_1.2 C1301_2.2 C1302_1.2 C1302_2.2 C1303_1.2 C1303_2.2 C1304_1.2 C1304_2.2 C1305_1.2 C1305_2.2 C1312_1.2 C1312_2.2 C1313_1.2 C1313_2.2 C1314_1.2 C1314_2.2 C1315_1.2 C1315_2.2 C1316_1.2 C1316_2.2 C1317_1.2 C1317_2.2 C1324_1.2 C1324_2.2 C1325_1.2 C1325_2.2 C1326_1.2 C1326_2.2 C1327_1.2 C1327_2.2 C1328_1.2 C1328_2.2 C1329_1.2 C1329_2.2 C1400_1.2 C1400_2.2 C1401_1.1 C1401_2.1 C1402_1.1 C1402_2.1 C1403_1.1 C1403_2.1 C1404_1.1 C1404_2.1 C1405_1.1 C1405_2.1 D1401_1.2 D1401_2.2 F320.2 IC100_1.14 IC100_1.15 IC100_1.16 IC100_2.14 IC100_2.15 IC100_2.16 IC101_1.14 IC101_1.16 IC101_2.14 IC101_2.16 IC104_1.14 IC104_1.15 IC104_2.14 IC104_2.15 IC800_1.2 IC800_2.2 IC801_1.3 IC801_1.4 IC801_2.3 IC801_2.4 IC1400_1.59 IC1400_1.60 IC1400_1.65 IC1400_2.59 IC1400_2.60 IC1400_2.65 Q600_1.1 Q600_2.1 R601_1.2 R601_2.2 R603_1.2 R603_2.2 R606_1.1 R606_2.1 R1118.2 R1400_1.1 R1400_2.1 R1403_1.1 R1403_2.1 R1406_1.1 R1406_2.1 TP903.1 TP1400_1.1 TP1400_2.1 TR900.8 U100_1.2 U100_2.2 U101_1.2 U101_2.2 U600_1.1 U600_1.2 U600_1.8 U600_1.15 U600_2.1 U600_2.2 U600_2.8 U600_2.15 U700_1.2 U700_1.8 U700_2.2 U700_2.8 X201.9 X201.10 X201.11 X201.12 X201.13 X201.14 X201.15 X201.16 X202.9 X202.10 X202.11 X202.12 X202.13 X202.14 X202.15 X202.16 X400.18 X401.18 X402.10 X403.10 X404.19 X404.20 X900.2 | length 402.3
  Top w0.152: IC104_2.15@16.154,55.842 17.328,55.842 v1(17.684,56.197) ; v1(24.777,60.313) 25.031,60.567 C104_1.1@25.625,60.567 25.625,61.393 25.882,61.393 26.67,62.181 26.67,62.734 26.222,63.182 U101_1.2@25.47,63.182 ; U101_2.2@25.47,55.88 26.352,55.88 26.67,55.562 26.67,54.292 26.987,53.975 29.527,53.975 29.845,54.292 C104_2.1@29.845,54.855 v1(31.115,54.855) ; C107_1.1@29.3,66.04 v1(30.48,66.04) ; C107_2.1@29.738,58.725 31.095,58.725 v1(31.412,58.408) ; v1@36.195,75.819 v1(36.322,75.946) ; X900.2@39.052,75.248 39.052,73.343 39.529,72.866 TP903.1@43.18,72.866 ; IC800_2.2@46.038,48.825 46.038,48.95 46.618,49.53 48.122,49.53 48.578,49.075 C800_2.1@48.677,49.075 v1(49.847,49.075) ; v1(50.8,47.942) 51.117,47.625 C607_2.2@51.663,47.625 ; Q600_2.1@51.477,43.165 52.104,43.165 52.153,43.115 R606_2.1@52.705,43.115 v1(52.705,41.593) ; v1(54.134,15.716) 54.224,15.806 C700_2.1@54.224,14.764 55.086,14.764 ; R601_2.2@55.945,47.625 55.945,47.073 v1(56.197,46.821) ; U700_2.2@57.936,16.631 56.319,16.631 55.949,16.261 v1(55.949,15.716) 55.73,15.498 C701_2.1@55.73,14.764 55.086,14.764 ; U700_2.8@57.936,20.531 56.091,20.531 55.086,19.526 55.086,14.764 ; v1(62.071,18.574) 62.316,18.819 C101_2.1@63.182,18.819 ; v1(62.389,17.711) C115_2.1@63.341,17.711 ; C114_2.1@64.929,17.711 v1(64.929,18.415) ; IC100_2.16@65.814,19.95 67.672,19.95 v1(67.937,19.685) 67.937,20.154 67.945,20.161 67.506,20.6 IC100_2.15@65.814,20.6 ; IC100_2.14@65.814,21.25 67.484,21.25 v1(67.937,20.796) ; C113_2.1@66.516,17.711 v1(66.516,18.415) ; C112_2.1@68.104,17.711 v1(68.104,18.415) ; C111_2.1@69.691,17.711 v1(69.691,18.415) ; C110_2.1@71.279,17.711 v1(71.279,18.415) ; C109_2.1@72.866,17.711 v1(72.866,18.415) ; C108_2.1@74.454,17.711 v1(74.454,18.415) ; U100_2.2@75.724,22.631 75.724,21.88 76.013,21.59 77.629,21.59 77.86,21.821 C103_2.1@78.899,21.821 v1(78.899,20.796) ; v1(77.47,57.944) 77.614,58.088 R1406_2.1@78.422,58.088 ; TP1400_2.1@78.74,63.817 R1403_2.1@81.374,63.817 81.374,63.917 81.972,64.516 96.197,64.516 97.213,65.532 v1(97.79,65.532) ; v1(80.328,57.309) R1400_2.1@80.328,57.987 ; v1(83.82,12.7) 83.592,12.928 C700_1.1@83.592,13.97 84.455,13.97 ; v1(84.772,12.981) 85,13.208 C701_1.1@85,13.97 84.455,13.97 ; v1(85.407,15.24) 86.005,15.838 U700_1.2@87.305,15.838 ; U700_1.8@87.305,19.738 85.513,19.738 84.455,18.68 84.455,13.97 ; C115_1.1@91.916,17.711 v1(91.916,18.415) ; v1(93.345,18.415) 93.345,18.347 93.504,18.188 C114_1.1@93.504,17.711 ; IC100_1.16@94.389,19.95 95.991,19.95 v1(96.203,20.161) 95.764,20.6 IC100_1.15@94.389,20.6 ; IC100_1.14@94.389,21.25 96.021,21.25 97.314,22.543 97.314,24.289 98.339,25.314 C101_1.1@98.339,26.352 98.339,26.628 97.135,27.831 v1(97.135,28.575) ; v1(94.912,49.742) 94.912,50.211 95.23,50.528 IC801_2.4@95.23,51.38 ; C113_1.1@95.091,17.711 v1(95.091,18.415) ; IC801_2.3@96.5,51.38 96.5,47.486 97.16,46.826 97.16,45.349 97.785,44.724 C801_2.1@97.785,44.147 v1(96.773,44.147) ; C112_1.1@96.679,17.711 v1(96.679,18.415) ; C111_1.1@98.266,17.711 v1(98.266,18.415) ; C110_1.1@99.854,17.711 v1(99.854,18.415) ; C109_1.1@101.441,17.711 v1(101.441,18.415) ; IC800_1.2@101.6,48.825 101.6,48.95 102.18,49.53 103.653,49.53 103.881,49.302 C801_1.1@104.457,49.302 105.5,49.302 v1(105.727,49.53) ; v1(102.87,18.415) 102.87,18.347 103.029,18.188 C108_1.1@103.029,17.711 ; U100_1.2@104.299,22.631 104.299,21.88 105.065,21.114 107.305,21.114 107.474,21.282 C103_1.1@107.474,21.821 108.363,21.821 108.902,21.282 v1(108.902,20.796) ; v1(106.045,48.578) 106.273,48.35 C607_1.2@106.273,47.625 ; Q600_1.1@106.087,43.482 106.714,43.482 106.763,43.432 R606_1.1@107.315,43.432 107.315,42.981 106.68,42.346 v1(106.68,41.275) ; R601_1.2@110.555,47.625 110.555,46.925 v1(110.807,46.672) ; C1100.1@122.687,56.566 124.091,56.566 v1(124.142,56.515) ; R1118.2@122.687,61.342 v1(122.687,62.23) ; v1(131.38,57.889) 131.528,58.037 R1406_1.1@132.08,58.037 ; TP1400_1.1@132.398,63.817 v1(133.985,63.817) R1403_1.1@135.14,63.817 ; v1(133.985,57.309) R1400_1.1@133.985,57.987 ; v1(148.273,49.875) IC801_1.4@148.273,51.119 ; v1(149.225,52.451) 149.542,52.133 IC801_1.3@149.542,51.119 ; v1(149.86,43.974) C800_1.1@150.723,43.974
  Top w0.254: v1(5.334,53.086) 5.334,53.612 5.59,53.868 C102_2.1@6.141,53.868 6.141,54.695 5.965,54.871 IC101_2.16@5.965,55.193 4.938,55.193 4.811,55.319 4.811,56.089 5.215,56.493 IC101_2.14@5.965,56.493 ; C102_1.1@5.63,61.552 6.434,61.552 v1(6.604,61.722) 7.001,62.119 7.001,62.469 7.302,62.77 7.302,62.85 ; IC101_1.16@5.965,62.813 7.265,62.813 7.302,62.85 ; IC101_1.14@5.965,64.113 7.007,64.113 7.302,63.817 7.302,62.85 ; X400.18@6.35,41.275 7.392,40.233 C401.1@7.392,39.052 ; X401.18@6.35,48.895 7.392,47.853 C400.1@7.392,46.672 ; v1(14.224,62.547) C105_1.1@14.224,63.693 15.051,63.693 15.098,63.645 15.098,63.463 IC104_1.15@16.125,63.463 IC104_1.14@16.125,64.113 ; v1(14.306,54.927) C105_2.1@14.306,55.768 14.306,56.32 14.478,56.493 IC104_2.14@16.125,56.493 IC104_2.15@16.125,55.843 ; v1(18.796,31.623) 20.823,31.623 21.273,31.174 C1405_2.1@21.273,30.57 C1404_2.1@22.86,30.57 ; C407.1@24.852,31.432 23.812,31.432 22.872,32.373 6.647,32.373 6.33,32.69 X404.20@6.35,33.655 6.33,34.913 ; C404.1@24.852,38.417 23.805,38.417 22.84,37.453 7.608,37.453 X404.19@6.35,36.195 6.33,34.913 ; C402.1@29.507,41.808 30.232,41.808 30.777,41.263 X402.10@31.75,41.275 ; C403.1@29.527,49.44 31.205,49.44 X403.10@31.75,48.895 ; C406.1@31.432,34.062 31.432,34.925 ; C405.1@31.432,35.788 31.432,34.925 ; v1(32.861,29.829) 32.861,30.421 33.225,30.785 36.356,30.785 36.571,30.57 C1405_1.1@37.148,30.57 C1404_1.1@38.735,30.57 ; v1(53.975,30.48) C1324_2.2@53.975,32.155 ; v1(56.515,30.48) C1325_2.2@56.515,32.155 ; v1(59.055,30.48) C1326_2.2@59.055,32.155 ; v1(61.595,30.48) C1327_2.2@61.595,32.155 ; v1(64.135,30.48) C1328_2.2@64.135,32.155 ; v1(66.675,30.48) C1329_2.2@66.675,32.155 ; v1(69.195,30.468) C1312_2.2@69.195,32.142 ; v1(71.735,30.468) C1313_2.2@71.735,32.142 ; v1(74.275,30.468) C1314_2.2@74.275,32.142 ; v1(75.565,62.23) C1400_2.2@75.565,61.065 76.567,61.065 76.835,60.797 76.835,57.785 77.787,56.832 79.375,56.832 ; v1(76.815,30.468) C1315_2.2@76.815,32.142 ; v1(79.355,30.468) C1316_2.2@79.355,32.142 ; v1(80.962,8.096) C100_2.1@80.962,9.118 ; IC1400_2.60@81.118,55.547 IC1400_2.59@81.618,55.547 ; IC1400_2.59@81.618,55.598 81.618,56.495 81.28,56.832 79.375,56.832 ; v1(81.895,30.468) C1317_2.2@81.895,32.142 ; v1(84.138,60.397) 84.264,60.397 84.581,60.08 C1403_2.1@85.407,60.08 85.407,61.119 ; v1(84.435,30.468) C1300_2.2@84.435,32.142 ; C1403_2.1@84.99,59.78 C1403_2.1@85.09,59.78 ; v1(86.975,30.468) C1301_2.2@86.975,32.142 ; C1402_2.1@87.312,60.08 87.312,61.119 ; C1401_2.1@89.218,60.08 89.218,60.632 88.73,61.119 87.312,61.119 ; v1(89.515,30.468) C1302_2.2@89.515,32.142 ; v1(90.805,59.849) 90.964,59.69 C106_2.1@91.668,59.69 ; v1(92.055,30.468) C1303_2.2@92.055,32.142 ; v1(94.595,30.468) C1304_2.2@94.595,32.142 ; v1(97.135,30.468) C1305_2.2@97.135,32.142 ; v1@107.315,30.468 v1(107.315,30.48) C1324_1.2@107.315,32.155 ; v1(109.696,8.096) C100_1.1@109.696,9.118 ; v1@109.855,30.468 v1(109.855,30.48) C1325_1.2@109.855,32.155 ; v1@112.395,30.468 v1(112.395,30.48) C1326_1.2@112.395,32.155 ; v1@114.935,30.468 v1(114.935,30.48) C1327_1.2@114.935,32.155 ; v1@117.475,30.468 v1(117.475,30.48) C1328_1.2@117.475,32.155 ; v1@120.015,30.468 v1(120.015,30.48) C1329_1.2@120.015,32.155 ; v1@122.555,30.468 v1(122.555,30.48) C1312_1.2@122.555,32.155 ; v1(125.075,30.468) C1313_1.2@125.075,32.142 ; v1(127.615,30.639) C1314_1.2@127.615,32.142 ; C1400_1.2@129.54,61.065 C1400_1.2@129.765,61.065 ; C1315_1.2@130.155,32.283 130.155,30.659 v1(130.175,30.639) ; v1(131.445,63.024) 131.445,62.745 C1400_1.2@129.765,61.065 ; v1(132.695,30.639) C1316_1.2@132.695,32.142 ; IC1400_1.60@134.458,55.547 IC1400_1.59@134.958,55.547 ; IC1400_1.59@134.958,55.598 134.958,56.654 134.779,56.832 133.032,56.832 ; C1317_1.2@135.235,32.283 135.235,30.671 v1(135.267,30.639) ; v1(137.775,30.639) C1300_1.2@137.775,32.142 ; v1(139.382,61.277) 139.382,60.694 C1403_1.1@138.769,60.08 ; v1(140.315,30.639) C1301_1.2@140.315,32.142 ; C1401_1.1@142.13,60.08 C1402_1.1@140.272,60.08 C1403_1.1@138.769,60.08 ; C1302_1.2@142.855,32.283 142.855,30.659 v1(142.875,30.639) ; v1(143.827,59.849) 143.986,59.69 C106_1.1@145.008,59.69 ; C1303_1.2@145.395,32.283 145.395,30.726 v1(145.483,30.639) ; v1(147.848,30.639) 147.935,30.726 C1304_1.2@147.935,32.283 ; v1(150.336,30.956) 150.475,31.095 C1305_1.2@150.475,32.283 ; 6.33,34.913 31.432,34.925 ; 79.375,56.832 79.375,60.801 79.692,61.119 85.407,61.119 ; 85.407,61.119 87.312,61.119 ; C1400_1.2@129.765,61.065 130.542,61.065 130.775,60.832 130.775,57.503 131.445,56.832 133.032,56.832 ; 133.032,56.832 133.032,59.606 134.484,61.057 138.174,61.057 138.493,60.738 C1403_1.1@138.493,60.08 C1403_1.1@138.769,60.08
  Top w0.406: v1(69.532,58.42) 69.687,58.265 D1401_2.2@70.802,58.265 ; v3(125.095,56.515) D1401_1.2@125.095,58.165 ; v1(151.765,22.225) v1(153.035,22.225) ; F320.2@152.44,20.413 F320.2@153.035,20.413 ; F320.2@153.63,20.413 F320.2@153.035,20.413 ; v1(154.305,22.225) v1(153.035,22.225) ; F320.2@153.035,20.413 v1(153.035,22.225)
  other v1: 56.896,45.466 57.658,45.466 58.42,45.466 59.182,45.466 59.944,45.466 60.706,45.466 61.468,45.466 62.23,45.466 62.992,45.466 63.754,45.466 64.516,45.466 65.278,45.466 66.04,45.466 66.802,45.466 67.564,45.466 68.326,45.466 69.088,45.466 69.85,45.466 70.612,45.466 71.374,45.466 72.136,45.466 111.76,45.466 112.522,45.466 113.284,45.466 114.046,45.466 114.808,45.466 115.57,45.466 116.332,45.466 117.094,45.466 117.856,45.466 118.618,45.466 119.38,45.466 120.142,45.466 120.904,45.466 121.666,45.466 122.428,45.466 123.19,45.466 123.952,45.466 124.714,45.466 56.515,46.228 57.277,46.228 58.039,46.228 58.801,46.228 59.563,46.228 60.325,46.228 61.087,46.228 61.849,46.228 62.611,46.228 63.373,46.228 64.135,46.228 111.379,46.228 112.141,46.228 112.903,46.228 113.665,46.228 114.427,46.228 115.189,46.228 115.951,46.228 116.713,46.228 117.475,46.228 118.237,46.228 118.999,46.228 56.896,46.99 57.658,46.99 58.42,46.99 59.182,46.99 111.76,46.99 112.522,46.99 113.284,46.99 114.046,46.99 80.962,47.625 81.597,47.625 82.233,47.625 82.867,47.625 83.502,47.625 84.138,47.625 84.772,47.625 134.302,47.625 134.938,47.625 135.572,47.625 136.207,47.625 136.843,47.625 137.477,47.625 138.112,47.625 57.277,47.752 58.039,47.752 58.801,47.752 59.563,47.752 61.087,47.752 61.849,47.752 62.611,47.752 63.373,47.752 111.379,47.752 112.141,47.752 112.903,47.752 113.665,47.752 115.951,47.752 116.713,47.752 117.475,47.752 118.237,47.752 80.645,48.26 81.28,48.26 81.915,48.26 82.55,48.26 83.185,48.26 83.82,48.26 84.455,48.26 85.09,48.26 134.62,48.26 135.255,48.26 135.89,48.26 136.525,48.26 137.16,48.26 137.795,48.26 138.43,48.26 56.896,48.514 57.658,48.514 58.42,48.514 111.76,48.514 112.522,48.514 113.284,48.514 80.962,48.895 81.597,48.895 82.233,48.895 82.867,48.895 83.502,48.895 84.138,48.895 84.772,48.895 134.302,48.895 134.938,48.895 135.572,48.895 136.207,48.895 136.843,48.895 137.477,48.895 138.112,48.895 56.515,49.276 57.277,49.276 58.039,49.276 58.801,49.276 111.379,49.276 112.141,49.276 112.903,49.276 80.645,49.53 81.28,49.53 81.915,49.53 82.55,49.53 83.185,49.53 83.82,49.53 84.455,49.53 85.09,49.53 134.62,49.53 135.255,49.53 135.89,49.53 136.525,49.53 137.16,49.53 137.795,49.53 138.43,49.53 80.962,50.165 81.597,50.165 82.233,50.165 82.867,50.165 83.502,50.165 84.138,50.165 84.772,50.165 134.302,50.165 134.938,50.165 135.572,50.165 136.207,50.165 136.843,50.165 137.477,50.165 138.112,50.165 56.685,50.335 57.785,50.335 58.885,50.335 111.295,50.335 112.395,50.335 113.495,50.335 80.645,50.8 81.28,50.8 81.915,50.8 82.55,50.8 83.185,50.8 83.82,50.8 84.455,50.8 85.09,50.8 134.62,50.8 135.255,50.8 135.89,50.8 136.525,50.8 137.16,50.8 137.795,50.8 138.43,50.8 56.685,51.435 57.785,51.435 58.885,51.435 80.962,51.435 81.597,51.435 82.233,51.435 82.867,51.435 83.502,51.435 84.138,51.435 84.772,51.435 111.295,51.435 112.395,51.435 113.495,51.435 134.302,51.435 134.938,51.435 135.572,51.435 136.207,51.435 136.843,51.435 137.477,51.435 138.112,51.435 80.645,52.07 81.28,52.07 81.915,52.07 82.55,52.07 83.185,52.07 83.82,52.07 84.455,52.07 85.09,52.07 135.255,52.07 135.89,52.07 136.525,52.07 137.16,52.07 137.795,52.07 138.43,52.07 56.685,52.535 57.785,52.535 58.885,52.535 111.295,52.535 112.395,52.535 113.495,52.535 55.753,53.848 56.515,53.848 57.277,53.848 58.039,53.848 58.801,53.848 110.617,53.848 111.379,53.848 112.141,53.848 112.903,53.848 113.665,53.848 54.61,54.61 55.372,54.61 56.134,54.61 56.896,54.61 57.658,54.61 58.42,54.61 108.712,54.61 109.474,54.61 110.236,54.61 110.998,54.61 111.76,54.61 112.522,54.61 113.284,54.61 52.705,55.372 53.467,55.372 54.229,55.372 54.991,55.372 55.753,55.372 56.515,55.372 57.277,55.372 58.039,55.372 58.801,55.372 106.807,55.372 107.569,55.372 108.331,55.372 109.093,55.372 109.855,55.372 110.617,55.372 111.379,55.372 112.141,55.372 112.903,55.372 113.665,55.372 30.988,74.422 31.75,74.422 32.512,74.422 33.274,74.422 34.036,74.422 34.798,74.422 35.56,74.422 36.322,74.422 37.084,74.422 37.846,74.422 31.369,75.184 32.131,75.184 32.893,75.184 33.655,75.184 34.417,75.184 35.179,75.184 35.941,75.184 36.703,75.184 37.465,75.184 33.274,75.946 34.036,75.946 34.798,75.946 35.56,75.946 37.084,75.946 37.846,75.946 32.893,76.708 33.655,76.708 34.417,76.708 35.179,76.708 35.941,76.708 36.703,76.708 37.465,76.708 38.227,76.708 38.989,76.708 33.274,77.47 34.036,77.47 34.798,77.47 35.56,77.47 36.322,77.47 37.084,77.47 32.893,78.232 33.655,78.232 34.417,78.232 35.179,78.232 35.941,78.232 36.703,78.232 37.465,78.232 33.274,78.994 34.036,78.994 34.798,78.994 35.56,78.994 36.322,78.994 37.084,78.994 35.941,79.756 36.703,79.756 37.465,79.756 35.56,80.518 36.322,80.518 37.084,80.518 35.941,81.28 36.703,81.28 37.465,81.28 37.084,82.042
GLOBAL-BAL-FB: C1100.2 R1118.1 R1413_1.1 R1413_2.1 U1100.3 U1101.3 U1102.3 U1103.3 U1104.3 U1105.3 U1106.3 U1107.3 U1108.3 U1109.3 U1110.3 U1111.3 U1112.3 U1113.3 U1114.3 U1115.3 U1116.3 U1117.3 | length 192.9
  Top w0.152: U1112.3@37.782,57.468 v1(37.782,60.008) ; U1113.3@40.957,57.468 40.957,59.69 41.275,60.008 v1(41.91,60.008) ; U1114.3@44.133,57.468 44.133,59.055 44.45,59.372 v1(45.085,59.372) ; U1115.3@47.307,57.468 v1(47.307,59.372) ; U1116.3@50.482,57.468 v1(50.482,59.372) ; U1117.3@53.657,57.468 v1(53.657,59.372) ; U1106.3@56.832,57.468 v1(56.832,59.372) ; U1107.3@60.008,57.468 v1(60.008,59.372) ; U1108.3@63.182,57.468 v1(63.182,59.372) ; U1109.3@66.358,57.468 v1(66.358,59.372) ; v1(67.627,60.325) 67.627,62.208 69.555,64.135 76.903,64.135 78.173,62.865 96.837,62.865 98.742,60.96 v1(98.742,60.325) 120.332,60.325 121.602,59.055 v1(122.687,59.055) ; R1413_2.1@93.143,51.911 93.821,51.911 v1(93.98,52.07) ; U1110.3@97.472,57.468 97.472,56.491 97.766,56.197 100.647,56.197 ; U1111.3@100.647,57.468 100.647,56.197 ; U1100.3@103.822,57.468 103.822,56.197 ; U1101.3@106.998,57.468 106.998,56.197 ; U1102.3@110.172,57.468 110.172,56.197 ; U1103.3@113.347,57.468 113.347,56.197 ; U1104.3@116.522,57.468 116.522,56.197 ; U1105.3@119.697,57.468 119.697,56.197 ; R1118.1@122.687,59.942 v1(122.687,59.055) ; v1(143.002,55.372) 143.075,55.372 143.915,54.532 144.79,54.532 145.732,53.589 145.732,52.711 146.433,52.011 R1413_1.1@146.433,51.911 ; 100.647,56.197 103.822,56.197 ; 103.822,56.197 106.998,56.197 ; 106.998,56.197 110.172,56.197 ; 110.172,56.197 113.347,56.197 ; 113.347,56.197 116.522,56.197 ; 116.522,56.197 119.697,56.197 ; 119.697,56.197 121.285,56.197 121.602,56.515 121.602,57.031 122.587,58.016 C1100.2@122.687,58.016 v1(122.687,59.055)
  Signals1 w0.152: v1(122.687,59.055) 126.682,59.055 130.175,55.562 140.335,55.562 140.765,55.133 v1(140.765,54.678)
  Bottom w0.152: v1(37.782,60.008) v1(41.91,60.008) 42.545,59.372 v1(45.085,59.372) v1(47.307,59.372) v1(50.482,59.372) v1(53.657,59.372) v1(56.832,59.372) v1(60.008,59.372) v1(63.182,59.372) v1(66.358,59.372) 67.31,60.325 v1(67.627,60.325) ; v1(93.98,52.07) 98.404,52.058 98.722,52.375 99.039,52.692 99.039,55.792 98.742,56.089 v1(98.742,60.325) ; v1(140.765,54.678) 141.459,55.372 v1(143.002,55.372)
GPIO1_1: IC1400_1.39 R1408_1.2 R1409_1.2 | length 17.7
  Top w0.254: IC1400_1.39@141.908,49.097 143.395,49.097 v1(144.145,49.847) ; v1(143.351,58.03) 143.408,57.974 144.24,57.974 144.527,58.261 R1409_1.2@145.033,58.261 145.554,58.261 145.732,58.439 145.732,60.96 145.574,61.119 R1408_1.2@145.033,61.119
  Signals2 w0.254: v1(143.351,58.03) 143.408,57.974 144.21,57.974 144.433,57.751 144.433,50.135 v1(144.145,49.847)
GPIO1_2: IC1400_2.39 R1408_2.2 R1409_2.2 | length 17.6
  Top w0.254: IC1400_2.39@88.618,49.097 90.69,49.097 v1(90.805,49.212) ; v1(90.805,58.102) 90.871,58.168 91.095,58.261 R1409_2.2@91.642,58.261 ; R1409_2.2@91.693,58.261 92.234,58.261 92.392,58.42 92.392,60.96 92.234,61.119 R1408_2.2@91.693,61.119
  Signals2 w0.254: v1(90.805,49.212) 91.44,49.212 91.772,49.545 91.772,57.77 91.44,58.102 v1(90.805,58.102)
GPIO2_1: IC1400_1.40 R1410_1.2 R1411_1.2 | length 10.4
  Top w0.152: IC1400_1.40@141.958,49.598 143.125,49.598 143.269,49.741 v1(143.269,49.847) ; v1(143.764,55.499) 143.923,55.34 R1411_1.2@145.033,55.34 R1410_1.2@145.033,56.515
  Bottom w0.152: v1(143.269,49.847) 144.382,50.96 144.382,54.373 143.764,54.991 v1(143.764,55.499)
GPIO2_2: IC1400_2.40 R1410_2.2 R1411_2.2 | length 10.3
  Top w0.152: IC1400_2.40@88.568,49.597 90.237,49.597 v1(90.646,50.006) ; v1(90.805,54.927) 90.964,55.086 R1411_2.2@91.642,55.086 ; R1411_2.2@91.693,55.086 R1410_2.2@91.693,56.515
  Bottom w0.152: v1(90.646,50.006) 90.829,50.006 91.518,50.696 91.518,54.214 v1(90.805,54.927)
GPIO3_1: IC1400_1.41 R1412_1.2 R1413_1.2 | length 10.5
  Top w0.152: v1(140.721,50.482) 141.106,50.097 IC1400_1.41@141.908,50.097 ; v1(143.002,54.61) 143.478,54.61 143.81,54.278 144.195,54.278 145.033,53.44 R1412_1.2@145.033,53.34 R1413_1.2@145.033,51.911
  Bottom w0.152: v1(140.721,50.482) 140.721,52.329 v1(143.002,54.61)
GPIO3_2: IC1400_2.41 R1412_2.2 R1413_2.2 | length 5.6
  Top w0.152: IC1400_2.41@88.618,50.097 89.785,50.097 v1(89.852,50.165) ; v1(90.964,51.752) 90.964,51.911 R1413_2.2@91.642,51.911 ; R1413_2.2@91.693,51.911 R1412_2.2@91.693,53.34
  Bottom w0.152: v1(89.852,50.165) 90.964,51.276 v1(90.964,51.752)
GPIO4_1: IC1400_1.42 R1414_1.2 R1415_1.2 | length 4.8
  Top w0.152: IC1400_1.42@141.958,50.598 144.541,50.598 145.033,50.106 R1414_1.2@145.033,50.006 R1415_1.2@145.033,48.578
GPIO4_2: IC1400_2.42 R1414_2.2 R1415_2.2 | length 5
  Top w0.254: IC1400_2.42@88.568,50.597 89.415,50.597 89.61,50.793 91.165,50.793 91.693,50.265 R1414_2.2@91.693,50.165 R1415_2.2@91.693,48.736 ; IC1400_2.42@88.618,50.598 IC1400_2.42@88.631,50.611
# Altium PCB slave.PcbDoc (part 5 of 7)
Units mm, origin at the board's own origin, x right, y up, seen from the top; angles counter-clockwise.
Board outline 160 x 100 mm, 6 copper layers (Top, FUSED_VBAT-, Signals1, Signals2, SUPPLY, Bottom), stack 1.67 mm thick; 597 components, 381 nets, 1695 pads, 3029 vias.

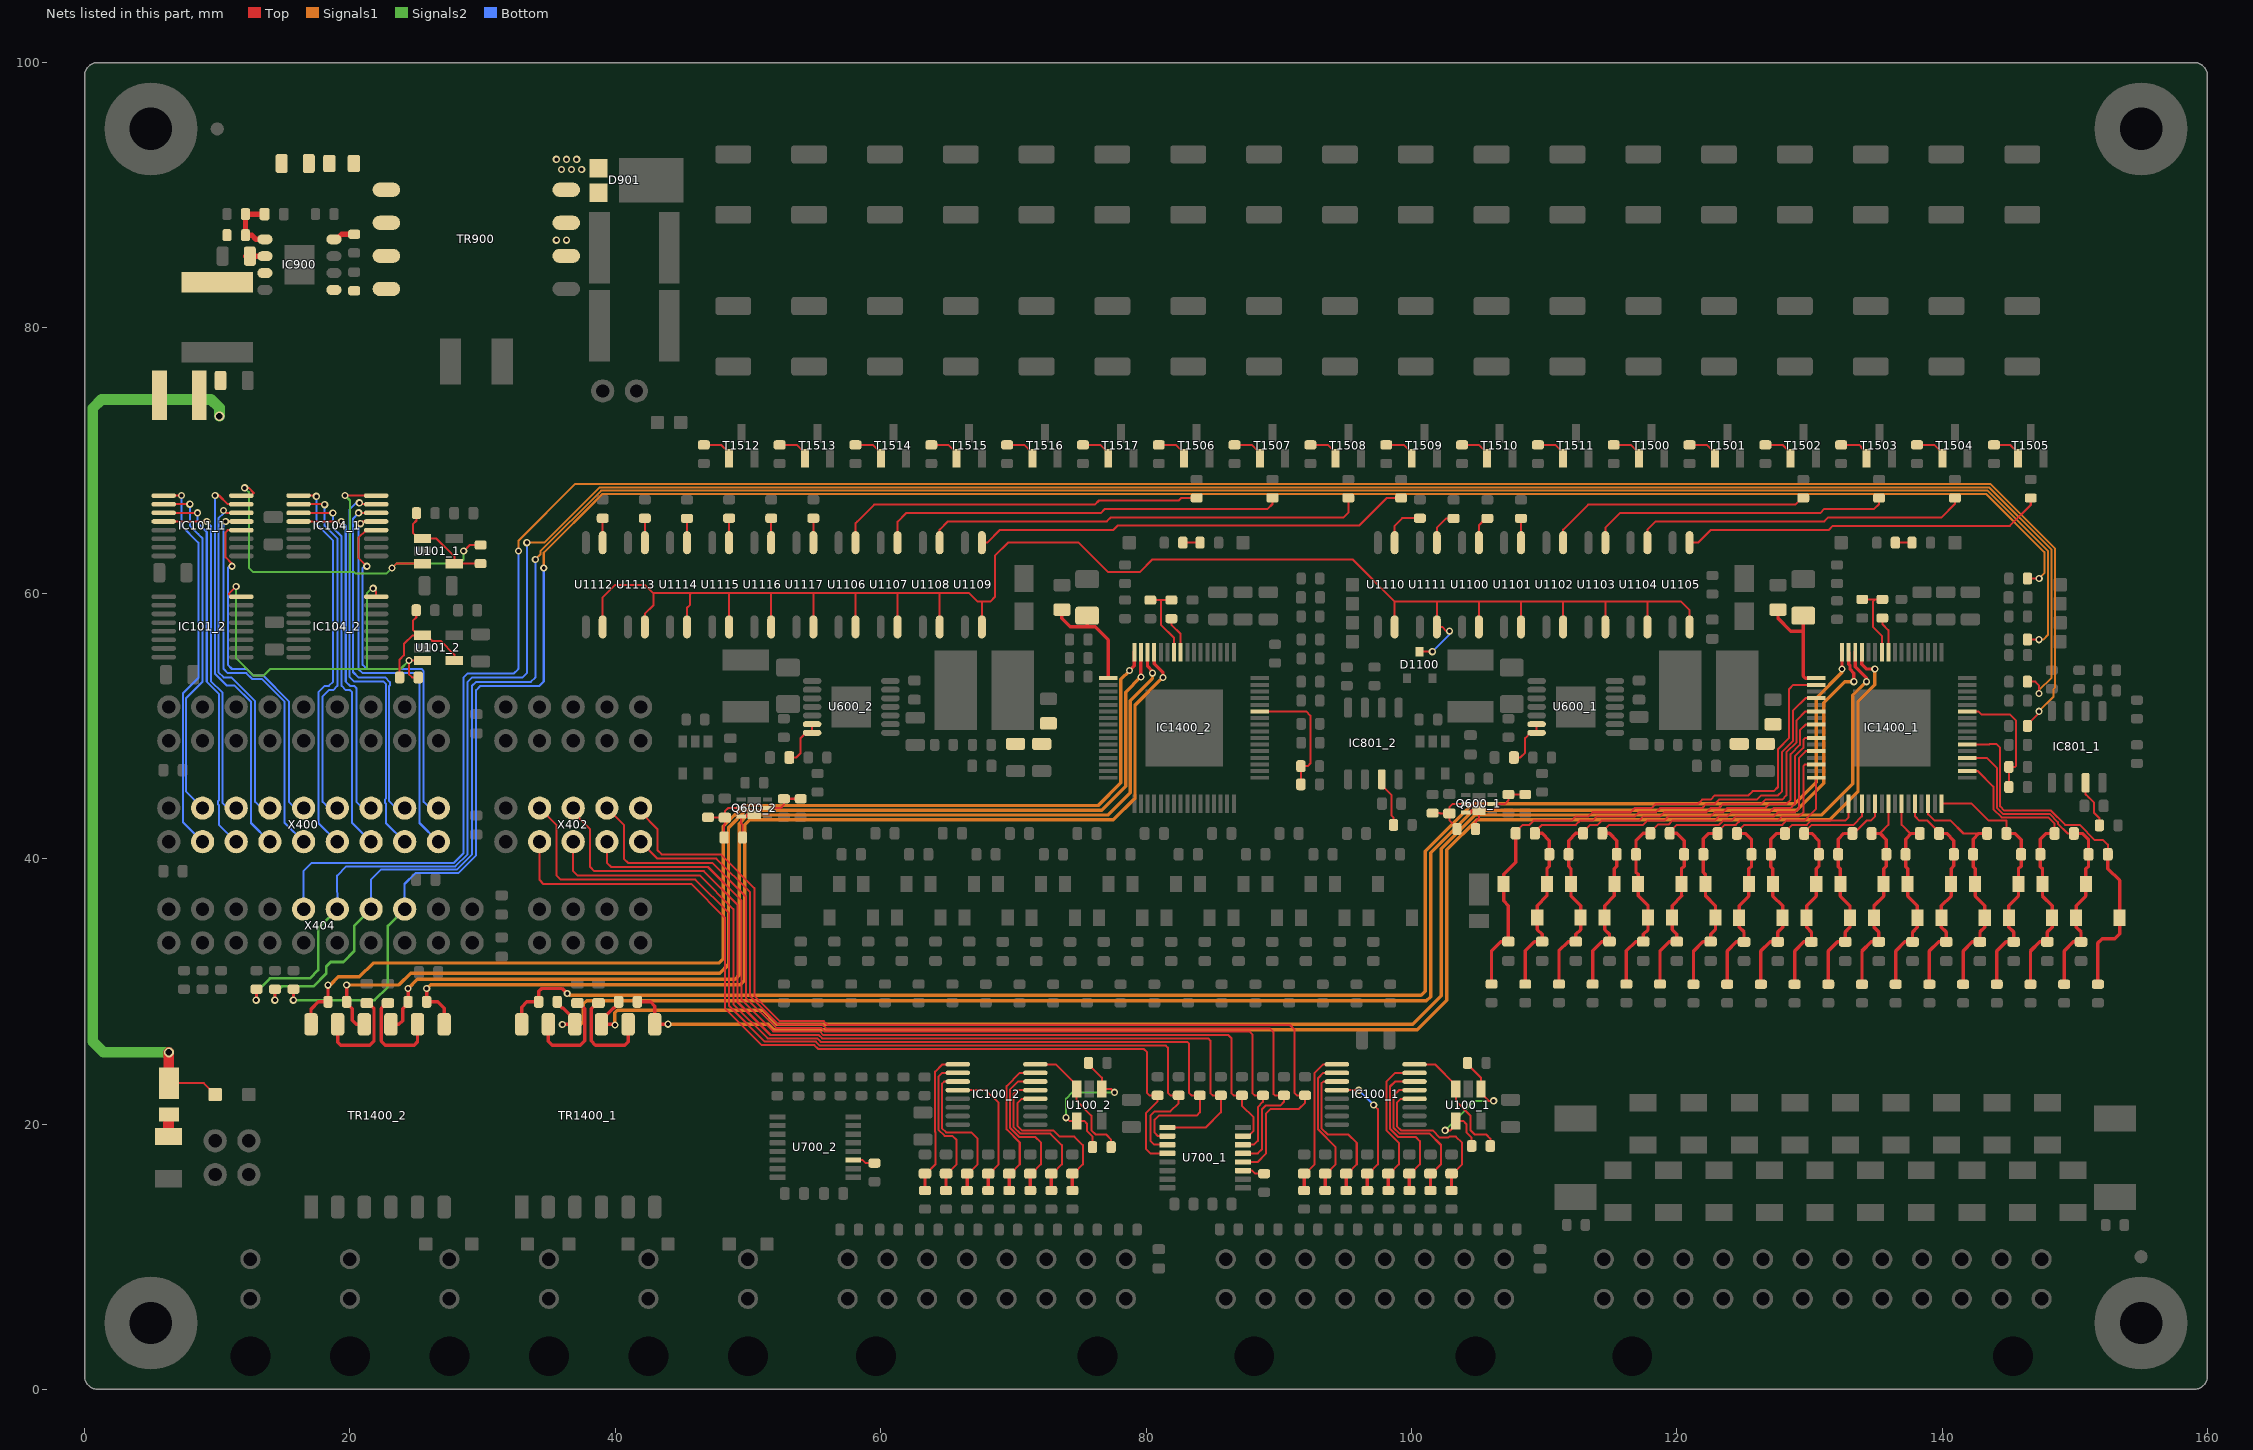
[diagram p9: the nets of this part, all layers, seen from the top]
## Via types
v1: diameter 0.55, hole 0.3, Top to Bottom, tented both sides, 2991 vias
v2: diameter 0.75, hole 0.5, Top to Bottom, tented both sides, 22 vias
v3: diameter 0.65, hole 0.4, Top to Bottom, tented both sides, 16 vias

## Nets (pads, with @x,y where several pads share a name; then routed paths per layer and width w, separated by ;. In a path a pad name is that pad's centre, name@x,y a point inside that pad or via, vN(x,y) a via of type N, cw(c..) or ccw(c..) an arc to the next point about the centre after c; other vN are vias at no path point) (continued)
GPIO5_1: IC1400_1.43 R1416_1.2 R1417_1.2 | length 9.4
  Top w0.152: IC1400_1.43@141.958,51.097 142.736,51.097 142.982,50.852 145.136,50.852 145.56,50.427 145.56,46.977 145.499,46.915 R1416_1.2@145.033,46.915 R1417_1.2@145.033,45.402
GPIO5_2: IC1400_2.43 R1416_2.2 R1417_2.2 | length 9.7
  Top w0.152: IC1400_2.43@88.618,51.097 92.075,51.097 92.392,50.78 92.392,47.169 92.194,46.97 R1416_2.2@91.672,46.97 R1417_2.2@91.672,45.605 ; R1417_2.2@91.642,45.561 R1417_2.2@91.642,45.605
ICMP_1: IC1400_1.58 R1400_1.2 R1402_1.1 | length 5.8
  Top w0.152: R1400_1.2@133.985,59.537 134.944,59.537 ; IC1400_1.58@135.457,55.598 135.457,56.789 134.779,57.468 134.779,59.372 134.944,59.537 ; R1402_1.1@135.496,59.538 134.944,59.538
ICMP_2: IC1400_2.58 R1400_2.2 R1402_2.1 | length 5.9
  Top w0.152: R1400_2.2@80.328,59.488 81.121,59.488 ; R1402_2.1@81.915,59.488 81.121,59.488 ; IC1400_2.58@82.117,55.598 82.117,56.63 81.121,57.626 81.121,59.488
IN_N1_1: IC1400_1.61 R1405_1.2 TR1400_1.7 | length 119.7
  Top w0.254: R1405_1.2@41.657,29.11 R1405_1.2@41.657,29.21 42.657,29.21 42.974,28.892 TR1400_1.7@42.974,27.517 43.97,27.517 v1(43.974,27.521) ; IC1400_1.61@133.958,55.598 133.958,54.659 134.324,54.292 v1(134.938,54.292)
  Signals1 w0.254: v1(43.974,27.521) 51.536,27.521 51.943,27.115 100.457,27.115 102.672,29.33 102.672,40.663 104.948,42.939 131.521,42.939 133.667,45.085 133.667,51.849 134.938,53.119 v1(134.938,54.292)
IN_N1_2: IC1400_2.61 R1405_2.2 TR1400_2.7 | length 82.1
  Top w0.254: v1(25.783,30.212) R1405_2.2@25.782,29.21 26.613,29.21 27.099,28.723 TR1400_2.7@27.099,27.517 ; IC1400_2.61@80.618,55.598 80.618,54.689 80.726,54.58 80.737,54.58 81.28,54.037 v1(81.28,53.657)
  Signals1 w0.254: v1(25.783,30.212) 26.076,30.506 29.369,30.506 49.434,30.506 49.751,30.823 49.751,42.545 50.145,42.939 77.546,42.939 79.172,44.564 79.172,51.549 v1(81.28,53.657)
IN_P1_1: IC1400_1.62 R1405_1.1 TR1400_1.9 | length 122.7
  Top w0.254: v1(39.971,27.464) 39.918,27.517 TR1400_1.9@38.961,27.517 38.961,27.866 39.834,28.739 39.887,28.739 40.257,29.11 R1405_1.1@40.257,29.21 ; IC1400_1.62@133.457,55.598 133.457,54.472 134.302,53.627 v1(134.302,53.34)
  Signals1 w0.254: v1(39.971,27.464) 39.971,28.372 40.162,28.563 51.097,28.563 52.139,27.521 100.114,27.521 102.266,29.673 102.266,40.76 104.801,43.294 130.924,43.294 133.265,45.635 133.265,52.302 v1(134.302,53.34)
IN_P1_2: IC1400_2.62 R1405_2.1 TR1400_2.9 | length 82.3
  Top w0.254: TR1400_2.9@23.086,27.517 23.696,27.517 23.971,27.793 23.971,28.699 24.382,29.11 R1405_2.1@24.382,29.21 v1(24.382,30.212) ; IC1400_2.62@80.117,55.598 80.117,54.503 80.486,54.134 v1(80.486,53.975)
  Signals1 w0.254: v1(24.382,30.212) 25.082,30.912 49.027,30.912 49.345,31.23 49.345,42.641 49.998,43.294 77.153,43.294 78.816,44.958 78.816,51.904 80.486,53.574 v1(80.486,53.975)
LTC-V+_1: C1400_1.1 IC1400_1.1 R1401_1.2 | length 8.5
  Top w0.254: R1401_1.2@127.635,58.765 127.635,58.102 128.588,57.15 129.54,57.15 ; C1400_1.1@129.54,58.315 129.54,57.15 ; IC1400_1.1@130.508,53.597 129.706,53.597 129.54,53.763 129.54,57.15
LTC-V+_2: C1400_2.1 IC1400_2.1 R1401_2.2 | length 8.6
  Top w0.254: R1401_2.2@73.66,58.765 73.66,58.102 74.295,57.468 75.565,57.468 ; C1400_2.1@75.565,58.315 75.565,57.468 ; IC1400_2.1@77.168,53.597 77.168,56.483 76.183,57.468 75.565,57.468
NetC108_1_2: C108_1.2 IC100_1.4 R112_1.1 | length 12.7
  Top w0.152: IC100_1.4@100.239,21.9 99.212,21.9 98.901,21.589 98.901,19.844 99.219,19.526 101.6,19.526 102.154,18.972 102.782,18.972 102.86,19.05 103.346,19.05 103.822,18.574 103.822,16.955 103.129,16.261 C108_1.2@103.029,16.261
  Top w0.254: R112_1.1@103.029,14.988 C108_1.2@103.029,16.261
NetC108_2_2: C108_2.2 IC100_2.4 R112_2.1 | length 12.5
  Top w0.152: IC100_2.4@71.664,21.9 70.636,21.9 70.326,21.59 70.326,19.844 70.644,19.526 73.025,19.526 73.501,19.05 74.603,19.05 75.248,18.405 75.248,16.955 74.554,16.261 C108_2.2@74.454,16.261
  Top w0.254: R112_2.1@74.454,14.988 C108_2.2@74.454,16.261
NetC109_1_2: C109_1.2 IC100_1.5 R113_1.1 | length 12.1
  Top w0.152: IC100_1.5@100.239,22.55 99.068,22.55 98.647,22.13 98.647,19.739 99.114,19.272 101.378,19.272 102.235,18.415 102.235,16.955 101.541,16.261 C109_1.2@101.441,16.261
  Top w0.254: R113_1.1@101.441,14.988 C109_1.2@101.441,16.261
NetC109_2_2: C109_2.2 IC100_2.5 R113_2.1 | length 12.2
  Top w0.152: IC100_2.5@71.664,22.55 70.334,22.55 70.009,22.225 70.009,19.802 70.539,19.272 72.793,19.272 73.66,18.405 73.66,16.955 72.966,16.261 C109_2.2@72.866,16.261
  Top w0.254: R113_2.1@72.866,14.988 C109_2.2@72.866,16.261
NetC110_1_2: C110_1.2 IC100_1.6 R114_1.1 | length 11.9
  Top w0.152: C110_1.2@99.854,16.261 99.954,16.261 100.647,16.955 100.647,18.701 100.33,19.018 99.008,19.018 98.393,19.633 98.393,22.828 98.765,23.2 IC100_1.6@100.239,23.2
  Top w0.254: R114_1.1@99.854,14.988 C110_1.2@99.854,16.261
NetC110_2_2: C110_2.2 IC100_2.6 R114_2.1 | length 11.8
  Top w0.152: C110_2.2@71.279,16.261 71.379,16.261 72.072,16.955 72.072,18.61 71.664,19.018 70.433,19.018 69.755,19.697 69.755,22.606 70.349,23.2 IC100_2.6@71.664,23.2
  Top w0.254: R114_2.1@71.279,14.988 C110_2.2@71.279,16.261
NetC111_1_2: C111_1.2 IC100_1.7 R115_1.1 | length 11.4
  Top w0.152: C111_1.2@98.266,16.261 98.366,16.261 99.06,16.955 99.06,18.574 98.139,19.494 98.139,23.209 98.78,23.85 IC100_1.7@100.239,23.85
  Top w0.254: R115_1.1@98.266,14.988 C111_1.2@98.266,16.261
NetC111_2_2: C111_2.2 IC100_2.7 R115_2.1 | length 11.2
  Top w0.152: C111_2.2@69.691,16.261 69.791,16.261 70.485,16.955 70.485,18.607 69.501,19.592 69.501,22.851 70.5,23.85 IC100_2.7@71.664,23.85
  Top w0.254: R115_2.1@69.691,14.988 C111_2.2@69.691,16.261
NetC112_1_2: C112_1.2 IC100_1.12 R116_1.1 | length 10.2
  Top w0.152: IC100_1.12@94.389,22.55 96.036,22.55 v1(96.044,22.543) ; C112_1.2@96.679,16.261 96.779,16.261 97.472,16.955 97.472,21.114 v1(97.155,21.431)
  Top w0.254: R116_1.1@96.679,14.988 C112_1.2@96.679,16.261
  Bottom w0.152: v1(96.044,22.543) v1(97.155,21.431)
NetC112_2_2: C112_2.2 IC100_2.12 R116_2.1 | length 10.5
  Top w0.152: IC100_2.12@65.814,22.55 67.937,22.55 68.897,21.59 68.897,16.955 68.204,16.261 C112_2.2@68.104,16.261
  Top w0.254: R116_2.1@68.104,14.988 C112_2.2@68.104,16.261
NetC113_1_2: C113_1.2 IC100_1.11 R117_1.1 | length 11.7
  Top w0.152: IC100_1.11@94.389,23.2 93.362,23.2 93.218,23.056 93.218,19.695 93.704,19.209 95.25,19.209 95.885,18.574 95.885,16.955 95.191,16.261 C113_1.2@95.091,16.261
  Top w0.254: R117_1.1@95.091,14.988 C113_1.2@95.091,16.261
NetC113_2_2: C113_2.2 IC100_2.11 R117_2.1 | length 11.9
  Top w0.152: IC100_2.11@65.814,23.2 64.793,23.2 64.611,23.019 64.611,19.685 64.929,19.367 66.834,19.367 67.31,18.891 67.31,16.955 66.616,16.261 C113_2.2@66.516,16.261
  Top w0.254: R117_2.1@66.516,14.988 C113_2.2@66.516,16.261
NetC114_1_2: C114_1.2 IC100_1.10 R118_1.1 | length 11
  Top w0.152: C114_1.2@93.504,16.261 93.604,16.261 94.297,16.955 94.297,18.256 92.964,19.59 92.964,23.452 93.362,23.85 IC100_1.10@94.389,23.85
  Top w0.254: R118_1.1@93.504,14.988 C114_1.2@93.504,16.261
NetC114_2_2: C114_2.2 IC100_2.10 R118_2.1 | length 11.4
  Top w0.152: C114_2.2@64.929,16.261 65.029,16.261 65.722,16.955 65.722,18.796 65.405,19.113 64.824,19.113 64.357,19.58 64.357,23.558 64.649,23.85 IC100_2.10@65.814,23.85
  Top w0.254: R118_2.1@64.929,14.988 C114_2.2@64.929,16.261
NetC115_1_2: C115_1.2 IC100_1.9 R119_1.1 | length 11.2
  Top w0.152: C115_1.2@91.916,16.261 92.016,16.261 92.71,16.955 92.71,23.848 93.362,24.5 IC100_1.9@94.389,24.5
  Top w0.254: R119_1.1@91.916,14.988 C115_1.2@91.916,16.261
NetC115_2_2: C115_2.2 IC100_2.9 R119_2.1 | length 11.3
  Top w0.152: C115_2.2@63.341,16.261 63.441,16.261 64.135,16.955 64.135,19.367 64.103,19.399 64.103,23.939 64.664,24.5 IC100_2.9@65.814,24.5
  Top w0.254: R119_2.1@63.341,14.988 C115_2.2@63.341,16.261
NetC605_1_2: C605_1.2 C606_1.2 R604_1.2
NetC605_2_2: C605_2.2 C606_2.2 R604_2.2
NetC607_1_1: C607_1.1 U600_1.6 U600_1.7 | length 3.8
  Top w0.152: C607_1.1@107.722,47.625 108.199,47.625 108.57,47.996 108.57,49.085 108.97,49.485 U600_1.7@109.445,49.485 U600_1.6@109.445,50.135
NetC607_2_1: C607_2.1 U600_2.6 U600_2.7 | length 3.8
  Top w0.152: C607_2.1@53.112,47.625 53.643,47.625 53.96,47.942 53.96,49.085 54.36,49.485 U600_2.7@54.835,49.485 U600_2.6@54.835,50.135
NetC608_1_2: C608_1.2 Q600_1.5 R607_1.1 R608_1.2 | length 4.5
  Top w0.152: R607_1.1@101.6,43.432 102.152,43.432 102.177,43.408 C608_1.2@102.87,43.408 ; R608_1.2@103.44,42.227 103.44,42.327 102.87,42.898 C608_1.2@102.87,43.408 ; Q600_1.5@104.097,44.132 103.118,44.132 102.87,43.884 C608_1.2@102.87,43.408
NetC608_2_2: C608_2.2 Q600_2.5 R607_2.1 R608_2.2 | length 4.6
  Top w0.152: R607_2.1@46.988,43.115 47.658,43.115 47.683,43.09 C608_2.2@48.26,43.09 ; R608_2.2@48.195,41.593 48.195,42.548 48.26,42.613 C608_2.2@48.26,43.09 ; Q600_2.5@49.487,43.815 48.508,43.815 48.26,43.567 C608_2.2@48.26,43.09
NetC900_2: C900.2 D900.2 L900.1 TP901.1 | length 70.7
  Top w0.152: D900.2@6.35,23.075 8.992,23.075 TP901.1@9.842,22.225
  Top w0.813: D900.2@6.35,23.075 v2(6.35,25.4)
  Signals2 w0.813: v2(6.35,25.4) 1.429,25.4 0.61,26.219 0.61,73.952 1.27,74.612 9.525,74.612 10.16,73.977 v2(10.16,73.343)
NetC902_2: C902.2 C905.2 IC900.3 L900.2 R900.2 TR900.3 TR900.4
NetC903_2: C903.2 IC900.1 R900.1 R901.2 | length 4.6
  Top w0.406: C903.2@13.563,88.582 R901.2@12.13,88.582 12.13,87.547 R900.1@12.13,86.995 12.6,86.995 12.918,86.677 IC900.1@13.591,86.677
NetC904_2: C904.2 IC900.2 | length 1.4
  Top w0.406: C904.2@12.155,85.407 IC900.2@13.591,85.407
NetC905_1: C905.1 R903.2
NetC1404_1_2: C1404_1.2 TR1400_1.8 | length 7.5
  Top w0.254: C1404_1.2@38.735,29.12 38.635,29.12 38.195,28.68 38.195,26.257 38.506,25.947 40.71,25.947 40.968,26.204 TR1400_1.8@40.968,27.517
NetC1404_2_2: C1404_2.2 TR1400_2.8 | length 7.4
  Top w0.254: C1404_2.2@22.86,29.12 22.76,29.12 22.349,28.709 22.349,26.254 22.657,25.947 24.835,25.947 25.093,26.204 TR1400_2.8@25.093,27.517
NetC1405_1_2: C1405_1.2 TR1400_1.11 | length 7.4
  Top w0.254: TR1400_1.11@34.948,27.517 34.948,26.241 35.242,25.947 37.377,25.947 37.691,26.261 37.691,28.676 37.247,29.12 C1405_1.2@37.148,29.12
NetC1405_2_2: C1405_2.2 TR1400_2.11 | length 7.5
  Top w0.254: TR1400_2.11@19.073,27.517 19.073,26.171 19.297,25.947 21.502,25.947 21.816,26.261 21.816,28.676 21.372,29.12 C1405_2.2@21.273,29.12
NetD900_1: D900.1 F900.2 | length 1.7
  Top w0.813: F900.2@6.33,19.053 6.33,20.053 6.35,20.073 D900.1@6.35,20.7
NetD901_2: D901.2 D901.3 TR900.5
  other v1: 35.941,91.948 36.703,91.948 37.465,91.948 35.56,92.71 36.322,92.71 37.084,92.71
NetD1100_3: D1100.3 U1100.4 U1101.4 U1102.4 U1103.4 U1104.4 U1105.4 U1106.4 U1107.4 U1108.4 U1109.4 U1110.4 U1111.4 U1112.4 U1113.4 U1114.4 U1115.4 U1116.4 U1117.4 | length 133
  Top w0.152: U1112.4@39.052,57.468 39.052,59.69 40.005,60.642 42.227,60.642 42.862,60.008 ; U1113.4@42.227,57.468 42.227,58.444 42.862,59.079 42.862,60.008 ; U1114.4@45.402,57.468 45.402,58.906 45.639,59.143 45.639,59.927 45.72,60.008 ; U1115.4@48.578,57.468 48.578,60.008 ; U1116.4@51.752,57.468 51.752,60.008 ; U1117.4@54.927,57.468 54.927,60.008 ; U1106.4@58.102,57.468 58.102,60.008 ; U1107.4@61.277,57.468 61.277,60.008 ; U1108.4@64.453,57.468 64.453,60.008 ; U1109.4@67.627,57.468 67.627,59.372 ; U1110.4@98.742,57.468 98.742,59.372 ; D1100.3@100.627,55.598 v1(101.577,55.598) ; v1(102.87,57.15) 102.637,57.15 102.319,57.468 U1111.4@101.917,57.468 101.917,59.372 ; U1100.4@105.093,57.468 105.093,59.372 ; U1101.4@108.267,57.468 108.267,59.372 ; U1102.4@111.442,57.468 111.442,59.372 ; U1103.4@114.617,57.468 114.617,59.372 ; U1104.4@117.792,57.468 117.792,59.372 ; U1105.4@120.968,57.468 120.968,58.737 120.332,59.372 117.792,59.372 ; 42.862,60.008 45.72,60.008 ; 45.72,60.008 48.578,60.008 ; 48.578,60.008 51.752,60.008 ; 51.752,60.008 54.927,60.008 ; 54.927,60.008 58.102,60.008 ; 58.102,60.008 61.277,60.008 ; 61.277,60.008 64.453,60.008 ; 64.453,60.008 66.675,60.008 67.31,59.372 67.627,59.372 ; 67.627,59.372 68.263,59.372 68.611,59.721 68.611,62.831 69.597,63.817 74.93,63.817 77.153,61.595 79.534,61.595 80.486,62.547 95.567,62.547 98.742,59.372 ; 98.742,59.372 101.917,59.372 ; 101.917,59.372 105.093,59.372 ; 105.093,59.372 108.267,59.372 ; 108.267,59.372 111.442,59.372 ; 111.442,59.372 114.617,59.372 ; 114.617,59.372 117.792,59.372
  Bottom w0.152: v1(101.577,55.598) 102.87,56.89 v1(102.87,57.15)
NetIC801_1_7: IC801_1.7 R801_1.1 | length 3.6
  Top w0.152: IC801_1.7@150.812,45.719 150.812,44.867 151.053,44.627 151.061,44.627 151.447,44.24 151.447,43.476 151.859,43.065 R801_1.1@151.859,42.513
NetIC801_2_7: IC801_2.7 R801_2.1 | length 3.8
  Top w0.152: IC801_2.7@97.77,45.98 97.77,45.53 98.51,44.79 98.51,43.244 98.657,43.097 R801_2.1@98.657,42.545
NetIC900_5: IC900.5 R903.1 R904.2 TR900.1 TR900.2
NetIC900_8: IC900.8 R902.1 | length 1.7
  Top w0.406: IC900.8@18.794,86.677 18.985,86.677 19.368,87.06 R902.1@20.32,87.06
NetIC1400_1_57: IC1400_1.57 R1402_1.2 | length 2.8
  Top w0.152: R1402_1.2@135.496,58.138 135.496,57.686 135.958,57.224 IC1400_1.57@135.958,55.547
NetIC1400_2_57: IC1400_2.57 R1402_2.2 | length 2.8
  Top w0.152: R1402_2.2@81.915,58.088 81.915,57.636 82.618,56.933 IC1400_2.57@82.618,55.547
NetLD1400_1_1: LD1400_1.1 R1403_1.2 | length 1.3
  Top w0.152: R1403_1.2@136.48,63.818 137.278,63.818 LD1400_1.1@137.73,63.817
NetLD1400_2_1: LD1400_2.1 R1403_2.2 | length 1.3
  Top w0.152: R1403_2.2@82.774,63.817 LD1400_2.1@84.072,63.817
NetQ600_1_2: Q600_1.2 R605_1.2 R606_1.2 | length 3.1
  Top w0.152: Q600_1.2@106.087,44.132 107.066,44.132 107.315,44.381 R606_1.2@107.315,44.832 R605_1.2@108.585,44.832
NetQ600_1_6: Q600_1.6 Q600_1.7 R608_1.1 | length 2.8
  Top w0.152: Q600_1.6@104.097,43.482 104.549,43.482 104.491,43.541 104.491,43.642 Q600_1.7@105.092,43.642 105.092,43.032 104.84,42.779 R608_1.1@104.84,42.227
NetQ600_2_2: Q600_2.2 R605_2.2 R606_2.2 | length 3.1
  Top w0.152: Q600_2.2@51.477,43.815 52.456,43.815 52.705,44.063 R606_2.2@52.705,44.515 R605_2.2@53.975,44.515
NetQ600_2_6: Q600_2.6 Q600_2.7 R608_2.1 | length 2.9
  Top w0.152: R608_2.1@49.595,41.593 49.595,42.545 49.487,42.653 Q600_2.6@49.487,43.165 49.939,43.165 49.881,43.223 49.881,43.325 Q600_2.7@50.482,43.325
NetR108_1_1: R108_1.1 R110_1.2 U100_1.1 U100_1.4 | length 12.5
  Top w0.152: v1(102.552,19.526) 102.569,19.509 102.927,19.509 103.349,19.931 U100_1.4@103.349,20.231 103.911,20.231 104.14,20.002 104.14,19.367 104.549,18.959 R110_1.2@104.549,18.347 ; R108_1.1@104.234,24.606 104.234,24.506 105.249,23.491 U100_1.1@105.249,22.631 105.249,22.331 105.831,21.749 v1(106.204,21.749)
  Signals2 w0.152: v1(102.552,19.526) 104.775,21.749 v1(106.204,21.749)
NetR108_2_1: R108_2.1 R110_2.2 U100_2.1 U100_2.4 | length 12.5
  Top w0.152: v1@74.075,20.479 v1(73.977,20.479) 74.225,20.231 U100_2.4@74.774,20.231 75.336,20.231 75.565,20.002 75.565,19.459 75.974,19.05 R110_2.2@75.974,18.256 ; R108_2.1@75.659,24.606 75.659,24.506 76.674,23.491 U100_2.1@76.674,22.631 77.381,22.631 v1(77.629,22.384)
  Signals2 w0.152: v1(73.977,20.479) 73.977,21.907 74.454,22.384 v1(77.629,22.384)
NetR109_1_1: R109_1.1 R111_1.2 U101_1.1 U101_1.4 | length 8
  Top w0.152: R109_1.1@25.017,66.04 25.017,65.488 24.748,65.219 24.748,64.554 25.17,64.133 U101_1.1@25.47,64.133 26.514,64.133 27.87,62.776 U101_1.4@27.87,62.233 29.288,62.233 29.293,62.238 R111_1.2@29.845,62.238
NetR109_2_1: R109_2.1 R111_2.2 U101_2.1 U101_2.4 | length 10
  Top w0.152: R111_2.2@23.748,53.657 23.748,55.012 24.066,55.331 24.066,56.178 24.718,56.83 U101_2.1@25.17,56.83 ; R109_2.1@24.997,58.725 24.997,58.173 24.748,57.924 24.748,57.252 U101_2.1@25.17,56.83 ; U101_2.4@27.87,54.93 27.87,55.382 26.843,56.408 26.192,56.408 25.77,56.83 U101_2.1@25.47,56.83 U101_2.1@25.17,56.83
NetR708_1_2: R708_1.2 U700_1.3 | length 1.7
  Top w0.152: U700_1.3@87.305,16.488 88.007,16.488 88.237,16.257 R708_1.2@88.9,16.257
NetR708_2_2: R708_2.2 U700_2.3 | length 1.7
  Top w0.152: U700_2.3@57.936,17.281 58.638,17.281 58.868,17.051 R708_2.2@59.531,17.051
NetR1100_2: R1100.2 U1100.1 | length 2.1
  Top w0.152: U1100.1@105.093,63.817 105.093,65.11 105.628,65.645 R1100.2@105.727,65.645
NetR1101_2: R1101.2 U1101.1 | length 1.8
  Top w0.152: U1101.1@108.267,63.817 R1101.2@108.267,65.645
NetR1102_2: R1102.2 U1102.1 | length 20.1
  Top w0.152: U1102.1@111.442,63.817 111.442,64.794 113.323,66.675 128.935,66.675 129.44,67.18 R1102.2@129.54,67.18
NetR1103_2: R1103.2 U1103.1 | length 23
  Top w0.152: U1103.1@114.617,63.817 114.617,64.942 115.715,66.04 130.81,66.04 131.127,66.358 134.884,66.358 135.255,66.728 R1103.2@135.255,67.18
NetR1104_2: R1104.2 U1104.1 | length 25.4
  Top w0.152: U1104.1@117.792,63.817 117.792,64.794 118.416,65.418 131.127,65.418 131.432,65.722 139.964,65.722 140.97,66.728 R1104.2@140.97,67.18
NetR1105_2: R1105.2 U1105.1 | length 27.4
  Top w0.152: U1105.1@120.968,63.817 121.602,63.817 122.555,64.77 131.445,64.77 131.75,65.075 145.108,65.075 146.685,66.652 R1105.2@146.685,67.18
NetR1106_2: R1106.2 U1106.1 | length 28
  Top w0.152: U1106.1@58.102,63.817 58.102,65.272 58.226,65.396 59.505,66.675 76.137,66.675 76.455,66.992 82.459,66.992 82.646,67.18 R1106.2@83.82,67.18
NetR1107_2: R1107.2 U1107.1 | length 30.8
  Top w0.152: U1107.1@61.277,63.817 61.277,65.405 61.912,66.04 76.595,66.04 76.913,66.358 89.164,66.358 89.535,66.728 R1107.2@89.535,67.18
NetR1108_2: R1108.2 U1108.1 | length 33.4
  Top w0.152: U1108.1@64.453,63.817 64.453,64.794 65.076,65.418 77.055,65.418 77.36,65.722 94.895,65.722 95.25,66.078 R1108.2@95.25,67.18
NetR1109_2: R1109.2 U1109.1 | length 33
  Top w0.152: U1109.1@67.627,63.817 68.029,63.817 68.982,64.77 77.538,64.77 77.879,65.111 96.074,65.111 98.143,67.18 R1109.2@99.235,67.18
NetR1110_2: R1110.2 U1110.1 | length 3.4
  Top w0.152: U1110.1@98.742,63.817 98.742,65.087 99.313,65.658 R1110.2@100.642,65.658
NetR1111_2: R1111.2 U1111.1 | length 2.7
  Top w0.152: U1111.1@101.917,63.817 101.917,64.794 101.917,64.927 102.636,65.645 R1111.2@103.188,65.645
NetR1112_2: R1112.2 U1112.1 | length 1.8
  Top w0.152: U1112.1@39.052,63.817 R1112.2@39.052,65.658
NetR1113_2: R1113.2 U1113.1 | length 1.8
  Top w0.152: U1113.1@42.227,63.817 R1113.2@42.227,65.658
NetR1114_2: R1114.2 U1114.1 | length 1.8
  Top w0.152: U1114.1@45.402,63.817 R1114.2@45.402,65.645
NetR1115_2: R1115.2 U1115.1 | length 1.8
  Top w0.152: U1115.1@48.578,63.817 R1115.2@48.578,65.658
NetR1116_2: R1116.2 U1116.1 | length 1.8
  Top w0.152: U1116.1@51.752,63.817 R1116.2@51.752,65.658
NetR1117_2: R1117.2 U1117.1 | length 1.8
  Top w0.152: U1117.1@54.927,63.817 R1117.2@54.927,65.658
NetR1512_1: R1512.1 T1500.1 | length 2.2
  Top w0.152: R1512.1@115.57,71.185 116.545,71.185 117.16,70.57 T1500.1@117.16,70.17
NetR1513_1: R1513.1 T1501.1 | length 2.3
  Top w0.152: R1513.1@121.265,71.185 122.26,71.185 122.875,70.57 T1501.1@122.875,70.17
NetR1514_1: R1514.1 T1502.1 | length 2.3
  Top w0.152: R1514.1@126.982,71.185 127.975,71.185 128.59,70.57 T1502.1@128.59,70.17
NetR1515_1: R1515.1 T1503.1 | length 2.3
  Top w0.152: R1515.1@132.715,71.185 133.752,71.185 133.946,70.991 133.946,70.942 134.317,70.57 T1503.1@134.317,70.17
NetR1516_1: R1516.1 T1504.1 | length 2.2
  Top w0.152: R1516.1@138.458,71.185 139.405,71.185 140.02,70.57 T1504.1@140.02,70.17
NetR1517_1: R1517.1 T1505.1 | length 2.5
  Top w0.152: R1517.1@143.918,71.185 145.12,71.185 145.735,70.57 T1505.1@145.735,70.17
NetR1530_1: R1530.1 T1506.1 | length 2.2
  Top w0.152: R1530.1@81.28,71.185 82.255,71.185 82.87,70.57 T1506.1@82.87,70.17
NetR1531_1: R1531.1 T1507.1 | length 2.2
  Top w0.152: R1531.1@86.995,71.185 87.97,71.185 88.585,70.57 T1507.1@88.585,70.17
NetR1532_1: R1532.1 T1508.1 | length 2.2
  Top w0.152: R1532.1@92.71,71.185 93.685,71.185 94.3,70.57 T1508.1@94.3,70.17
NetR1533_1: R1533.1 T1509.1 | length 2.3
  Top w0.152: R1533.1@98.405,71.185 99.415,71.185 100.03,70.57 T1509.1@100.03,70.17
NetR1534_1: R1534.1 T1510.1 | length 2.2
  Top w0.152: R1534.1@104.14,71.185 105.095,71.185 105.71,70.57 T1510.1@105.71,70.17
NetR1535_1: R1535.1 T1511.1 | length 2.2
  Top w0.152: R1535.1@109.855,71.185 110.83,71.185 111.445,70.57 T1511.1@111.445,70.17
NetR1548_1: R1548.1 T1512.1 | length 2.2
  Top w0.152: R1548.1@46.99,71.185 47.965,71.185 48.58,70.57 T1512.1@48.58,70.17
NetR1549_1: R1549.1 T1513.1 | length 2.2
  Top w0.152: R1549.1@52.705,71.185 53.68,71.185 54.295,70.57 T1513.1@54.295,70.17
NetR1550_1: R1550.1 T1514.1 | length 2.2
  Top w0.152: R1550.1@58.42,71.185 59.395,71.185 60.01,70.57 T1514.1@60.01,70.17
NetR1551_1: R1551.1 T1515.1 | length 2.2
  Top w0.152: R1551.1@64.135,71.185 65.11,71.185 65.725,70.57 T1515.1@65.725,70.17
NetR1552_1: R1552.1 T1516.1 | length 2.2
  Top w0.152: R1552.1@69.85,71.185 70.825,71.185 71.44,70.57 T1516.1@71.44,70.17
NetR1553_1: R1553.1 T1517.1 | length 2.2
  Top w0.152: R1553.1@75.565,71.185 76.54,71.185 77.155,70.57 T1517.1@77.155,70.17
NetTR900_6: TR900.6 TR900.7
  other v1: 35.56,86.614 36.322,86.614
OPA_TEMP_1: IC100_1.8 R110_1.1 U100_1.3 | length 9.9
  Top w0.152: IC100_1.8@100.239,24.5 101.78,24.5 103.349,22.931 U100_1.3@103.349,22.631 103.349,21.746 104.457,20.637 104.457,19.526 104.775,19.209 105.638,19.209 105.949,18.898 R110_1.1@105.949,18.347
OPA_TEMP_2: IC100_2.8 R110_2.1 U100_2.3 | length 10
  Top w0.152: IC100_2.8@71.664,24.5 73.205,24.5 74.774,22.931 U100_2.3@74.774,22.631 74.774,21.746 75.882,20.637 75.882,19.526 76.2,19.209 76.994,19.209 77.374,18.829 R110_2.1@77.374,18.256
OPA_USER_1: IC101_1.8 IC104_1.8 R111_1.1 U101_1.3 | length 37.7
  Top w0.152: IC101_1.8@11.815,67.363 12.565,67.363 12.761,67.558 12.374,67.945 v1(12.065,67.945) ; v1@19.636,67.388 v1(19.621,67.373) 20.937,67.373 20.948,67.363 IC104_1.8@21.957,67.363 ; IC104_1.8@21.931,67.388 IC104_1.8@21.957,67.363 ; IC104_1.8@21.975,67.363 IC104_1.8@21.957,67.363 ; v1@23.187,61.903 v1(23.177,61.912) 23.498,62.233 U101_1.3@25.47,62.233 ; v1(28.575,63.182) 29.03,63.638 R111_1.1@29.845,63.638
  Signals2 w0.152: v1(12.065,67.945) 12.383,67.627 12.383,61.912 12.7,61.595 20.002,61.595 ; v1(19.621,67.373) 20.002,66.992 20.002,61.595 ; v1(28.575,63.182) 28.575,62.547 28.258,62.23 23.495,62.23 v1(23.177,61.912) 22.748,61.483 20.432,61.483 20.32,61.595 20.002,61.595
OPA_USER_2: IC101_2.8 IC104_2.8 R111_2.1 U101_2.3 | length 31.2
  Top w0.152: v1(11.43,60.518) 10.869,59.957 10.869,59.938 11.065,59.743 IC101_2.8@11.815,59.743 ; v1(21.749,60.373) 21.975,60.147 IC104_2.8@21.975,59.743 ; R111_2.1@25.148,53.657 24.696,53.657 24.447,53.906 v1(24.447,54.927) 24.45,54.93 U101_2.3@25.47,54.93
  Signals2 w0.152: v1(11.43,60.518) 11.43,55.096 12.724,53.802 13.512,53.802 14.003,54.292 21.273,54.292 ; v1(21.749,60.373) 21.638,60.373 21.273,60.008 21.273,54.292 ; v1(24.447,54.927) 23.812,54.292 21.273,54.292
OUT_N1_1: IC1400_1.63 R1418_1.2 TR1400_1.10 | length 124.4
  Top w0.254: R1418_1.2@35.625,29.21 35.625,29.11 35.996,28.739 36.081,28.739 36.954,27.866 TR1400_1.10@36.954,27.517 36.026,27.517 v1(36.005,27.495) ; IC1400_1.63@132.958,55.547 132.958,54.648 133.063,54.543 133.063,54.262 133.35,53.975 v1(133.35,53.34)
  Signals1 w0.254: v1@35.985,27.495 v1(36.005,27.495) 37.362,27.495 37.597,27.731 37.597,29.051 37.833,29.286 37.898,29.286 101.135,29.286 101.453,29.604 101.453,40.45 104.653,43.65 129.057,43.65 131.075,45.667 131.075,51.762 132.653,53.34 v1(133.35,53.34)
OUT_N1_2: IC1400_2.63 R1418_2.2 TR1400_2.10 | length 85.5
  Top w0.254: v1(19.75,30.48) R1418_2.2@19.75,29.21 19.75,29.11 20.161,28.699 20.161,27.826 20.47,27.517 TR1400_2.10@21.079,27.517 ; v1(79.618,53.692) IC1400_2.63@79.618,55.598
  Signals1 w0.254: v1(19.75,30.48) 23.698,30.48 24.587,31.369 47.879,31.369 48.532,32.022 48.532,42.332 49.85,43.65 76.67,43.65 78.461,45.441 78.461,52.535 v1(79.618,53.692)
OUT_P1_1: IC1400_1.64 R1418_1.1 TR1400_1.12 | length 123.6
  Top w0.254: TR1400_1.12@32.941,27.517 32.941,28.814 33.337,29.21 R1418_1.1@34.225,29.21 34.225,29.995 34.442,30.212 35.985,30.212 36.368,29.829 v1(36.38,29.829) ; v1(132.458,54.292) IC1400_1.64@132.458,55.547
  Signals1 w0.254: v1(36.38,29.829) 36.38,29.875 36.562,29.693 36.83,29.693 100.729,29.693 101.047,30.01 101.047,40.546 104.633,44.133 128.905,44.133 130.52,45.747 130.52,52.097 132.458,54.035 v1(132.458,54.292)
OUT_P1_2: IC1400_2.64 R1418_2.1 TR1400_2.12 | length 86.3
  Top w0.254: TR1400_2.12@17.066,27.517 17.066,28.655 17.621,29.21 R1418_2.1@18.35,29.21 v1(18.35,30.468) ; v1@78.762,54.043 v1(78.762,54.177) 79.117,54.533 IC1400_2.64@79.117,55.598
  Signals1 w0.254: v1(18.35,30.468) 18.496,30.468 19.114,31.085 20.703,31.085 21.749,32.131 47.808,32.131 48.126,32.449 48.126,42.428 49.703,44.005 76.391,44.005 78.105,45.72 78.105,53.52 v1(78.762,54.177)
PRIMARY-ANALOG-IN_0: IC104_1.4 X400.1 | length 27.6
  Top w0.152: v1(21.273,62.038) 20.637,62.673 20.637,64.175 21.225,64.763 IC104_1.4@21.975,64.763
  Bottom w0.152: v1(21.273,62.038) 21.08,62.038 20.955,61.912 20.955,54.61 21.273,54.292 25.399,54.292 25.559,54.133 25.559,44.276 26.041,43.803 X400.1@26.67,43.815
PRIMARY-ANALOG-IN_1: IC104_1.5 X400.2 | length 30.2
  Top w0.152: v1(20.784,65.248) 20.948,65.413 IC104_1.5@21.975,65.413
  Bottom w0.152: v1(20.784,65.248) 20.637,65.102 20.637,54.292 20.955,53.975 25.082,53.975 25.241,53.816 25.241,42.686 X400.2@26.67,41.275
PRIMARY-ANALOG-IN_2: IC104_1.6 X400.3 | length 27
  Top w0.152: v1(20.66,66.063) IC104_1.6@21.975,66.063 ; IC104_1.6@21.933,66.04 IC104_1.6@21.946,66.053
  Bottom w0.152: v1(20.66,66.063) 20.229,65.632 20.229,54.066 20.637,53.657 22.656,53.657 23.006,53.307 23.006,53.054 22.955,53.003 22.955,44.339 23.501,43.803 X400.3@24.13,43.815
PRIMARY-ANALOG-IN_3: IC104_1.7 X400.4 | length 30.4
  Top w0.152: v1(20.711,66.816) 20.809,66.816 20.827,66.834 20.948,66.713 IC104_1.7@21.975,66.713
  Bottom w0.152: v1(20.711,66.816) 20.497,66.816 20.479,66.834 19.975,66.33 19.975,53.685 20.32,53.34 22.541,53.34 22.701,53.18 22.701,44.516 22.65,44.465 22.65,44.212 22.701,44.161 22.701,42.686 X400.4@24.13,41.275
PRIMARY-ANALOG-IN_4: IC104_1.12 X400.5 | length 26.3
  Top w0.152: IC104_1.12@16.125,65.413 19.34,65.413 v1(19.345,65.418)
  Bottom w0.152: v1(19.345,65.418) 19.355,65.418 19.685,65.087 19.685,53.34 20.002,53.023 20.32,53.023 20.479,52.864 20.479,44.276 20.961,43.803 X400.5@21.59,43.815
PRIMARY-ANALOG-IN_5: IC104_1.11 X400.6 | length 28.7
  Top w0.152: IC104_1.11@16.125,66.063 18.697,66.063 v1(18.707,66.053)
  Bottom w0.152: v1(18.707,66.053) 18.707,64.941 19.367,64.281 19.367,53.023 19.685,52.705 20.002,52.705 20.161,52.546 20.161,42.686 X400.6@21.59,41.275
PRIMARY-ANALOG-IN_6: IC104_1.10 X400.7 | length 26.7
  Top w0.152: IC104_1.10@16.154,66.713 18.059,66.713 v1(18.098,66.675)
  Bottom w0.152: v1(18.098,66.675) 18.098,65.087 19.05,64.135 19.05,53.023 18.732,52.705 18.415,52.705 17.939,52.229 17.939,44.276 18.421,43.803 X400.7@19.05,43.815
PRIMARY-ANALOG-IN_7: IC104_1.9 X400.8 | length 29.2
  Top w0.152: IC104_1.9@16.125,67.363 17.41,67.363 v1(17.462,67.31)
  Bottom w0.152: v1(17.462,67.31) 17.462,65.234 18.732,63.964 18.732,53.34 18.415,53.023 18.098,53.023 17.621,52.546 17.621,42.686 X400.8@19.05,41.275
PRIMARY-ANALOG-IN_8: IC101_1.4 X400.9 | length 26.3
  Top w0.152: v1(11.112,62.038) 11.112,62.23 10.636,62.706 10.636,64.589 10.788,64.741 10.788,64.763 IC101_1.4@11.815,64.763
  Bottom w0.152: v1(11.112,62.038) 10.92,62.038 10.795,61.912 10.795,54.61 11.112,54.292 12.233,54.292 12.724,53.802 13.451,53.802 15.399,51.854 15.399,44.276 15.881,43.803 X400.9@16.51,43.815
PRIMARY-ANALOG-IN_9: IC101_1.5 X400.10 | length 29.1
  Top w0.152: v1(10.636,65.405) 10.781,65.405 10.788,65.413 IC101_1.5@11.815,65.413
  Bottom w0.152: v1(10.636,65.405) 10.477,65.246 10.477,54.292 10.795,53.975 12.192,53.975 12.619,53.548 13.346,53.548 15.081,51.813 15.081,42.686 X400.10@16.51,41.275
PRIMARY-ANALOG-IN_10: IC101_1.6 X400.11 | length 26.3
  Top w0.152: v1(10.477,66.244) 10.659,66.063 IC101_1.6@11.815,66.063
  Bottom w0.152: v1(10.477,66.244) 10.477,66.04 10.082,65.644 10.082,54.053 10.477,53.657 11.056,53.657 12.859,51.854 12.859,44.276 13.341,43.803 X400.11@13.97,43.815
PRIMARY-ANALOG-IN_11: IC101_1.7 X400.12 | length 30.4
  Top w0.152: v1(9.842,67.373) 10.132,67.373 10.793,66.713 IC101_1.7@11.815,66.713
  Bottom w0.152: v1(9.842,67.373) 9.828,67.359 9.828,53.948 10.736,53.04 11.314,53.04 12.541,51.813 12.541,42.686 X400.12@13.97,41.275
PRIMARY-ANALOG-IN_12: IC101_1.12 X400.13 | length 26.1
  Top w0.152: IC101_1.12@5.965,65.413 9.19,65.413 9.195,65.418 v1(9.207,65.405)
  Bottom w0.152: v1(9.207,65.405) 9.525,65.087 9.525,53.382 10.377,52.53 10.377,44.219 10.801,43.803 X400.13@11.43,43.815
PRIMARY-ANALOG-IN_13: IC101_1.11 X400.14 | length 28.6
  Top w0.152: IC101_1.11@5.965,66.063 6.992,66.063 7.001,66.053 8.502,66.053 v1(8.509,66.06)
  Bottom w0.152: v1(8.509,66.06) 8.509,65.319 9.207,64.621 9.207,53.34 10.123,52.424 10.123,44.396 10.072,44.345 10.072,44.093 10.123,44.042 10.123,42.565 X400.14@11.43,41.275
PRIMARY-ANALOG-IN_14: IC101_1.10 X400.15 | length 26.3
  Top w0.152: IC101_1.10@5.965,66.713 6.992,66.713 ; 6.992,66.713 v1(7.936,66.713)
  Bottom w0.152: v1(7.936,66.713) 7.936,65.086 8.569,64.453 8.572,64.453 8.89,64.135 8.89,53.34 7.657,52.107 7.657,45.048 X400.15@8.89,43.815
PRIMARY-ANALOG-IN_15: IC101_1.9 X400.16 | length 29.1
  Top w0.152: IC101_1.9@5.965,67.363 6.992,67.363 7.003,67.373 v1(7.306,67.373)
  Bottom w0.152: v1(7.306,67.373) 7.306,65.084 8.572,63.817 8.572,53.617 7.403,52.447 7.403,42.762 X400.16@8.89,41.275
PRIMARY-C0: C1311_1.2 IC1400_1.38 R1306_1.2 Z1305_1.2 | length 28.5
  Top w0.152: IC1400_1.38@141.908,48.597 143.54,48.597 143.598,48.656 144.087,48.656 144.382,48.361 144.382,43.937 144.695,43.624 148.211,43.624 149.285,42.55 150.363,42.55 151.511,41.402 152.146,41.402 152.49,41.058 C1311_1.2@152.49,40.322 ; IC1400_1.38@141.958,48.598 IC1400_1.38@142.016,48.656
  Top w0.254: R1306_1.2@151.745,30.583 151.745,33.643 152.062,33.96 153.015,33.96 153.38,34.325 153.38,38.358 152.49,39.247 C1311_1.2@152.49,40.322
PRIMARY-C1: C1305_1.1 C1310_1.2 C1311_1.1 IC1400_1.36 R1305_1.2 Z1304_1.2 Z1305_1.1 | length 25.6
  Top w0.152: IC1400_1.36@141.958,47.598 143.379,47.598 144.128,46.848 144.128,43.832 144.589,43.37 148.106,43.37 148.734,42.743 148.734,42.635 149.472,41.898 C1310_1.2@149.93,41.898
  Top w0.254: R1305_1.2@149.205,30.533 149.205,33.039 149.898,33.733 C1305_1.1@150.475,33.733 150.475,34.471 150.11,34.836 Z1305_1.1@150.11,35.548 150.11,36.453 150.84,37.183 150.84,37.376 Z1304_1.2@150.84,38.088 150.84,39.236 151.04,39.436 C1311_1.1@151.04,40.322 151.04,41.42 150.563,41.898 C1310_1.2@150.07,41.898
PRIMARY-C2: C1304_1.1 C1309_1.2 C1310_1.1 IC1400_1.34 R1304_1.2 Z1303_1.2 Z1304_1.1 | length 23.4
  Top w0.152: IC1400_1.34@141.908,46.597 142.709,46.597 143.874,45.433 143.874,43.727 144.484,43.116 148.001,43.116 148.48,42.637 C1310_1.1@148.48,41.898
  Top w0.254: R1304_1.2@146.665,30.533 146.665,33.039 147.358,33.733 C1304_1.1@147.935,33.733 147.935,34.471 148.3,34.836 Z1303_1.2@148.3,35.548 148.3,36.453 147.57,37.183 Z1304_1.1@147.57,38.088 147.57,39.236 147.41,39.396 C1309_1.2@147.41,40.322 147.41,41.46 147.848,41.898 C1310_1.1@148.34,41.898
PRIMARY-C3: C1303_1.1 C1308_1.2 C1309_1.1 IC1400_1.32 R1303_1.2 Z1302_1.2 Z1303_1.1 | length 20
  Top w0.152: IC1400_1.32@139.958,44.147 142.225,44.147 143.51,42.862 144.85,42.862 C1308_1.2@144.85,41.898
  Top w0.254: R1303_1.2@144.125,30.533 144.125,33.039 144.818,33.733 C1303_1.1@145.395,33.733 145.395,34.471 145.03,34.836 Z1303_1.1@145.03,35.548 145.03,36.453 145.76,37.183 Z1302_1.2@145.76,38.088 145.76,39.236 145.96,39.436 C1309_1.1@145.96,40.322 145.96,41.42 145.483,41.898 C1308_1.2@144.85,41.898
PRIMARY-C4: C1302_1.1 C1307_1.2 C1308_1.1 IC1400_1.30 R1302_1.2 Z1301_1.2 Z1302_1.1 | length 19.2
  Top w0.152: IC1400_1.30@138.958,43.497 IC1400_1.30@138.958,44.097 ; IC1400_1.30@138.958,44.147 138.958,43.346 139.441,42.862 140.653,42.862 141.617,41.898 142.768,41.898
  Top w0.254: R1302_1.2@141.585,30.533 141.585,33.039 142.278,33.733 C1302_1.1@142.855,33.733 142.855,34.471 143.22,34.836 Z1301_1.2@143.22,35.548 143.22,36.453 142.49,37.183 Z1302_1.1@142.49,38.088 142.49,39.236 142.342,39.383 C1307_1.2@142.342,40.322 142.342,41.472 142.768,41.898 C1308_1.1@143.26,41.898
PRIMARY-C5: C1301_1.1 C1306_1.2 C1307_1.1 IC1400_1.28 R1301_1.2 Z1300_1.2 Z1301_1.1 | length 16.9
  Top w0.152: IC1400_1.28@137.958,44.097 137.958,43.18 138.275,42.862 138.905,42.862 139.77,41.998 C1306_1.2@139.77,41.898
  Top w0.254: R1301_1.2@139.045,30.533 139.045,33.039 139.738,33.733 C1301_1.1@140.315,33.733 140.315,34.471 139.95,34.836 Z1301_1.1@139.95,35.548 139.95,36.453 140.68,37.183 Z1300_1.2@140.68,38.088 140.68,39.236 140.892,39.448 C1307_1.1@140.892,40.322 140.892,41.353 140.347,41.898 C1306_1.2@139.77,41.898
PRIMARY-C6: C1300_1.1 C1306_1.1 C1323_1.2 IC1400_1.26 R1300_1.2 Z1300_1.1 Z1311_1.2 | length 16.1
  Top w0.152: IC1400_1.26@136.958,44.097 136.958,42.545 137.605,41.898 137.688,41.898
  Top w0.254: R1300_1.2@136.505,30.533 136.505,33.039 137.198,33.733 C1300_1.1@137.775,33.733 137.775,34.471 138.14,34.836 Z1311_1.2@138.14,35.548 138.14,36.453 137.41,37.183 Z1300_1.1@137.41,38.088 137.41,39.236 137.25,39.396 C1323_1.2@137.25,40.322 137.25,41.46 137.688,41.898 C1306_1.1@138.32,41.898
PRIMARY-C7: C1317_1.1 C1322_1.2 C1323_1.1 IC1400_1.24 R1312_1.2 Z1310_1.2 Z1311_1.1 | length 16.1
  Top w0.152: 135.323,41.898 135.323,41.91 135.958,42.545 IC1400_1.24@135.958,44.097
  Top w0.254: R1312_1.2@133.965,30.533 133.965,33.039 134.658,33.733 C1317_1.1@135.235,33.733 135.235,34.471 134.87,34.836 Z1311_1.1@134.87,35.548 134.87,36.453 135.6,37.183 135.6,37.376 Z1310_1.2@135.6,38.088 135.6,39.236 135.8,39.436 C1323_1.1@135.8,40.322 135.8,41.42 135.323,41.898 C1322_1.2@134.69,41.898
PRIMARY-C8: C1316_1.1 C1321_1.2 C1322_1.1 IC1400_1.22 R1311_1.2 Z1309_1.2 Z1310_1.1 | length 16.7
  Top w0.152: C1322_1.1@133.338,41.898 134.302,42.862 134.64,42.862 134.958,43.18 IC1400_1.22@134.958,44.097
  Top w0.254: R1311_1.2@131.425,30.533 131.425,33.039 132.118,33.733 C1316_1.1@132.695,33.733 132.695,34.471 133.06,34.836 Z1309_1.2@133.06,35.548 133.06,36.453 132.33,37.183 Z1310_1.1@132.33,38.088 132.33,39.236 132.17,39.396 C1321_1.2@132.17,40.322 132.17,41.46 132.608,41.898 C1322_1.1@133.24,41.898 C1322_1.1@133.338,41.898
PRIMARY-C9: C1315_1.1 C1320_1.2 C1321_1.1 IC1400_1.20 R1310_1.2 Z1308_1.2 Z1309_1.1 | length 19.4
  Top w0.152: C1320_1.2@129.61,41.898 129.61,41.998 130.163,42.55 133.328,42.55 133.958,43.18 IC1400_1.20@133.958,44.097
  Top w0.254: R1310_1.2@128.885,30.533 128.885,33.039 129.578,33.733 C1315_1.1@130.155,33.733 130.155,34.471 129.79,34.836 Z1309_1.1@129.79,35.548 129.79,36.453 130.52,37.183 Z1308_1.2@130.52,38.088 130.52,39.236 130.72,39.436 C1321_1.1@130.72,40.322 130.72,41.365 130.187,41.898 C1320_1.2@129.61,41.898
PRIMARY-C10: C1314_1.1 C1319_1.2 C1320_1.1 IC1400_1.18 R1309_1.2 Z1307_1.2 Z1308_1.1 | length 20.6
  Top w0.152: C1320_1.1@128.16,41.898 128.16,41.998 128.713,42.55 129.804,42.55 130.116,42.862 132.715,42.862 132.958,43.105 IC1400_1.18@132.958,44.147 ; IC1400_1.18@132.958,43.497 IC1400_1.18@132.958,44.097
  Top w0.254: R1309_1.2@126.345,30.533 126.345,33.039 127.038,33.733 C1314_1.1@127.615,33.733 127.615,34.471 127.98,34.836 Z1307_1.2@127.98,35.548 127.98,36.453 127.25,37.183 Z1308_1.1@127.25,38.088 127.25,39.236 127.09,39.396 C1319_1.2@127.09,40.322 127.09,41.46 127.528,41.898 C1320_1.1@128.16,41.898
PRIMARY-C11: C1313_1.1 C1318_1.2 C1319_1.1 IC1400_1.16 R1308_1.2 Z1306_1.2 Z1307_1.1 | length 22.8
  Top w0.152: C1318_1.2@124.53,41.898 124.53,41.998 125.083,42.55 127.958,42.55 128.27,42.862 129.61,42.862 130.508,43.76 IC1400_1.16@130.508,46.097
  Top w0.254: R1308_1.2@123.805,30.468 R1308_1.2@123.805,30.533 123.805,33.039 124.498,33.733 C1313_1.1@125.075,33.733 125.075,34.471 124.71,34.836 Z1307_1.1@124.71,35.548 124.71,36.453 125.44,37.183 125.44,37.376 Z1306_1.2@125.44,38.088 125.44,39.236 125.64,39.436 C1319_1.1@125.64,40.322 125.64,41.42 125.163,41.898 C1318_1.2@124.53,41.898
PRIMARY-C12: C1312_1.1 C1318_1.1 C1335_1.2 IC1400_1.14 R1307_1.2 Z1306_1.1 Z1317_1.2 | length 25.1
  Top w0.152: C1318_1.1@123.08,41.898 123.08,41.998 123.633,42.55 124.46,42.55 124.772,42.862 127.635,42.862 127.953,43.18 129.222,43.18 129.54,43.497 129.54,46.972 129.665,47.097 IC1400_1.14@130.457,47.097
  Top w0.254: R1307_1.2@121.265,30.533 121.265,33.032 121.978,33.745 C1312_1.1@122.555,33.745 122.555,34.29 122.92,34.655 Z1317_1.2@122.92,35.56 122.92,36.465 122.17,37.215 122.17,37.376 Z1306_1.1@122.17,38.088 122.17,38.799 122.01,38.959 C1335_1.2@122.01,40.322 122.01,41.503 122.405,41.898 C1318_1.1@122.94,41.898
PRIMARY-C13: C1329_1.1 C1334_1.2 C1335_1.1 IC1400_1.12 R1318_1.2 Z1316_1.2 Z1317_1.1 | length 29.2
  Top w0.152: C1334_1.2@119.47,41.91 119.47,42.01 120.01,42.55 123.19,42.55 123.502,42.862 124.142,42.862 124.46,43.18 127.317,43.18 127.635,43.497 128.905,43.497 129.222,43.815 129.222,47.601 129.719,48.097 IC1400_1.12@130.457,48.097
  Top w0.254: R1318_1.2@118.745,30.468 R1318_1.2@118.745,30.545 118.745,33.052 119.438,33.745 C1329_1.1@120.015,33.745 ; C1334_1.2@119.61,41.91 120.015,41.91 120.56,41.365 C1335_1.1@120.56,40.322 120.56,39.428 120.36,39.228 Z1316_1.2@120.36,38.1 120.36,37.215 120.38,37.195 119.65,36.465 119.65,34.655 120.015,34.29 C1329_1.1@120.015,33.885
PRIMARY-C14: C1328_1.1 C1333_1.2 C1334_1.1 IC1400_1.10 R1317_1.2 Z1315_1.2 Z1316_1.1 | length 31.2
  Top w0.152: C1334_1.1@118.02,41.91 118.02,42.01 118.573,42.563 119.38,42.563 119.68,42.862 122.872,42.862 123.19,43.18 123.825,43.18 124.142,43.497 127,43.497 127.317,43.815 128.588,43.815 128.905,44.133 128.905,47.716 129.54,48.351 129.54,48.941 129.696,49.097 IC1400_1.10@130.457,49.097
  Top w0.254: R1317_1.2@116.205,30.468 R1317_1.2@116.205,30.545 116.205,33.052 116.898,33.745 C1328_1.1@117.475,33.745 ; C1328_1.1@117.475,33.885 117.475,34.29 117.84,34.655 117.84,36.465 117.09,37.215 Z1316_1.1@117.09,38.1 117.09,38.812 116.93,38.972 C1333_1.2@116.93,40.322 116.93,41.365 117.475,41.91 C1334_1.1@117.88,41.91
PRIMARY-C15: C1327_1.1 C1332_1.2 C1333_1.1 IC1400_1.8 R1316_1.2 Z1314_1.2 Z1315_1.1 | length 35.5
  Top w0.152: C1332_1.2@114.39,41.91 114.39,42.01 114.925,42.545 117.475,42.545 117.792,42.862 119.062,42.862 119.38,43.18 122.555,43.18 122.872,43.497 123.502,43.497 123.82,43.815 126.682,43.815 127,44.133 128.27,44.133 128.588,44.45 128.588,47.879 129.286,48.578 129.286,49.678 129.706,50.097 IC1400_1.8@130.508,50.097
  Top w0.254: R1316_1.2@113.665,30.468 R1316_1.2@113.665,30.545 113.665,33.052 114.358,33.745 C1327_1.1@114.935,33.745 ; C1332_1.2@114.53,41.91 114.935,41.91 115.48,41.365 C1333_1.1@115.48,40.322 115.48,39.428 115.3,39.248 Z1314_1.2@115.3,38.1 115.3,37.388 115.3,37.195 114.57,36.465 114.57,34.655 114.935,34.29 C1327_1.1@114.935,33.885
PRIMARY-C16: C1326_1.1 C1331_1.2 C1332_1.1 IC1400_1.6 R1315_1.2 Z1313_1.2 Z1314_1.1 | length 37.6
  Top w0.152: C1332_1.1@112.94,41.91 112.94,42.01 113.475,42.545 114.033,42.545 114.351,42.862 117.157,42.862 117.475,43.18 118.745,43.18 119.062,43.497 122.237,43.497 122.555,43.815 123.19,43.815 123.507,44.133 126.365,44.133 126.682,44.45 127.953,44.45 128.27,44.767 128.27,48.006 129.032,48.768 129.032,50.424 129.706,51.097 IC1400_1.6@130.508,51.097
  Top w0.254: R1315_1.2@111.125,30.468 R1315_1.2@111.125,30.545 111.125,33.052 111.818,33.745 C1326_1.1@112.395,33.745 ; C1326_1.1@112.395,33.885 112.395,34.29 112.76,34.655 112.76,36.465 112.03,37.195 Z1314_1.1@112.03,38.1 112.03,39.248 111.85,39.428 C1331_1.2@111.85,40.322 111.85,41.365 112.395,41.91 C1332_1.1@112.8,41.91
PRIMARY-C17: C1325_1.1 C1330_1.2 C1331_1.1 IC1400_1.4 R1314_1.2 Z1312_1.2 Z1313_1.1 | length 41.9
  Top w0.152: C1330_1.2@109.31,41.91 109.31,42.01 109.845,42.545 112.395,42.545 112.712,42.862 113.665,42.862 113.983,43.18 116.84,43.18 117.157,43.497 118.427,43.497 118.745,43.815 121.92,43.815 122.237,44.133 122.872,44.133 123.19,44.45 126.047,44.45 126.365,44.767 127.635,44.767 127.953,45.085 127.953,48.048 128.778,48.873 128.778,51.17 129.706,52.097 IC1400_1.4@130.508,52.097
  Top w0.254: R1314_1.2@108.585,30.468 R1314_1.2@108.585,30.545 108.585,33.052 109.278,33.745 C1325_1.1@109.855,33.745 ; C1330_1.2@109.45,41.91 109.855,41.91 110.4,41.365 C1331_1.1@110.4,40.322 110.4,39.428 110.22,39.248 Z1312_1.2@110.22,38.1 110.22,37.388 110.22,37.195 109.49,36.465 109.49,34.655 109.855,34.29 C1325_1.1@109.855,33.885
PRIMARY-C18: C1324_1.1 C1330_1.1 IC1400_1.2 R1313_1.2 Z1312_1.1 | length 43.8
  Top w0.152: C1330_1.1@107.86,41.91 107.86,42.01 108.395,42.545 108.902,42.545 109.22,42.862 112.078,42.862 112.395,43.18 113.347,43.18 113.665,43.497 116.522,43.497 116.84,43.815 118.11,43.815 118.427,44.133 121.602,44.133 121.92,44.45 122.555,44.45 122.872,44.767 125.412,44.767 125.73,45.085 127.317,45.085 127.635,45.402 127.635,48.26 128.478,49.103 128.478,52.786 128.789,53.097 IC1400_1.2@130.508,53.097
  Top w0.254: R1313_1.2@106.045,30.545 106.045,33.052 106.738,33.745 C1324_1.1@107.315,33.745 ; C1324_1.1@107.315,33.885 107.315,36.465 106.95,36.83 Z1312_1.1@106.95,38.1 106.95,38.812 107.86,39.722 C1330_1.1@107.86,41.91
PRIMARY-DIGITAL-IO_0: R700_1.1 U700_1.4 X402.1 | length 76.6
  Top w0.152: X402.1@41.91,43.815 41.91,43.497 43.18,42.227 43.18,40.64 43.497,40.322 47.942,40.322 50.482,37.782 50.482,29.674 52.401,27.755 55.714,27.755 56.005,27.464 90.851,27.464 91.196,27.119 91.196,22.332 91.367,22.161 R700_1.1@91.99,22.161 91.99,21.61 91.494,21.114 89.376,21.114 89.059,20.796 89.059,17.78 88.416,17.138 U700_1.4@87.305,17.138
PRIMARY-DIGITAL-IO_1: R701_1.1 U700_1.5 X402.2 | length 70.7
  Top w0.152: X402.2@41.91,41.275 43.18,40.005 47.625,40.005 50.165,37.465 50.165,29.632 52.302,27.495 55.614,27.495 55.9,27.21 89.313,27.21 89.609,26.914 89.609,22.258 89.706,22.161 R701_1.1@90.402,22.161 90.402,21.664 90.116,21.378 89.005,21.378 88.741,21.114 88.741,18.098 88.431,17.788 U700_1.5@87.305,17.788
PRIMARY-DIGITAL-IO_2: R702_1.1 U700_1.6 X402.3 | length 71.8
  Top w0.152: X402.3@39.37,43.815 40.64,42.545 40.64,40.005 40.957,39.688 47.307,39.688 49.847,37.148 49.847,29.515 52.121,27.241 55.509,27.241 55.795,26.956 87.82,26.956 88.021,26.755 88.021,22.332 88.192,22.161 R702_1.1@88.815,22.161 88.815,21.664 88.424,21.273 88.424,18.732 88.129,18.438 U700_1.6@87.305,18.438
PRIMARY-DIGITAL-IO_3: R703_1.1 U700_1.7 X402.4 | length 67.5
  Top w0.152: X402.4@39.37,41.275 39.37,39.688 39.688,39.37 46.99,39.37 49.53,36.83 49.53,29.355 51.897,26.987 55.404,26.987 55.689,26.702 86.217,26.702 86.434,26.485 86.434,22.332 86.605,22.161 R703_1.1@87.227,22.161 87.227,21.378 88.106,20.499 88.106,19.489 87.705,19.088 U700_1.7@87.305,19.088
PRIMARY-DIGITAL-IO_4: R704_1.1 U700_1.9 X402.5 | length 72
  Top w0.152: X402.5@36.83,43.815 36.83,43.497 38.1,42.227 38.1,39.37 38.417,39.052 46.672,39.052 49.212,36.512 49.212,29.196 51.7,26.709 55.323,26.709 55.584,26.448 84.677,26.448 84.846,26.279 84.846,22.332 85.017,22.161 R704_1.1@85.64,22.161 85.64,20.87 84.508,19.738 U700_1.9@81.605,19.738
PRIMARY-DIGITAL-IO_5: R705_1.1 U700_1.10 X402.6 | length 69.8
  Top w0.152: X402.6@36.83,41.275 36.83,39.052 37.148,38.735 46.355,38.735 48.895,36.195 48.895,29.039 51.479,26.455 55.218,26.455 55.479,26.194 83.113,26.194 83.259,26.048 83.259,22.332 83.43,22.161 R705_1.1@84.052,22.161 84.052,20.87 83.82,20.637 80.962,20.637 80.645,20.32 80.645,19.346 80.903,19.088 U700_1.10@81.605,19.088
PRIMARY-DIGITAL-IO_6: R706_1.1 U700_1.11 X402.7 | length 71.9
  Top w0.152: X402.7@34.29,43.815 35.56,42.545 35.56,38.735 35.877,38.417 46.038,38.417 48.578,35.877 48.578,28.892 51.269,26.201 55.113,26.201 55.406,25.908 81.494,25.908 81.671,25.731 81.671,22.332 81.842,22.161 R706_1.1@82.465,22.161 82.465,21.578 81.842,20.955 80.645,20.955 80.328,20.637 80.328,18.732 80.622,18.438 U700_1.11@81.605,18.438
PRIMARY-DIGITAL-IO_7: R707_1.1 U700_1.12 X402.8 | length 68.1
  Top w0.152: X402.8@34.29,41.275 34.29,38.417 34.587,38.088 45.719,38.101 48.26,35.56 48.26,28.734 51.047,25.947 55.008,25.947 55.3,25.654 79.843,25.654 80.084,25.413 80.084,22.332 80.255,22.161 R707_1.1@80.877,22.161 80.877,21.709 80.01,20.842 80.01,18.105 80.328,17.788 U700_1.12@81.605,17.788
PRIMARY-GPIO1-OPT: R1408_1.1 R1425_1.1 X404.5 | length 170.2
  Top w0.152: R1408_1.1@146.433,61.119 v1(147.32,61.119)
  Top w0.203: v1@15.748,29.337 R1425_1.1@15.748,30.161
  Signals2 w0.203: v1(15.732,29.337) 21.858,29.337 22.86,30.339 22.86,34.925 X404.5@24.13,36.195
  Signals1 w0.152: v1(34.608,61.912) 34.608,63.055 39.035,67.483 143.327,67.483 147.716,63.095 147.716,61.514 v1(147.32,61.119)
  Bottom w0.152: X404.5@24.13,36.195 24.11,38.088 24.935,38.913 28.158,38.913 29.507,40.263 29.507,52.693 29.825,53.01 34.27,53.011 34.587,53.328 34.608,53.348 v1(34.608,61.912)
PRIMARY-GPIO2-OPT: R1410_1.1 R1426_1.1 X404.7 | length 176.1
  Top w0.152: R1410_1.1@146.433,56.515 147.287,56.515 v1(147.3,56.503)
  Top w0.203: v1@14.351,29.337 R1426_1.1@14.351,30.161
  Signals2 w0.203: v1(14.335,29.337) 14.335,29.829 14.878,30.372 17.24,30.372 18.216,31.347 18.216,31.863 18.556,32.203 19.503,32.203 20.32,33.02 20.32,34.925 X404.7@21.59,36.195
  Signals1 w0.152: v1(33.975,62.547) 34.353,62.926 34.353,63.161 38.93,67.737 143.432,67.737 147.97,63.2 147.97,56.855 147.617,56.503 v1(147.3,56.503)
  Bottom w0.152: X404.7@21.59,36.195 21.57,38.405 22.332,39.167 28.053,39.167 29.19,40.304 29.19,53.01 29.507,53.328 33.635,53.328 33.952,53.645 33.975,53.667 v1(33.975,62.547)
PRIMARY-GPIO3-OPT: R1412_1.1 R1427_1.1 X404.9 | length 184
  Top w0.152: R1412_1.1@146.433,53.34 147.024,53.34 147.3,53.064 v1(147.3,52.451)
  Top w0.203: v1@12.954,29.337 R1427_1.1@12.954,30.161
  Signals2 w0.203: v1(12.938,29.337) 12.938,29.956 13.963,30.981 16.988,30.981 17.607,31.6 17.607,34.752 X404.9@19.05,36.195
  Signals1 w0.152: v1(33.337,63.817) 34.651,63.817 38.825,67.991 143.537,67.991 148.252,63.276 148.252,53.645 147.3,52.693 v1(147.3,52.451)
  Bottom w0.152: X404.9@19.05,36.195 19.03,38.723 19.728,39.421 27.947,39.421 28.872,40.346 28.872,53.328 29.19,53.645 33,53.645 33.317,53.961 33.337,53.981 v1(33.337,63.817)
PRIMARY-GPIO4-OPT: R1414_1.1 X404.11 | length 176.6
  Top w0.152: R1414_1.1@146.433,50.006 146.433,50.106 147.3,50.974 v1(147.3,51.105)
  Signals1 w0.152: v1(32.703,63.182) 32.703,63.967 36.981,68.245 143.643,68.245 148.506,63.381 148.506,52.876 148.417,52.786 148.417,52.222 v1(147.3,51.105)
  Bottom w0.152: X404.11@16.51,36.195 16.49,39.04 17.125,39.675 27.842,39.675 28.555,40.388 28.555,53.645 28.872,53.963 32.365,53.963 32.682,54.279 32.703,54.299 v1(32.703,63.182)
